VERSION 5.8 ;
BUSBITCHARS "[]" ;
DIVIDERCHAR "/" ;
UNITS
    DATABASE MICRONS 1000 ;
END UNITS

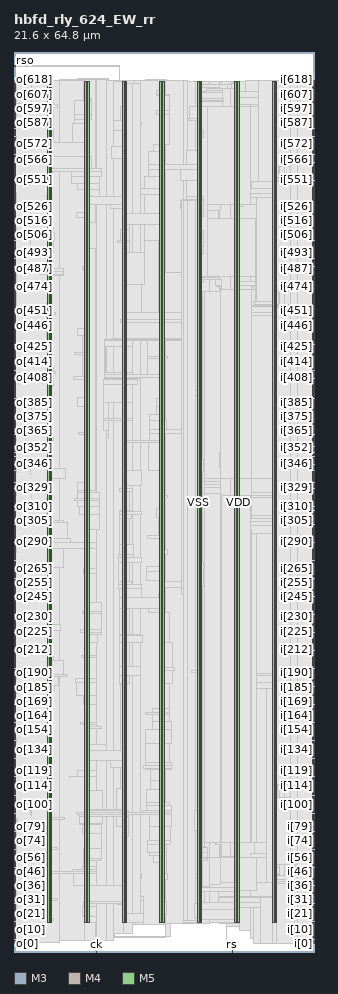
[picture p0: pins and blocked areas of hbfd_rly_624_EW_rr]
MACRO hbfd_rly_624_EW_rr
  FOREIGN hbfd_rly_624_EW_rr 0 0 ;
  CLASS BLOCK ;
  SIZE 21.6 BY 64.8 ;
  PIN ck
    DIRECTION INPUT ;
    USE SIGNAL ;
    PORT
      LAYER M3 ;
        RECT  5.904 0 5.922 0.038 ;
    END
  END ck
  PIN i[0]
    DIRECTION INPUT ;
    USE SIGNAL ;
    PORT
      LAYER M4 ;
        RECT  21.516 0.624 21.6 0.648 ;
    END
  END i[0]
  PIN i[100]
    DIRECTION INPUT ;
    USE SIGNAL ;
    PORT
      LAYER M4 ;
        RECT  21.516 10.608 21.6 10.632 ;
    END
  END i[100]
  PIN i[101]
    DIRECTION INPUT ;
    USE SIGNAL ;
    PORT
      LAYER M4 ;
        RECT  21.516 10.704 21.6 10.728 ;
    END
  END i[101]
  PIN i[102]
    DIRECTION INPUT ;
    USE SIGNAL ;
    PORT
      LAYER M4 ;
        RECT  21.516 10.8 21.6 10.824 ;
    END
  END i[102]
  PIN i[103]
    DIRECTION INPUT ;
    USE SIGNAL ;
    PORT
      LAYER M4 ;
        RECT  21.516 10.896 21.6 10.92 ;
    END
  END i[103]
  PIN i[104]
    DIRECTION INPUT ;
    USE SIGNAL ;
    PORT
      LAYER M4 ;
        RECT  21.516 10.992 21.6 11.016 ;
    END
  END i[104]
  PIN i[105]
    DIRECTION INPUT ;
    USE SIGNAL ;
    PORT
      LAYER M4 ;
        RECT  21.516 11.088 21.6 11.112 ;
    END
  END i[105]
  PIN i[106]
    DIRECTION INPUT ;
    USE SIGNAL ;
    PORT
      LAYER M4 ;
        RECT  21.516 11.184 21.6 11.208 ;
    END
  END i[106]
  PIN i[107]
    DIRECTION INPUT ;
    USE SIGNAL ;
    PORT
      LAYER M4 ;
        RECT  21.516 11.328 21.6 11.352 ;
    END
  END i[107]
  PIN i[108]
    DIRECTION INPUT ;
    USE SIGNAL ;
    PORT
      LAYER M4 ;
        RECT  21.516 11.424 21.6 11.448 ;
    END
  END i[108]
  PIN i[109]
    DIRECTION INPUT ;
    USE SIGNAL ;
    PORT
      LAYER M4 ;
        RECT  21.516 11.52 21.6 11.544 ;
    END
  END i[109]
  PIN i[10]
    DIRECTION INPUT ;
    USE SIGNAL ;
    PORT
      LAYER M4 ;
        RECT  21.516 1.632 21.6 1.656 ;
    END
  END i[10]
  PIN i[110]
    DIRECTION INPUT ;
    USE SIGNAL ;
    PORT
      LAYER M4 ;
        RECT  21.516 11.616 21.6 11.64 ;
    END
  END i[110]
  PIN i[111]
    DIRECTION INPUT ;
    USE SIGNAL ;
    PORT
      LAYER M4 ;
        RECT  21.516 11.712 21.6 11.736 ;
    END
  END i[111]
  PIN i[112]
    DIRECTION INPUT ;
    USE SIGNAL ;
    PORT
      LAYER M4 ;
        RECT  21.516 11.808 21.6 11.832 ;
    END
  END i[112]
  PIN i[113]
    DIRECTION INPUT ;
    USE SIGNAL ;
    PORT
      LAYER M4 ;
        RECT  21.516 11.904 21.6 11.928 ;
    END
  END i[113]
  PIN i[114]
    DIRECTION INPUT ;
    USE SIGNAL ;
    PORT
      LAYER M4 ;
        RECT  21.516 12 21.6 12.024 ;
    END
  END i[114]
  PIN i[115]
    DIRECTION INPUT ;
    USE SIGNAL ;
    PORT
      LAYER M4 ;
        RECT  21.516 12.096 21.6 12.12 ;
    END
  END i[115]
  PIN i[116]
    DIRECTION INPUT ;
    USE SIGNAL ;
    PORT
      LAYER M4 ;
        RECT  21.516 12.192 21.6 12.216 ;
    END
  END i[116]
  PIN i[117]
    DIRECTION INPUT ;
    USE SIGNAL ;
    PORT
      LAYER M4 ;
        RECT  21.516 12.288 21.6 12.312 ;
    END
  END i[117]
  PIN i[118]
    DIRECTION INPUT ;
    USE SIGNAL ;
    PORT
      LAYER M4 ;
        RECT  21.516 12.384 21.6 12.408 ;
    END
  END i[118]
  PIN i[119]
    DIRECTION INPUT ;
    USE SIGNAL ;
    PORT
      LAYER M4 ;
        RECT  21.516 12.48 21.6 12.504 ;
    END
  END i[119]
  PIN i[11]
    DIRECTION INPUT ;
    USE SIGNAL ;
    PORT
      LAYER M4 ;
        RECT  21.516 1.728 21.6 1.752 ;
    END
  END i[11]
  PIN i[120]
    DIRECTION INPUT ;
    USE SIGNAL ;
    PORT
      LAYER M4 ;
        RECT  21.516 12.576 21.6 12.6 ;
    END
  END i[120]
  PIN i[121]
    DIRECTION INPUT ;
    USE SIGNAL ;
    PORT
      LAYER M4 ;
        RECT  21.516 12.72 21.6 12.744 ;
    END
  END i[121]
  PIN i[122]
    DIRECTION INPUT ;
    USE SIGNAL ;
    PORT
      LAYER M4 ;
        RECT  21.516 12.816 21.6 12.84 ;
    END
  END i[122]
  PIN i[123]
    DIRECTION INPUT ;
    USE SIGNAL ;
    PORT
      LAYER M4 ;
        RECT  21.516 12.912 21.6 12.936 ;
    END
  END i[123]
  PIN i[124]
    DIRECTION INPUT ;
    USE SIGNAL ;
    PORT
      LAYER M4 ;
        RECT  21.516 13.008 21.6 13.032 ;
    END
  END i[124]
  PIN i[125]
    DIRECTION INPUT ;
    USE SIGNAL ;
    PORT
      LAYER M4 ;
        RECT  21.516 13.104 21.6 13.128 ;
    END
  END i[125]
  PIN i[126]
    DIRECTION INPUT ;
    USE SIGNAL ;
    PORT
      LAYER M4 ;
        RECT  21.516 13.2 21.6 13.224 ;
    END
  END i[126]
  PIN i[127]
    DIRECTION INPUT ;
    USE SIGNAL ;
    PORT
      LAYER M4 ;
        RECT  21.516 13.296 21.6 13.32 ;
    END
  END i[127]
  PIN i[128]
    DIRECTION INPUT ;
    USE SIGNAL ;
    PORT
      LAYER M4 ;
        RECT  21.516 13.392 21.6 13.416 ;
    END
  END i[128]
  PIN i[129]
    DIRECTION INPUT ;
    USE SIGNAL ;
    PORT
      LAYER M4 ;
        RECT  21.516 13.488 21.6 13.512 ;
    END
  END i[129]
  PIN i[12]
    DIRECTION INPUT ;
    USE SIGNAL ;
    PORT
      LAYER M4 ;
        RECT  21.516 1.824 21.6 1.848 ;
    END
  END i[12]
  PIN i[130]
    DIRECTION INPUT ;
    USE SIGNAL ;
    PORT
      LAYER M4 ;
        RECT  21.516 13.584 21.6 13.608 ;
    END
  END i[130]
  PIN i[131]
    DIRECTION INPUT ;
    USE SIGNAL ;
    PORT
      LAYER M4 ;
        RECT  21.516 13.68 21.6 13.704 ;
    END
  END i[131]
  PIN i[132]
    DIRECTION INPUT ;
    USE SIGNAL ;
    PORT
      LAYER M4 ;
        RECT  21.516 13.776 21.6 13.8 ;
    END
  END i[132]
  PIN i[133]
    DIRECTION INPUT ;
    USE SIGNAL ;
    PORT
      LAYER M4 ;
        RECT  21.516 13.872 21.6 13.896 ;
    END
  END i[133]
  PIN i[134]
    DIRECTION INPUT ;
    USE SIGNAL ;
    PORT
      LAYER M4 ;
        RECT  21.516 14.016 21.6 14.04 ;
    END
  END i[134]
  PIN i[135]
    DIRECTION INPUT ;
    USE SIGNAL ;
    PORT
      LAYER M4 ;
        RECT  21.516 14.112 21.6 14.136 ;
    END
  END i[135]
  PIN i[136]
    DIRECTION INPUT ;
    USE SIGNAL ;
    PORT
      LAYER M4 ;
        RECT  21.516 14.208 21.6 14.232 ;
    END
  END i[136]
  PIN i[137]
    DIRECTION INPUT ;
    USE SIGNAL ;
    PORT
      LAYER M4 ;
        RECT  21.516 14.304 21.6 14.328 ;
    END
  END i[137]
  PIN i[138]
    DIRECTION INPUT ;
    USE SIGNAL ;
    PORT
      LAYER M4 ;
        RECT  21.516 14.4 21.6 14.424 ;
    END
  END i[138]
  PIN i[139]
    DIRECTION INPUT ;
    USE SIGNAL ;
    PORT
      LAYER M4 ;
        RECT  21.516 14.496 21.6 14.52 ;
    END
  END i[139]
  PIN i[13]
    DIRECTION INPUT ;
    USE SIGNAL ;
    PORT
      LAYER M4 ;
        RECT  21.516 1.92 21.6 1.944 ;
    END
  END i[13]
  PIN i[140]
    DIRECTION INPUT ;
    USE SIGNAL ;
    PORT
      LAYER M4 ;
        RECT  21.516 14.592 21.6 14.616 ;
    END
  END i[140]
  PIN i[141]
    DIRECTION INPUT ;
    USE SIGNAL ;
    PORT
      LAYER M4 ;
        RECT  21.516 14.688 21.6 14.712 ;
    END
  END i[141]
  PIN i[142]
    DIRECTION INPUT ;
    USE SIGNAL ;
    PORT
      LAYER M4 ;
        RECT  21.516 14.784 21.6 14.808 ;
    END
  END i[142]
  PIN i[143]
    DIRECTION INPUT ;
    USE SIGNAL ;
    PORT
      LAYER M4 ;
        RECT  21.516 14.88 21.6 14.904 ;
    END
  END i[143]
  PIN i[144]
    DIRECTION INPUT ;
    USE SIGNAL ;
    PORT
      LAYER M4 ;
        RECT  21.516 14.976 21.6 15 ;
    END
  END i[144]
  PIN i[145]
    DIRECTION INPUT ;
    USE SIGNAL ;
    PORT
      LAYER M4 ;
        RECT  21.516 15.072 21.6 15.096 ;
    END
  END i[145]
  PIN i[146]
    DIRECTION INPUT ;
    USE SIGNAL ;
    PORT
      LAYER M4 ;
        RECT  21.516 15.168 21.6 15.192 ;
    END
  END i[146]
  PIN i[147]
    DIRECTION INPUT ;
    USE SIGNAL ;
    PORT
      LAYER M4 ;
        RECT  21.516 15.312 21.6 15.336 ;
    END
  END i[147]
  PIN i[148]
    DIRECTION INPUT ;
    USE SIGNAL ;
    PORT
      LAYER M4 ;
        RECT  21.516 15.408 21.6 15.432 ;
    END
  END i[148]
  PIN i[149]
    DIRECTION INPUT ;
    USE SIGNAL ;
    PORT
      LAYER M4 ;
        RECT  21.516 15.504 21.6 15.528 ;
    END
  END i[149]
  PIN i[14]
    DIRECTION INPUT ;
    USE SIGNAL ;
    PORT
      LAYER M4 ;
        RECT  21.516 2.016 21.6 2.04 ;
    END
  END i[14]
  PIN i[150]
    DIRECTION INPUT ;
    USE SIGNAL ;
    PORT
      LAYER M4 ;
        RECT  21.516 15.6 21.6 15.624 ;
    END
  END i[150]
  PIN i[151]
    DIRECTION INPUT ;
    USE SIGNAL ;
    PORT
      LAYER M4 ;
        RECT  21.516 15.696 21.6 15.72 ;
    END
  END i[151]
  PIN i[152]
    DIRECTION INPUT ;
    USE SIGNAL ;
    PORT
      LAYER M4 ;
        RECT  21.516 15.792 21.6 15.816 ;
    END
  END i[152]
  PIN i[153]
    DIRECTION INPUT ;
    USE SIGNAL ;
    PORT
      LAYER M4 ;
        RECT  21.516 15.888 21.6 15.912 ;
    END
  END i[153]
  PIN i[154]
    DIRECTION INPUT ;
    USE SIGNAL ;
    PORT
      LAYER M4 ;
        RECT  21.516 15.984 21.6 16.008 ;
    END
  END i[154]
  PIN i[155]
    DIRECTION INPUT ;
    USE SIGNAL ;
    PORT
      LAYER M4 ;
        RECT  21.516 16.08 21.6 16.104 ;
    END
  END i[155]
  PIN i[156]
    DIRECTION INPUT ;
    USE SIGNAL ;
    PORT
      LAYER M4 ;
        RECT  21.516 16.176 21.6 16.2 ;
    END
  END i[156]
  PIN i[157]
    DIRECTION INPUT ;
    USE SIGNAL ;
    PORT
      LAYER M4 ;
        RECT  21.516 16.272 21.6 16.296 ;
    END
  END i[157]
  PIN i[158]
    DIRECTION INPUT ;
    USE SIGNAL ;
    PORT
      LAYER M4 ;
        RECT  21.516 16.368 21.6 16.392 ;
    END
  END i[158]
  PIN i[159]
    DIRECTION INPUT ;
    USE SIGNAL ;
    PORT
      LAYER M4 ;
        RECT  21.516 16.464 21.6 16.488 ;
    END
  END i[159]
  PIN i[15]
    DIRECTION INPUT ;
    USE SIGNAL ;
    PORT
      LAYER M4 ;
        RECT  21.516 2.112 21.6 2.136 ;
    END
  END i[15]
  PIN i[160]
    DIRECTION INPUT ;
    USE SIGNAL ;
    PORT
      LAYER M4 ;
        RECT  21.516 16.608 21.6 16.632 ;
    END
  END i[160]
  PIN i[161]
    DIRECTION INPUT ;
    USE SIGNAL ;
    PORT
      LAYER M4 ;
        RECT  21.516 16.704 21.6 16.728 ;
    END
  END i[161]
  PIN i[162]
    DIRECTION INPUT ;
    USE SIGNAL ;
    PORT
      LAYER M4 ;
        RECT  21.516 16.8 21.6 16.824 ;
    END
  END i[162]
  PIN i[163]
    DIRECTION INPUT ;
    USE SIGNAL ;
    PORT
      LAYER M4 ;
        RECT  21.516 16.896 21.6 16.92 ;
    END
  END i[163]
  PIN i[164]
    DIRECTION INPUT ;
    USE SIGNAL ;
    PORT
      LAYER M4 ;
        RECT  21.516 16.992 21.6 17.016 ;
    END
  END i[164]
  PIN i[165]
    DIRECTION INPUT ;
    USE SIGNAL ;
    PORT
      LAYER M4 ;
        RECT  21.516 17.088 21.6 17.112 ;
    END
  END i[165]
  PIN i[166]
    DIRECTION INPUT ;
    USE SIGNAL ;
    PORT
      LAYER M4 ;
        RECT  21.516 17.184 21.6 17.208 ;
    END
  END i[166]
  PIN i[167]
    DIRECTION INPUT ;
    USE SIGNAL ;
    PORT
      LAYER M4 ;
        RECT  21.516 17.28 21.6 17.304 ;
    END
  END i[167]
  PIN i[168]
    DIRECTION INPUT ;
    USE SIGNAL ;
    PORT
      LAYER M4 ;
        RECT  21.516 17.376 21.6 17.4 ;
    END
  END i[168]
  PIN i[169]
    DIRECTION INPUT ;
    USE SIGNAL ;
    PORT
      LAYER M4 ;
        RECT  21.516 17.472 21.6 17.496 ;
    END
  END i[169]
  PIN i[16]
    DIRECTION INPUT ;
    USE SIGNAL ;
    PORT
      LAYER M4 ;
        RECT  21.516 2.256 21.6 2.28 ;
    END
  END i[16]
  PIN i[170]
    DIRECTION INPUT ;
    USE SIGNAL ;
    PORT
      LAYER M4 ;
        RECT  21.516 17.568 21.6 17.592 ;
    END
  END i[170]
  PIN i[171]
    DIRECTION INPUT ;
    USE SIGNAL ;
    PORT
      LAYER M4 ;
        RECT  21.516 17.664 21.6 17.688 ;
    END
  END i[171]
  PIN i[172]
    DIRECTION INPUT ;
    USE SIGNAL ;
    PORT
      LAYER M4 ;
        RECT  21.516 17.76 21.6 17.784 ;
    END
  END i[172]
  PIN i[173]
    DIRECTION INPUT ;
    USE SIGNAL ;
    PORT
      LAYER M4 ;
        RECT  21.516 17.904 21.6 17.928 ;
    END
  END i[173]
  PIN i[174]
    DIRECTION INPUT ;
    USE SIGNAL ;
    PORT
      LAYER M4 ;
        RECT  21.516 18 21.6 18.024 ;
    END
  END i[174]
  PIN i[175]
    DIRECTION INPUT ;
    USE SIGNAL ;
    PORT
      LAYER M4 ;
        RECT  21.516 18.096 21.6 18.12 ;
    END
  END i[175]
  PIN i[176]
    DIRECTION INPUT ;
    USE SIGNAL ;
    PORT
      LAYER M4 ;
        RECT  21.516 18.192 21.6 18.216 ;
    END
  END i[176]
  PIN i[177]
    DIRECTION INPUT ;
    USE SIGNAL ;
    PORT
      LAYER M4 ;
        RECT  21.516 18.288 21.6 18.312 ;
    END
  END i[177]
  PIN i[178]
    DIRECTION INPUT ;
    USE SIGNAL ;
    PORT
      LAYER M4 ;
        RECT  21.516 18.384 21.6 18.408 ;
    END
  END i[178]
  PIN i[179]
    DIRECTION INPUT ;
    USE SIGNAL ;
    PORT
      LAYER M4 ;
        RECT  21.516 18.48 21.6 18.504 ;
    END
  END i[179]
  PIN i[17]
    DIRECTION INPUT ;
    USE SIGNAL ;
    PORT
      LAYER M4 ;
        RECT  21.516 2.352 21.6 2.376 ;
    END
  END i[17]
  PIN i[180]
    DIRECTION INPUT ;
    USE SIGNAL ;
    PORT
      LAYER M4 ;
        RECT  21.516 18.576 21.6 18.6 ;
    END
  END i[180]
  PIN i[181]
    DIRECTION INPUT ;
    USE SIGNAL ;
    PORT
      LAYER M4 ;
        RECT  21.516 18.672 21.6 18.696 ;
    END
  END i[181]
  PIN i[182]
    DIRECTION INPUT ;
    USE SIGNAL ;
    PORT
      LAYER M4 ;
        RECT  21.516 18.768 21.6 18.792 ;
    END
  END i[182]
  PIN i[183]
    DIRECTION INPUT ;
    USE SIGNAL ;
    PORT
      LAYER M4 ;
        RECT  21.516 18.864 21.6 18.888 ;
    END
  END i[183]
  PIN i[184]
    DIRECTION INPUT ;
    USE SIGNAL ;
    PORT
      LAYER M4 ;
        RECT  21.516 18.96 21.6 18.984 ;
    END
  END i[184]
  PIN i[185]
    DIRECTION INPUT ;
    USE SIGNAL ;
    PORT
      LAYER M4 ;
        RECT  21.516 19.056 21.6 19.08 ;
    END
  END i[185]
  PIN i[186]
    DIRECTION INPUT ;
    USE SIGNAL ;
    PORT
      LAYER M4 ;
        RECT  21.516 19.2 21.6 19.224 ;
    END
  END i[186]
  PIN i[187]
    DIRECTION INPUT ;
    USE SIGNAL ;
    PORT
      LAYER M4 ;
        RECT  21.516 19.296 21.6 19.32 ;
    END
  END i[187]
  PIN i[188]
    DIRECTION INPUT ;
    USE SIGNAL ;
    PORT
      LAYER M4 ;
        RECT  21.516 19.392 21.6 19.416 ;
    END
  END i[188]
  PIN i[189]
    DIRECTION INPUT ;
    USE SIGNAL ;
    PORT
      LAYER M4 ;
        RECT  21.516 19.488 21.6 19.512 ;
    END
  END i[189]
  PIN i[18]
    DIRECTION INPUT ;
    USE SIGNAL ;
    PORT
      LAYER M4 ;
        RECT  21.516 2.448 21.6 2.472 ;
    END
  END i[18]
  PIN i[190]
    DIRECTION INPUT ;
    USE SIGNAL ;
    PORT
      LAYER M4 ;
        RECT  21.516 19.584 21.6 19.608 ;
    END
  END i[190]
  PIN i[191]
    DIRECTION INPUT ;
    USE SIGNAL ;
    PORT
      LAYER M4 ;
        RECT  21.516 19.68 21.6 19.704 ;
    END
  END i[191]
  PIN i[192]
    DIRECTION INPUT ;
    USE SIGNAL ;
    PORT
      LAYER M4 ;
        RECT  21.516 19.776 21.6 19.8 ;
    END
  END i[192]
  PIN i[193]
    DIRECTION INPUT ;
    USE SIGNAL ;
    PORT
      LAYER M4 ;
        RECT  21.516 19.872 21.6 19.896 ;
    END
  END i[193]
  PIN i[194]
    DIRECTION INPUT ;
    USE SIGNAL ;
    PORT
      LAYER M4 ;
        RECT  21.516 19.968 21.6 19.992 ;
    END
  END i[194]
  PIN i[195]
    DIRECTION INPUT ;
    USE SIGNAL ;
    PORT
      LAYER M4 ;
        RECT  21.516 20.064 21.6 20.088 ;
    END
  END i[195]
  PIN i[196]
    DIRECTION INPUT ;
    USE SIGNAL ;
    PORT
      LAYER M4 ;
        RECT  21.516 20.16 21.6 20.184 ;
    END
  END i[196]
  PIN i[197]
    DIRECTION INPUT ;
    USE SIGNAL ;
    PORT
      LAYER M4 ;
        RECT  21.516 20.256 21.6 20.28 ;
    END
  END i[197]
  PIN i[198]
    DIRECTION INPUT ;
    USE SIGNAL ;
    PORT
      LAYER M4 ;
        RECT  21.516 20.352 21.6 20.376 ;
    END
  END i[198]
  PIN i[199]
    DIRECTION INPUT ;
    USE SIGNAL ;
    PORT
      LAYER M4 ;
        RECT  21.516 20.496 21.6 20.52 ;
    END
  END i[199]
  PIN i[19]
    DIRECTION INPUT ;
    USE SIGNAL ;
    PORT
      LAYER M4 ;
        RECT  21.516 2.544 21.6 2.568 ;
    END
  END i[19]
  PIN i[1]
    DIRECTION INPUT ;
    USE SIGNAL ;
    PORT
      LAYER M4 ;
        RECT  21.516 0.72 21.6 0.744 ;
    END
  END i[1]
  PIN i[200]
    DIRECTION INPUT ;
    USE SIGNAL ;
    PORT
      LAYER M4 ;
        RECT  21.516 20.592 21.6 20.616 ;
    END
  END i[200]
  PIN i[201]
    DIRECTION INPUT ;
    USE SIGNAL ;
    PORT
      LAYER M4 ;
        RECT  21.516 20.688 21.6 20.712 ;
    END
  END i[201]
  PIN i[202]
    DIRECTION INPUT ;
    USE SIGNAL ;
    PORT
      LAYER M4 ;
        RECT  21.516 20.784 21.6 20.808 ;
    END
  END i[202]
  PIN i[203]
    DIRECTION INPUT ;
    USE SIGNAL ;
    PORT
      LAYER M4 ;
        RECT  21.516 20.88 21.6 20.904 ;
    END
  END i[203]
  PIN i[204]
    DIRECTION INPUT ;
    USE SIGNAL ;
    PORT
      LAYER M4 ;
        RECT  21.516 20.976 21.6 21 ;
    END
  END i[204]
  PIN i[205]
    DIRECTION INPUT ;
    USE SIGNAL ;
    PORT
      LAYER M4 ;
        RECT  21.516 21.072 21.6 21.096 ;
    END
  END i[205]
  PIN i[206]
    DIRECTION INPUT ;
    USE SIGNAL ;
    PORT
      LAYER M4 ;
        RECT  21.516 21.168 21.6 21.192 ;
    END
  END i[206]
  PIN i[207]
    DIRECTION INPUT ;
    USE SIGNAL ;
    PORT
      LAYER M4 ;
        RECT  21.516 21.264 21.6 21.288 ;
    END
  END i[207]
  PIN i[208]
    DIRECTION INPUT ;
    USE SIGNAL ;
    PORT
      LAYER M4 ;
        RECT  21.516 21.36 21.6 21.384 ;
    END
  END i[208]
  PIN i[209]
    DIRECTION INPUT ;
    USE SIGNAL ;
    PORT
      LAYER M4 ;
        RECT  21.516 21.456 21.6 21.48 ;
    END
  END i[209]
  PIN i[20]
    DIRECTION INPUT ;
    USE SIGNAL ;
    PORT
      LAYER M4 ;
        RECT  21.516 2.64 21.6 2.664 ;
    END
  END i[20]
  PIN i[210]
    DIRECTION INPUT ;
    USE SIGNAL ;
    PORT
      LAYER M4 ;
        RECT  21.516 21.552 21.6 21.576 ;
    END
  END i[210]
  PIN i[211]
    DIRECTION INPUT ;
    USE SIGNAL ;
    PORT
      LAYER M4 ;
        RECT  21.516 21.648 21.6 21.672 ;
    END
  END i[211]
  PIN i[212]
    DIRECTION INPUT ;
    USE SIGNAL ;
    PORT
      LAYER M4 ;
        RECT  21.516 21.792 21.6 21.816 ;
    END
  END i[212]
  PIN i[213]
    DIRECTION INPUT ;
    USE SIGNAL ;
    PORT
      LAYER M4 ;
        RECT  21.516 21.888 21.6 21.912 ;
    END
  END i[213]
  PIN i[214]
    DIRECTION INPUT ;
    USE SIGNAL ;
    PORT
      LAYER M4 ;
        RECT  21.516 21.984 21.6 22.008 ;
    END
  END i[214]
  PIN i[215]
    DIRECTION INPUT ;
    USE SIGNAL ;
    PORT
      LAYER M4 ;
        RECT  21.516 22.08 21.6 22.104 ;
    END
  END i[215]
  PIN i[216]
    DIRECTION INPUT ;
    USE SIGNAL ;
    PORT
      LAYER M4 ;
        RECT  21.516 22.176 21.6 22.2 ;
    END
  END i[216]
  PIN i[217]
    DIRECTION INPUT ;
    USE SIGNAL ;
    PORT
      LAYER M4 ;
        RECT  21.516 22.272 21.6 22.296 ;
    END
  END i[217]
  PIN i[218]
    DIRECTION INPUT ;
    USE SIGNAL ;
    PORT
      LAYER M4 ;
        RECT  21.516 22.368 21.6 22.392 ;
    END
  END i[218]
  PIN i[219]
    DIRECTION INPUT ;
    USE SIGNAL ;
    PORT
      LAYER M4 ;
        RECT  21.516 22.464 21.6 22.488 ;
    END
  END i[219]
  PIN i[21]
    DIRECTION INPUT ;
    USE SIGNAL ;
    PORT
      LAYER M4 ;
        RECT  21.516 2.736 21.6 2.76 ;
    END
  END i[21]
  PIN i[220]
    DIRECTION INPUT ;
    USE SIGNAL ;
    PORT
      LAYER M4 ;
        RECT  21.516 22.56 21.6 22.584 ;
    END
  END i[220]
  PIN i[221]
    DIRECTION INPUT ;
    USE SIGNAL ;
    PORT
      LAYER M4 ;
        RECT  21.516 22.656 21.6 22.68 ;
    END
  END i[221]
  PIN i[222]
    DIRECTION INPUT ;
    USE SIGNAL ;
    PORT
      LAYER M4 ;
        RECT  21.516 22.752 21.6 22.776 ;
    END
  END i[222]
  PIN i[223]
    DIRECTION INPUT ;
    USE SIGNAL ;
    PORT
      LAYER M4 ;
        RECT  21.516 22.848 21.6 22.872 ;
    END
  END i[223]
  PIN i[224]
    DIRECTION INPUT ;
    USE SIGNAL ;
    PORT
      LAYER M4 ;
        RECT  21.516 22.944 21.6 22.968 ;
    END
  END i[224]
  PIN i[225]
    DIRECTION INPUT ;
    USE SIGNAL ;
    PORT
      LAYER M4 ;
        RECT  21.516 23.088 21.6 23.112 ;
    END
  END i[225]
  PIN i[226]
    DIRECTION INPUT ;
    USE SIGNAL ;
    PORT
      LAYER M4 ;
        RECT  21.516 23.184 21.6 23.208 ;
    END
  END i[226]
  PIN i[227]
    DIRECTION INPUT ;
    USE SIGNAL ;
    PORT
      LAYER M4 ;
        RECT  21.516 23.28 21.6 23.304 ;
    END
  END i[227]
  PIN i[228]
    DIRECTION INPUT ;
    USE SIGNAL ;
    PORT
      LAYER M4 ;
        RECT  21.516 23.376 21.6 23.4 ;
    END
  END i[228]
  PIN i[229]
    DIRECTION INPUT ;
    USE SIGNAL ;
    PORT
      LAYER M4 ;
        RECT  21.516 23.472 21.6 23.496 ;
    END
  END i[229]
  PIN i[22]
    DIRECTION INPUT ;
    USE SIGNAL ;
    PORT
      LAYER M4 ;
        RECT  21.516 2.832 21.6 2.856 ;
    END
  END i[22]
  PIN i[230]
    DIRECTION INPUT ;
    USE SIGNAL ;
    PORT
      LAYER M4 ;
        RECT  21.516 23.568 21.6 23.592 ;
    END
  END i[230]
  PIN i[231]
    DIRECTION INPUT ;
    USE SIGNAL ;
    PORT
      LAYER M4 ;
        RECT  21.516 23.664 21.6 23.688 ;
    END
  END i[231]
  PIN i[232]
    DIRECTION INPUT ;
    USE SIGNAL ;
    PORT
      LAYER M4 ;
        RECT  21.516 23.76 21.6 23.784 ;
    END
  END i[232]
  PIN i[233]
    DIRECTION INPUT ;
    USE SIGNAL ;
    PORT
      LAYER M4 ;
        RECT  21.516 23.856 21.6 23.88 ;
    END
  END i[233]
  PIN i[234]
    DIRECTION INPUT ;
    USE SIGNAL ;
    PORT
      LAYER M4 ;
        RECT  21.516 23.952 21.6 23.976 ;
    END
  END i[234]
  PIN i[235]
    DIRECTION INPUT ;
    USE SIGNAL ;
    PORT
      LAYER M4 ;
        RECT  21.516 24.048 21.6 24.072 ;
    END
  END i[235]
  PIN i[236]
    DIRECTION INPUT ;
    USE SIGNAL ;
    PORT
      LAYER M4 ;
        RECT  21.516 24.144 21.6 24.168 ;
    END
  END i[236]
  PIN i[237]
    DIRECTION INPUT ;
    USE SIGNAL ;
    PORT
      LAYER M4 ;
        RECT  21.516 24.24 21.6 24.264 ;
    END
  END i[237]
  PIN i[238]
    DIRECTION INPUT ;
    USE SIGNAL ;
    PORT
      LAYER M4 ;
        RECT  21.516 24.384 21.6 24.408 ;
    END
  END i[238]
  PIN i[239]
    DIRECTION INPUT ;
    USE SIGNAL ;
    PORT
      LAYER M4 ;
        RECT  21.516 24.48 21.6 24.504 ;
    END
  END i[239]
  PIN i[23]
    DIRECTION INPUT ;
    USE SIGNAL ;
    PORT
      LAYER M4 ;
        RECT  21.516 2.928 21.6 2.952 ;
    END
  END i[23]
  PIN i[240]
    DIRECTION INPUT ;
    USE SIGNAL ;
    PORT
      LAYER M4 ;
        RECT  21.516 24.576 21.6 24.6 ;
    END
  END i[240]
  PIN i[241]
    DIRECTION INPUT ;
    USE SIGNAL ;
    PORT
      LAYER M4 ;
        RECT  21.516 24.672 21.6 24.696 ;
    END
  END i[241]
  PIN i[242]
    DIRECTION INPUT ;
    USE SIGNAL ;
    PORT
      LAYER M4 ;
        RECT  21.516 24.768 21.6 24.792 ;
    END
  END i[242]
  PIN i[243]
    DIRECTION INPUT ;
    USE SIGNAL ;
    PORT
      LAYER M4 ;
        RECT  21.516 24.864 21.6 24.888 ;
    END
  END i[243]
  PIN i[244]
    DIRECTION INPUT ;
    USE SIGNAL ;
    PORT
      LAYER M4 ;
        RECT  21.516 24.96 21.6 24.984 ;
    END
  END i[244]
  PIN i[245]
    DIRECTION INPUT ;
    USE SIGNAL ;
    PORT
      LAYER M4 ;
        RECT  21.516 25.056 21.6 25.08 ;
    END
  END i[245]
  PIN i[246]
    DIRECTION INPUT ;
    USE SIGNAL ;
    PORT
      LAYER M4 ;
        RECT  21.516 25.152 21.6 25.176 ;
    END
  END i[246]
  PIN i[247]
    DIRECTION INPUT ;
    USE SIGNAL ;
    PORT
      LAYER M4 ;
        RECT  21.516 25.248 21.6 25.272 ;
    END
  END i[247]
  PIN i[248]
    DIRECTION INPUT ;
    USE SIGNAL ;
    PORT
      LAYER M4 ;
        RECT  21.516 25.344 21.6 25.368 ;
    END
  END i[248]
  PIN i[249]
    DIRECTION INPUT ;
    USE SIGNAL ;
    PORT
      LAYER M4 ;
        RECT  21.516 25.44 21.6 25.464 ;
    END
  END i[249]
  PIN i[24]
    DIRECTION INPUT ;
    USE SIGNAL ;
    PORT
      LAYER M4 ;
        RECT  21.516 3.024 21.6 3.048 ;
    END
  END i[24]
  PIN i[250]
    DIRECTION INPUT ;
    USE SIGNAL ;
    PORT
      LAYER M4 ;
        RECT  21.516 25.536 21.6 25.56 ;
    END
  END i[250]
  PIN i[251]
    DIRECTION INPUT ;
    USE SIGNAL ;
    PORT
      LAYER M4 ;
        RECT  21.516 25.68 21.6 25.704 ;
    END
  END i[251]
  PIN i[252]
    DIRECTION INPUT ;
    USE SIGNAL ;
    PORT
      LAYER M4 ;
        RECT  21.516 25.776 21.6 25.8 ;
    END
  END i[252]
  PIN i[253]
    DIRECTION INPUT ;
    USE SIGNAL ;
    PORT
      LAYER M4 ;
        RECT  21.516 25.872 21.6 25.896 ;
    END
  END i[253]
  PIN i[254]
    DIRECTION INPUT ;
    USE SIGNAL ;
    PORT
      LAYER M4 ;
        RECT  21.516 25.968 21.6 25.992 ;
    END
  END i[254]
  PIN i[255]
    DIRECTION INPUT ;
    USE SIGNAL ;
    PORT
      LAYER M4 ;
        RECT  21.516 26.064 21.6 26.088 ;
    END
  END i[255]
  PIN i[256]
    DIRECTION INPUT ;
    USE SIGNAL ;
    PORT
      LAYER M4 ;
        RECT  21.516 26.16 21.6 26.184 ;
    END
  END i[256]
  PIN i[257]
    DIRECTION INPUT ;
    USE SIGNAL ;
    PORT
      LAYER M4 ;
        RECT  21.516 26.256 21.6 26.28 ;
    END
  END i[257]
  PIN i[258]
    DIRECTION INPUT ;
    USE SIGNAL ;
    PORT
      LAYER M4 ;
        RECT  21.516 26.352 21.6 26.376 ;
    END
  END i[258]
  PIN i[259]
    DIRECTION INPUT ;
    USE SIGNAL ;
    PORT
      LAYER M4 ;
        RECT  21.516 26.448 21.6 26.472 ;
    END
  END i[259]
  PIN i[25]
    DIRECTION INPUT ;
    USE SIGNAL ;
    PORT
      LAYER M4 ;
        RECT  21.516 3.12 21.6 3.144 ;
    END
  END i[25]
  PIN i[260]
    DIRECTION INPUT ;
    USE SIGNAL ;
    PORT
      LAYER M4 ;
        RECT  21.516 26.544 21.6 26.568 ;
    END
  END i[260]
  PIN i[261]
    DIRECTION INPUT ;
    USE SIGNAL ;
    PORT
      LAYER M4 ;
        RECT  21.516 26.64 21.6 26.664 ;
    END
  END i[261]
  PIN i[262]
    DIRECTION INPUT ;
    USE SIGNAL ;
    PORT
      LAYER M4 ;
        RECT  21.516 26.736 21.6 26.76 ;
    END
  END i[262]
  PIN i[263]
    DIRECTION INPUT ;
    USE SIGNAL ;
    PORT
      LAYER M4 ;
        RECT  21.516 26.832 21.6 26.856 ;
    END
  END i[263]
  PIN i[264]
    DIRECTION INPUT ;
    USE SIGNAL ;
    PORT
      LAYER M4 ;
        RECT  21.516 26.976 21.6 27 ;
    END
  END i[264]
  PIN i[265]
    DIRECTION INPUT ;
    USE SIGNAL ;
    PORT
      LAYER M4 ;
        RECT  21.516 27.072 21.6 27.096 ;
    END
  END i[265]
  PIN i[266]
    DIRECTION INPUT ;
    USE SIGNAL ;
    PORT
      LAYER M4 ;
        RECT  21.516 27.168 21.6 27.192 ;
    END
  END i[266]
  PIN i[267]
    DIRECTION INPUT ;
    USE SIGNAL ;
    PORT
      LAYER M4 ;
        RECT  21.516 27.264 21.6 27.288 ;
    END
  END i[267]
  PIN i[268]
    DIRECTION INPUT ;
    USE SIGNAL ;
    PORT
      LAYER M4 ;
        RECT  21.516 27.36 21.6 27.384 ;
    END
  END i[268]
  PIN i[269]
    DIRECTION INPUT ;
    USE SIGNAL ;
    PORT
      LAYER M4 ;
        RECT  21.516 27.456 21.6 27.48 ;
    END
  END i[269]
  PIN i[26]
    DIRECTION INPUT ;
    USE SIGNAL ;
    PORT
      LAYER M4 ;
        RECT  21.516 3.216 21.6 3.24 ;
    END
  END i[26]
  PIN i[270]
    DIRECTION INPUT ;
    USE SIGNAL ;
    PORT
      LAYER M4 ;
        RECT  21.516 27.552 21.6 27.576 ;
    END
  END i[270]
  PIN i[271]
    DIRECTION INPUT ;
    USE SIGNAL ;
    PORT
      LAYER M4 ;
        RECT  21.516 27.648 21.6 27.672 ;
    END
  END i[271]
  PIN i[272]
    DIRECTION INPUT ;
    USE SIGNAL ;
    PORT
      LAYER M4 ;
        RECT  21.516 27.744 21.6 27.768 ;
    END
  END i[272]
  PIN i[273]
    DIRECTION INPUT ;
    USE SIGNAL ;
    PORT
      LAYER M4 ;
        RECT  21.516 27.84 21.6 27.864 ;
    END
  END i[273]
  PIN i[274]
    DIRECTION INPUT ;
    USE SIGNAL ;
    PORT
      LAYER M4 ;
        RECT  21.516 27.936 21.6 27.96 ;
    END
  END i[274]
  PIN i[275]
    DIRECTION INPUT ;
    USE SIGNAL ;
    PORT
      LAYER M4 ;
        RECT  21.516 28.032 21.6 28.056 ;
    END
  END i[275]
  PIN i[276]
    DIRECTION INPUT ;
    USE SIGNAL ;
    PORT
      LAYER M4 ;
        RECT  21.516 28.128 21.6 28.152 ;
    END
  END i[276]
  PIN i[277]
    DIRECTION INPUT ;
    USE SIGNAL ;
    PORT
      LAYER M4 ;
        RECT  21.516 28.272 21.6 28.296 ;
    END
  END i[277]
  PIN i[278]
    DIRECTION INPUT ;
    USE SIGNAL ;
    PORT
      LAYER M4 ;
        RECT  21.516 28.368 21.6 28.392 ;
    END
  END i[278]
  PIN i[279]
    DIRECTION INPUT ;
    USE SIGNAL ;
    PORT
      LAYER M4 ;
        RECT  21.516 28.464 21.6 28.488 ;
    END
  END i[279]
  PIN i[27]
    DIRECTION INPUT ;
    USE SIGNAL ;
    PORT
      LAYER M4 ;
        RECT  21.516 3.312 21.6 3.336 ;
    END
  END i[27]
  PIN i[280]
    DIRECTION INPUT ;
    USE SIGNAL ;
    PORT
      LAYER M4 ;
        RECT  21.516 28.56 21.6 28.584 ;
    END
  END i[280]
  PIN i[281]
    DIRECTION INPUT ;
    USE SIGNAL ;
    PORT
      LAYER M4 ;
        RECT  21.516 28.656 21.6 28.68 ;
    END
  END i[281]
  PIN i[282]
    DIRECTION INPUT ;
    USE SIGNAL ;
    PORT
      LAYER M4 ;
        RECT  21.516 28.752 21.6 28.776 ;
    END
  END i[282]
  PIN i[283]
    DIRECTION INPUT ;
    USE SIGNAL ;
    PORT
      LAYER M4 ;
        RECT  21.516 28.848 21.6 28.872 ;
    END
  END i[283]
  PIN i[284]
    DIRECTION INPUT ;
    USE SIGNAL ;
    PORT
      LAYER M4 ;
        RECT  21.516 28.944 21.6 28.968 ;
    END
  END i[284]
  PIN i[285]
    DIRECTION INPUT ;
    USE SIGNAL ;
    PORT
      LAYER M4 ;
        RECT  21.516 29.04 21.6 29.064 ;
    END
  END i[285]
  PIN i[286]
    DIRECTION INPUT ;
    USE SIGNAL ;
    PORT
      LAYER M4 ;
        RECT  21.516 29.136 21.6 29.16 ;
    END
  END i[286]
  PIN i[287]
    DIRECTION INPUT ;
    USE SIGNAL ;
    PORT
      LAYER M4 ;
        RECT  21.516 29.232 21.6 29.256 ;
    END
  END i[287]
  PIN i[288]
    DIRECTION INPUT ;
    USE SIGNAL ;
    PORT
      LAYER M4 ;
        RECT  21.516 29.328 21.6 29.352 ;
    END
  END i[288]
  PIN i[289]
    DIRECTION INPUT ;
    USE SIGNAL ;
    PORT
      LAYER M4 ;
        RECT  21.516 29.424 21.6 29.448 ;
    END
  END i[289]
  PIN i[28]
    DIRECTION INPUT ;
    USE SIGNAL ;
    PORT
      LAYER M4 ;
        RECT  21.516 3.408 21.6 3.432 ;
    END
  END i[28]
  PIN i[290]
    DIRECTION INPUT ;
    USE SIGNAL ;
    PORT
      LAYER M4 ;
        RECT  21.516 29.568 21.6 29.592 ;
    END
  END i[290]
  PIN i[291]
    DIRECTION INPUT ;
    USE SIGNAL ;
    PORT
      LAYER M4 ;
        RECT  21.516 29.664 21.6 29.688 ;
    END
  END i[291]
  PIN i[292]
    DIRECTION INPUT ;
    USE SIGNAL ;
    PORT
      LAYER M4 ;
        RECT  21.516 29.76 21.6 29.784 ;
    END
  END i[292]
  PIN i[293]
    DIRECTION INPUT ;
    USE SIGNAL ;
    PORT
      LAYER M4 ;
        RECT  21.516 29.856 21.6 29.88 ;
    END
  END i[293]
  PIN i[294]
    DIRECTION INPUT ;
    USE SIGNAL ;
    PORT
      LAYER M4 ;
        RECT  21.516 29.952 21.6 29.976 ;
    END
  END i[294]
  PIN i[295]
    DIRECTION INPUT ;
    USE SIGNAL ;
    PORT
      LAYER M4 ;
        RECT  21.516 30.048 21.6 30.072 ;
    END
  END i[295]
  PIN i[296]
    DIRECTION INPUT ;
    USE SIGNAL ;
    PORT
      LAYER M4 ;
        RECT  21.516 30.144 21.6 30.168 ;
    END
  END i[296]
  PIN i[297]
    DIRECTION INPUT ;
    USE SIGNAL ;
    PORT
      LAYER M4 ;
        RECT  21.516 30.24 21.6 30.264 ;
    END
  END i[297]
  PIN i[298]
    DIRECTION INPUT ;
    USE SIGNAL ;
    PORT
      LAYER M4 ;
        RECT  21.516 30.336 21.6 30.36 ;
    END
  END i[298]
  PIN i[299]
    DIRECTION INPUT ;
    USE SIGNAL ;
    PORT
      LAYER M4 ;
        RECT  21.516 30.432 21.6 30.456 ;
    END
  END i[299]
  PIN i[29]
    DIRECTION INPUT ;
    USE SIGNAL ;
    PORT
      LAYER M4 ;
        RECT  21.516 3.552 21.6 3.576 ;
    END
  END i[29]
  PIN i[2]
    DIRECTION INPUT ;
    USE SIGNAL ;
    PORT
      LAYER M4 ;
        RECT  21.516 0.816 21.6 0.84 ;
    END
  END i[2]
  PIN i[300]
    DIRECTION INPUT ;
    USE SIGNAL ;
    PORT
      LAYER M4 ;
        RECT  21.516 30.528 21.6 30.552 ;
    END
  END i[300]
  PIN i[301]
    DIRECTION INPUT ;
    USE SIGNAL ;
    PORT
      LAYER M4 ;
        RECT  21.516 30.624 21.6 30.648 ;
    END
  END i[301]
  PIN i[302]
    DIRECTION INPUT ;
    USE SIGNAL ;
    PORT
      LAYER M4 ;
        RECT  21.516 30.72 21.6 30.744 ;
    END
  END i[302]
  PIN i[303]
    DIRECTION INPUT ;
    USE SIGNAL ;
    PORT
      LAYER M4 ;
        RECT  21.516 30.864 21.6 30.888 ;
    END
  END i[303]
  PIN i[304]
    DIRECTION INPUT ;
    USE SIGNAL ;
    PORT
      LAYER M4 ;
        RECT  21.516 30.96 21.6 30.984 ;
    END
  END i[304]
  PIN i[305]
    DIRECTION INPUT ;
    USE SIGNAL ;
    PORT
      LAYER M4 ;
        RECT  21.516 31.056 21.6 31.08 ;
    END
  END i[305]
  PIN i[306]
    DIRECTION INPUT ;
    USE SIGNAL ;
    PORT
      LAYER M4 ;
        RECT  21.516 31.152 21.6 31.176 ;
    END
  END i[306]
  PIN i[307]
    DIRECTION INPUT ;
    USE SIGNAL ;
    PORT
      LAYER M4 ;
        RECT  21.516 31.248 21.6 31.272 ;
    END
  END i[307]
  PIN i[308]
    DIRECTION INPUT ;
    USE SIGNAL ;
    PORT
      LAYER M4 ;
        RECT  21.516 31.344 21.6 31.368 ;
    END
  END i[308]
  PIN i[309]
    DIRECTION INPUT ;
    USE SIGNAL ;
    PORT
      LAYER M4 ;
        RECT  21.516 31.44 21.6 31.464 ;
    END
  END i[309]
  PIN i[30]
    DIRECTION INPUT ;
    USE SIGNAL ;
    PORT
      LAYER M4 ;
        RECT  21.516 3.648 21.6 3.672 ;
    END
  END i[30]
  PIN i[310]
    DIRECTION INPUT ;
    USE SIGNAL ;
    PORT
      LAYER M4 ;
        RECT  21.516 31.536 21.6 31.56 ;
    END
  END i[310]
  PIN i[311]
    DIRECTION INPUT ;
    USE SIGNAL ;
    PORT
      LAYER M4 ;
        RECT  21.516 31.632 21.6 31.656 ;
    END
  END i[311]
  PIN i[312]
    DIRECTION INPUT ;
    USE SIGNAL ;
    PORT
      LAYER M4 ;
        RECT  21.516 31.728 21.6 31.752 ;
    END
  END i[312]
  PIN i[313]
    DIRECTION INPUT ;
    USE SIGNAL ;
    PORT
      LAYER M4 ;
        RECT  21.516 31.824 21.6 31.848 ;
    END
  END i[313]
  PIN i[314]
    DIRECTION INPUT ;
    USE SIGNAL ;
    PORT
      LAYER M4 ;
        RECT  21.516 31.92 21.6 31.944 ;
    END
  END i[314]
  PIN i[315]
    DIRECTION INPUT ;
    USE SIGNAL ;
    PORT
      LAYER M4 ;
        RECT  21.516 32.016 21.6 32.04 ;
    END
  END i[315]
  PIN i[316]
    DIRECTION INPUT ;
    USE SIGNAL ;
    PORT
      LAYER M4 ;
        RECT  21.516 32.16 21.6 32.184 ;
    END
  END i[316]
  PIN i[317]
    DIRECTION INPUT ;
    USE SIGNAL ;
    PORT
      LAYER M4 ;
        RECT  21.516 32.256 21.6 32.28 ;
    END
  END i[317]
  PIN i[318]
    DIRECTION INPUT ;
    USE SIGNAL ;
    PORT
      LAYER M4 ;
        RECT  21.516 32.352 21.6 32.376 ;
    END
  END i[318]
  PIN i[319]
    DIRECTION INPUT ;
    USE SIGNAL ;
    PORT
      LAYER M4 ;
        RECT  21.516 32.448 21.6 32.472 ;
    END
  END i[319]
  PIN i[31]
    DIRECTION INPUT ;
    USE SIGNAL ;
    PORT
      LAYER M4 ;
        RECT  21.516 3.744 21.6 3.768 ;
    END
  END i[31]
  PIN i[320]
    DIRECTION INPUT ;
    USE SIGNAL ;
    PORT
      LAYER M4 ;
        RECT  21.516 32.544 21.6 32.568 ;
    END
  END i[320]
  PIN i[321]
    DIRECTION INPUT ;
    USE SIGNAL ;
    PORT
      LAYER M4 ;
        RECT  21.516 32.64 21.6 32.664 ;
    END
  END i[321]
  PIN i[322]
    DIRECTION INPUT ;
    USE SIGNAL ;
    PORT
      LAYER M4 ;
        RECT  21.516 32.736 21.6 32.76 ;
    END
  END i[322]
  PIN i[323]
    DIRECTION INPUT ;
    USE SIGNAL ;
    PORT
      LAYER M4 ;
        RECT  21.516 32.832 21.6 32.856 ;
    END
  END i[323]
  PIN i[324]
    DIRECTION INPUT ;
    USE SIGNAL ;
    PORT
      LAYER M4 ;
        RECT  21.516 32.928 21.6 32.952 ;
    END
  END i[324]
  PIN i[325]
    DIRECTION INPUT ;
    USE SIGNAL ;
    PORT
      LAYER M4 ;
        RECT  21.516 33.024 21.6 33.048 ;
    END
  END i[325]
  PIN i[326]
    DIRECTION INPUT ;
    USE SIGNAL ;
    PORT
      LAYER M4 ;
        RECT  21.516 33.12 21.6 33.144 ;
    END
  END i[326]
  PIN i[327]
    DIRECTION INPUT ;
    USE SIGNAL ;
    PORT
      LAYER M4 ;
        RECT  21.516 33.216 21.6 33.24 ;
    END
  END i[327]
  PIN i[328]
    DIRECTION INPUT ;
    USE SIGNAL ;
    PORT
      LAYER M4 ;
        RECT  21.516 33.312 21.6 33.336 ;
    END
  END i[328]
  PIN i[329]
    DIRECTION INPUT ;
    USE SIGNAL ;
    PORT
      LAYER M4 ;
        RECT  21.516 33.456 21.6 33.48 ;
    END
  END i[329]
  PIN i[32]
    DIRECTION INPUT ;
    USE SIGNAL ;
    PORT
      LAYER M4 ;
        RECT  21.516 3.84 21.6 3.864 ;
    END
  END i[32]
  PIN i[330]
    DIRECTION INPUT ;
    USE SIGNAL ;
    PORT
      LAYER M4 ;
        RECT  21.516 33.552 21.6 33.576 ;
    END
  END i[330]
  PIN i[331]
    DIRECTION INPUT ;
    USE SIGNAL ;
    PORT
      LAYER M4 ;
        RECT  21.516 33.648 21.6 33.672 ;
    END
  END i[331]
  PIN i[332]
    DIRECTION INPUT ;
    USE SIGNAL ;
    PORT
      LAYER M4 ;
        RECT  21.516 33.744 21.6 33.768 ;
    END
  END i[332]
  PIN i[333]
    DIRECTION INPUT ;
    USE SIGNAL ;
    PORT
      LAYER M4 ;
        RECT  21.516 33.84 21.6 33.864 ;
    END
  END i[333]
  PIN i[334]
    DIRECTION INPUT ;
    USE SIGNAL ;
    PORT
      LAYER M4 ;
        RECT  21.516 33.936 21.6 33.96 ;
    END
  END i[334]
  PIN i[335]
    DIRECTION INPUT ;
    USE SIGNAL ;
    PORT
      LAYER M4 ;
        RECT  21.516 34.032 21.6 34.056 ;
    END
  END i[335]
  PIN i[336]
    DIRECTION INPUT ;
    USE SIGNAL ;
    PORT
      LAYER M4 ;
        RECT  21.516 34.128 21.6 34.152 ;
    END
  END i[336]
  PIN i[337]
    DIRECTION INPUT ;
    USE SIGNAL ;
    PORT
      LAYER M4 ;
        RECT  21.516 34.224 21.6 34.248 ;
    END
  END i[337]
  PIN i[338]
    DIRECTION INPUT ;
    USE SIGNAL ;
    PORT
      LAYER M4 ;
        RECT  21.516 34.32 21.6 34.344 ;
    END
  END i[338]
  PIN i[339]
    DIRECTION INPUT ;
    USE SIGNAL ;
    PORT
      LAYER M4 ;
        RECT  21.516 34.416 21.6 34.44 ;
    END
  END i[339]
  PIN i[33]
    DIRECTION INPUT ;
    USE SIGNAL ;
    PORT
      LAYER M4 ;
        RECT  21.516 3.936 21.6 3.96 ;
    END
  END i[33]
  PIN i[340]
    DIRECTION INPUT ;
    USE SIGNAL ;
    PORT
      LAYER M4 ;
        RECT  21.516 34.512 21.6 34.536 ;
    END
  END i[340]
  PIN i[341]
    DIRECTION INPUT ;
    USE SIGNAL ;
    PORT
      LAYER M4 ;
        RECT  21.516 34.608 21.6 34.632 ;
    END
  END i[341]
  PIN i[342]
    DIRECTION INPUT ;
    USE SIGNAL ;
    PORT
      LAYER M4 ;
        RECT  21.516 34.752 21.6 34.776 ;
    END
  END i[342]
  PIN i[343]
    DIRECTION INPUT ;
    USE SIGNAL ;
    PORT
      LAYER M4 ;
        RECT  21.516 34.848 21.6 34.872 ;
    END
  END i[343]
  PIN i[344]
    DIRECTION INPUT ;
    USE SIGNAL ;
    PORT
      LAYER M4 ;
        RECT  21.516 34.944 21.6 34.968 ;
    END
  END i[344]
  PIN i[345]
    DIRECTION INPUT ;
    USE SIGNAL ;
    PORT
      LAYER M4 ;
        RECT  21.516 35.04 21.6 35.064 ;
    END
  END i[345]
  PIN i[346]
    DIRECTION INPUT ;
    USE SIGNAL ;
    PORT
      LAYER M4 ;
        RECT  21.516 35.136 21.6 35.16 ;
    END
  END i[346]
  PIN i[347]
    DIRECTION INPUT ;
    USE SIGNAL ;
    PORT
      LAYER M4 ;
        RECT  21.516 35.232 21.6 35.256 ;
    END
  END i[347]
  PIN i[348]
    DIRECTION INPUT ;
    USE SIGNAL ;
    PORT
      LAYER M4 ;
        RECT  21.516 35.328 21.6 35.352 ;
    END
  END i[348]
  PIN i[349]
    DIRECTION INPUT ;
    USE SIGNAL ;
    PORT
      LAYER M4 ;
        RECT  21.516 35.424 21.6 35.448 ;
    END
  END i[349]
  PIN i[34]
    DIRECTION INPUT ;
    USE SIGNAL ;
    PORT
      LAYER M4 ;
        RECT  21.516 4.032 21.6 4.056 ;
    END
  END i[34]
  PIN i[350]
    DIRECTION INPUT ;
    USE SIGNAL ;
    PORT
      LAYER M4 ;
        RECT  21.516 35.52 21.6 35.544 ;
    END
  END i[350]
  PIN i[351]
    DIRECTION INPUT ;
    USE SIGNAL ;
    PORT
      LAYER M4 ;
        RECT  21.516 35.616 21.6 35.64 ;
    END
  END i[351]
  PIN i[352]
    DIRECTION INPUT ;
    USE SIGNAL ;
    PORT
      LAYER M4 ;
        RECT  21.516 35.712 21.6 35.736 ;
    END
  END i[352]
  PIN i[353]
    DIRECTION INPUT ;
    USE SIGNAL ;
    PORT
      LAYER M4 ;
        RECT  21.516 35.808 21.6 35.832 ;
    END
  END i[353]
  PIN i[354]
    DIRECTION INPUT ;
    USE SIGNAL ;
    PORT
      LAYER M4 ;
        RECT  21.516 35.904 21.6 35.928 ;
    END
  END i[354]
  PIN i[355]
    DIRECTION INPUT ;
    USE SIGNAL ;
    PORT
      LAYER M4 ;
        RECT  21.516 36.048 21.6 36.072 ;
    END
  END i[355]
  PIN i[356]
    DIRECTION INPUT ;
    USE SIGNAL ;
    PORT
      LAYER M4 ;
        RECT  21.516 36.144 21.6 36.168 ;
    END
  END i[356]
  PIN i[357]
    DIRECTION INPUT ;
    USE SIGNAL ;
    PORT
      LAYER M4 ;
        RECT  21.516 36.24 21.6 36.264 ;
    END
  END i[357]
  PIN i[358]
    DIRECTION INPUT ;
    USE SIGNAL ;
    PORT
      LAYER M4 ;
        RECT  21.516 36.336 21.6 36.36 ;
    END
  END i[358]
  PIN i[359]
    DIRECTION INPUT ;
    USE SIGNAL ;
    PORT
      LAYER M4 ;
        RECT  21.516 36.432 21.6 36.456 ;
    END
  END i[359]
  PIN i[35]
    DIRECTION INPUT ;
    USE SIGNAL ;
    PORT
      LAYER M4 ;
        RECT  21.516 4.128 21.6 4.152 ;
    END
  END i[35]
  PIN i[360]
    DIRECTION INPUT ;
    USE SIGNAL ;
    PORT
      LAYER M4 ;
        RECT  21.516 36.528 21.6 36.552 ;
    END
  END i[360]
  PIN i[361]
    DIRECTION INPUT ;
    USE SIGNAL ;
    PORT
      LAYER M4 ;
        RECT  21.516 36.624 21.6 36.648 ;
    END
  END i[361]
  PIN i[362]
    DIRECTION INPUT ;
    USE SIGNAL ;
    PORT
      LAYER M4 ;
        RECT  21.516 36.72 21.6 36.744 ;
    END
  END i[362]
  PIN i[363]
    DIRECTION INPUT ;
    USE SIGNAL ;
    PORT
      LAYER M4 ;
        RECT  21.516 36.816 21.6 36.84 ;
    END
  END i[363]
  PIN i[364]
    DIRECTION INPUT ;
    USE SIGNAL ;
    PORT
      LAYER M4 ;
        RECT  21.516 36.912 21.6 36.936 ;
    END
  END i[364]
  PIN i[365]
    DIRECTION INPUT ;
    USE SIGNAL ;
    PORT
      LAYER M4 ;
        RECT  21.516 37.008 21.6 37.032 ;
    END
  END i[365]
  PIN i[366]
    DIRECTION INPUT ;
    USE SIGNAL ;
    PORT
      LAYER M4 ;
        RECT  21.516 37.104 21.6 37.128 ;
    END
  END i[366]
  PIN i[367]
    DIRECTION INPUT ;
    USE SIGNAL ;
    PORT
      LAYER M4 ;
        RECT  21.516 37.2 21.6 37.224 ;
    END
  END i[367]
  PIN i[368]
    DIRECTION INPUT ;
    USE SIGNAL ;
    PORT
      LAYER M4 ;
        RECT  21.516 37.344 21.6 37.368 ;
    END
  END i[368]
  PIN i[369]
    DIRECTION INPUT ;
    USE SIGNAL ;
    PORT
      LAYER M4 ;
        RECT  21.516 37.44 21.6 37.464 ;
    END
  END i[369]
  PIN i[36]
    DIRECTION INPUT ;
    USE SIGNAL ;
    PORT
      LAYER M4 ;
        RECT  21.516 4.224 21.6 4.248 ;
    END
  END i[36]
  PIN i[370]
    DIRECTION INPUT ;
    USE SIGNAL ;
    PORT
      LAYER M4 ;
        RECT  21.516 37.536 21.6 37.56 ;
    END
  END i[370]
  PIN i[371]
    DIRECTION INPUT ;
    USE SIGNAL ;
    PORT
      LAYER M4 ;
        RECT  21.516 37.632 21.6 37.656 ;
    END
  END i[371]
  PIN i[372]
    DIRECTION INPUT ;
    USE SIGNAL ;
    PORT
      LAYER M4 ;
        RECT  21.516 37.728 21.6 37.752 ;
    END
  END i[372]
  PIN i[373]
    DIRECTION INPUT ;
    USE SIGNAL ;
    PORT
      LAYER M4 ;
        RECT  21.516 37.824 21.6 37.848 ;
    END
  END i[373]
  PIN i[374]
    DIRECTION INPUT ;
    USE SIGNAL ;
    PORT
      LAYER M4 ;
        RECT  21.516 37.92 21.6 37.944 ;
    END
  END i[374]
  PIN i[375]
    DIRECTION INPUT ;
    USE SIGNAL ;
    PORT
      LAYER M4 ;
        RECT  21.516 38.016 21.6 38.04 ;
    END
  END i[375]
  PIN i[376]
    DIRECTION INPUT ;
    USE SIGNAL ;
    PORT
      LAYER M4 ;
        RECT  21.516 38.112 21.6 38.136 ;
    END
  END i[376]
  PIN i[377]
    DIRECTION INPUT ;
    USE SIGNAL ;
    PORT
      LAYER M4 ;
        RECT  21.516 38.208 21.6 38.232 ;
    END
  END i[377]
  PIN i[378]
    DIRECTION INPUT ;
    USE SIGNAL ;
    PORT
      LAYER M4 ;
        RECT  21.516 38.304 21.6 38.328 ;
    END
  END i[378]
  PIN i[379]
    DIRECTION INPUT ;
    USE SIGNAL ;
    PORT
      LAYER M4 ;
        RECT  21.516 38.4 21.6 38.424 ;
    END
  END i[379]
  PIN i[37]
    DIRECTION INPUT ;
    USE SIGNAL ;
    PORT
      LAYER M4 ;
        RECT  21.516 4.32 21.6 4.344 ;
    END
  END i[37]
  PIN i[380]
    DIRECTION INPUT ;
    USE SIGNAL ;
    PORT
      LAYER M4 ;
        RECT  21.516 38.496 21.6 38.52 ;
    END
  END i[380]
  PIN i[381]
    DIRECTION INPUT ;
    USE SIGNAL ;
    PORT
      LAYER M4 ;
        RECT  21.516 38.64 21.6 38.664 ;
    END
  END i[381]
  PIN i[382]
    DIRECTION INPUT ;
    USE SIGNAL ;
    PORT
      LAYER M4 ;
        RECT  21.516 38.736 21.6 38.76 ;
    END
  END i[382]
  PIN i[383]
    DIRECTION INPUT ;
    USE SIGNAL ;
    PORT
      LAYER M4 ;
        RECT  21.516 38.832 21.6 38.856 ;
    END
  END i[383]
  PIN i[384]
    DIRECTION INPUT ;
    USE SIGNAL ;
    PORT
      LAYER M4 ;
        RECT  21.516 38.928 21.6 38.952 ;
    END
  END i[384]
  PIN i[385]
    DIRECTION INPUT ;
    USE SIGNAL ;
    PORT
      LAYER M4 ;
        RECT  21.516 39.024 21.6 39.048 ;
    END
  END i[385]
  PIN i[386]
    DIRECTION INPUT ;
    USE SIGNAL ;
    PORT
      LAYER M4 ;
        RECT  21.516 39.12 21.6 39.144 ;
    END
  END i[386]
  PIN i[387]
    DIRECTION INPUT ;
    USE SIGNAL ;
    PORT
      LAYER M4 ;
        RECT  21.516 39.216 21.6 39.24 ;
    END
  END i[387]
  PIN i[388]
    DIRECTION INPUT ;
    USE SIGNAL ;
    PORT
      LAYER M4 ;
        RECT  21.516 39.312 21.6 39.336 ;
    END
  END i[388]
  PIN i[389]
    DIRECTION INPUT ;
    USE SIGNAL ;
    PORT
      LAYER M4 ;
        RECT  21.516 39.408 21.6 39.432 ;
    END
  END i[389]
  PIN i[38]
    DIRECTION INPUT ;
    USE SIGNAL ;
    PORT
      LAYER M4 ;
        RECT  21.516 4.416 21.6 4.44 ;
    END
  END i[38]
  PIN i[390]
    DIRECTION INPUT ;
    USE SIGNAL ;
    PORT
      LAYER M4 ;
        RECT  21.516 39.504 21.6 39.528 ;
    END
  END i[390]
  PIN i[391]
    DIRECTION INPUT ;
    USE SIGNAL ;
    PORT
      LAYER M4 ;
        RECT  21.516 39.6 21.6 39.624 ;
    END
  END i[391]
  PIN i[392]
    DIRECTION INPUT ;
    USE SIGNAL ;
    PORT
      LAYER M4 ;
        RECT  21.516 39.696 21.6 39.72 ;
    END
  END i[392]
  PIN i[393]
    DIRECTION INPUT ;
    USE SIGNAL ;
    PORT
      LAYER M4 ;
        RECT  21.516 39.792 21.6 39.816 ;
    END
  END i[393]
  PIN i[394]
    DIRECTION INPUT ;
    USE SIGNAL ;
    PORT
      LAYER M4 ;
        RECT  21.516 39.936 21.6 39.96 ;
    END
  END i[394]
  PIN i[395]
    DIRECTION INPUT ;
    USE SIGNAL ;
    PORT
      LAYER M4 ;
        RECT  21.516 40.032 21.6 40.056 ;
    END
  END i[395]
  PIN i[396]
    DIRECTION INPUT ;
    USE SIGNAL ;
    PORT
      LAYER M4 ;
        RECT  21.516 40.128 21.6 40.152 ;
    END
  END i[396]
  PIN i[397]
    DIRECTION INPUT ;
    USE SIGNAL ;
    PORT
      LAYER M4 ;
        RECT  21.516 40.224 21.6 40.248 ;
    END
  END i[397]
  PIN i[398]
    DIRECTION INPUT ;
    USE SIGNAL ;
    PORT
      LAYER M4 ;
        RECT  21.516 40.32 21.6 40.344 ;
    END
  END i[398]
  PIN i[399]
    DIRECTION INPUT ;
    USE SIGNAL ;
    PORT
      LAYER M4 ;
        RECT  21.516 40.416 21.6 40.44 ;
    END
  END i[399]
  PIN i[39]
    DIRECTION INPUT ;
    USE SIGNAL ;
    PORT
      LAYER M4 ;
        RECT  21.516 4.512 21.6 4.536 ;
    END
  END i[39]
  PIN i[3]
    DIRECTION INPUT ;
    USE SIGNAL ;
    PORT
      LAYER M4 ;
        RECT  21.516 0.96 21.6 0.984 ;
    END
  END i[3]
  PIN i[400]
    DIRECTION INPUT ;
    USE SIGNAL ;
    PORT
      LAYER M4 ;
        RECT  21.516 40.512 21.6 40.536 ;
    END
  END i[400]
  PIN i[401]
    DIRECTION INPUT ;
    USE SIGNAL ;
    PORT
      LAYER M4 ;
        RECT  21.516 40.608 21.6 40.632 ;
    END
  END i[401]
  PIN i[402]
    DIRECTION INPUT ;
    USE SIGNAL ;
    PORT
      LAYER M4 ;
        RECT  21.516 40.704 21.6 40.728 ;
    END
  END i[402]
  PIN i[403]
    DIRECTION INPUT ;
    USE SIGNAL ;
    PORT
      LAYER M4 ;
        RECT  21.516 40.8 21.6 40.824 ;
    END
  END i[403]
  PIN i[404]
    DIRECTION INPUT ;
    USE SIGNAL ;
    PORT
      LAYER M4 ;
        RECT  21.516 40.896 21.6 40.92 ;
    END
  END i[404]
  PIN i[405]
    DIRECTION INPUT ;
    USE SIGNAL ;
    PORT
      LAYER M4 ;
        RECT  21.516 40.992 21.6 41.016 ;
    END
  END i[405]
  PIN i[406]
    DIRECTION INPUT ;
    USE SIGNAL ;
    PORT
      LAYER M4 ;
        RECT  21.516 41.088 21.6 41.112 ;
    END
  END i[406]
  PIN i[407]
    DIRECTION INPUT ;
    USE SIGNAL ;
    PORT
      LAYER M4 ;
        RECT  21.516 41.184 21.6 41.208 ;
    END
  END i[407]
  PIN i[408]
    DIRECTION INPUT ;
    USE SIGNAL ;
    PORT
      LAYER M4 ;
        RECT  21.516 41.328 21.6 41.352 ;
    END
  END i[408]
  PIN i[409]
    DIRECTION INPUT ;
    USE SIGNAL ;
    PORT
      LAYER M4 ;
        RECT  21.516 41.424 21.6 41.448 ;
    END
  END i[409]
  PIN i[40]
    DIRECTION INPUT ;
    USE SIGNAL ;
    PORT
      LAYER M4 ;
        RECT  21.516 4.608 21.6 4.632 ;
    END
  END i[40]
  PIN i[410]
    DIRECTION INPUT ;
    USE SIGNAL ;
    PORT
      LAYER M4 ;
        RECT  21.516 41.52 21.6 41.544 ;
    END
  END i[410]
  PIN i[411]
    DIRECTION INPUT ;
    USE SIGNAL ;
    PORT
      LAYER M4 ;
        RECT  21.516 41.616 21.6 41.64 ;
    END
  END i[411]
  PIN i[412]
    DIRECTION INPUT ;
    USE SIGNAL ;
    PORT
      LAYER M4 ;
        RECT  21.516 41.712 21.6 41.736 ;
    END
  END i[412]
  PIN i[413]
    DIRECTION INPUT ;
    USE SIGNAL ;
    PORT
      LAYER M4 ;
        RECT  21.516 41.808 21.6 41.832 ;
    END
  END i[413]
  PIN i[414]
    DIRECTION INPUT ;
    USE SIGNAL ;
    PORT
      LAYER M4 ;
        RECT  21.516 41.904 21.6 41.928 ;
    END
  END i[414]
  PIN i[415]
    DIRECTION INPUT ;
    USE SIGNAL ;
    PORT
      LAYER M4 ;
        RECT  21.516 42 21.6 42.024 ;
    END
  END i[415]
  PIN i[416]
    DIRECTION INPUT ;
    USE SIGNAL ;
    PORT
      LAYER M4 ;
        RECT  21.516 42.096 21.6 42.12 ;
    END
  END i[416]
  PIN i[417]
    DIRECTION INPUT ;
    USE SIGNAL ;
    PORT
      LAYER M4 ;
        RECT  21.516 42.192 21.6 42.216 ;
    END
  END i[417]
  PIN i[418]
    DIRECTION INPUT ;
    USE SIGNAL ;
    PORT
      LAYER M4 ;
        RECT  21.516 42.288 21.6 42.312 ;
    END
  END i[418]
  PIN i[419]
    DIRECTION INPUT ;
    USE SIGNAL ;
    PORT
      LAYER M4 ;
        RECT  21.516 42.384 21.6 42.408 ;
    END
  END i[419]
  PIN i[41]
    DIRECTION INPUT ;
    USE SIGNAL ;
    PORT
      LAYER M4 ;
        RECT  21.516 4.704 21.6 4.728 ;
    END
  END i[41]
  PIN i[420]
    DIRECTION INPUT ;
    USE SIGNAL ;
    PORT
      LAYER M4 ;
        RECT  21.516 42.48 21.6 42.504 ;
    END
  END i[420]
  PIN i[421]
    DIRECTION INPUT ;
    USE SIGNAL ;
    PORT
      LAYER M4 ;
        RECT  21.516 42.624 21.6 42.648 ;
    END
  END i[421]
  PIN i[422]
    DIRECTION INPUT ;
    USE SIGNAL ;
    PORT
      LAYER M4 ;
        RECT  21.516 42.72 21.6 42.744 ;
    END
  END i[422]
  PIN i[423]
    DIRECTION INPUT ;
    USE SIGNAL ;
    PORT
      LAYER M4 ;
        RECT  21.516 42.816 21.6 42.84 ;
    END
  END i[423]
  PIN i[424]
    DIRECTION INPUT ;
    USE SIGNAL ;
    PORT
      LAYER M4 ;
        RECT  21.516 42.912 21.6 42.936 ;
    END
  END i[424]
  PIN i[425]
    DIRECTION INPUT ;
    USE SIGNAL ;
    PORT
      LAYER M4 ;
        RECT  21.516 43.008 21.6 43.032 ;
    END
  END i[425]
  PIN i[426]
    DIRECTION INPUT ;
    USE SIGNAL ;
    PORT
      LAYER M4 ;
        RECT  21.516 43.104 21.6 43.128 ;
    END
  END i[426]
  PIN i[427]
    DIRECTION INPUT ;
    USE SIGNAL ;
    PORT
      LAYER M4 ;
        RECT  21.516 43.2 21.6 43.224 ;
    END
  END i[427]
  PIN i[428]
    DIRECTION INPUT ;
    USE SIGNAL ;
    PORT
      LAYER M4 ;
        RECT  21.516 43.296 21.6 43.32 ;
    END
  END i[428]
  PIN i[429]
    DIRECTION INPUT ;
    USE SIGNAL ;
    PORT
      LAYER M4 ;
        RECT  21.516 43.392 21.6 43.416 ;
    END
  END i[429]
  PIN i[42]
    DIRECTION INPUT ;
    USE SIGNAL ;
    PORT
      LAYER M4 ;
        RECT  21.516 4.848 21.6 4.872 ;
    END
  END i[42]
  PIN i[430]
    DIRECTION INPUT ;
    USE SIGNAL ;
    PORT
      LAYER M4 ;
        RECT  21.516 43.488 21.6 43.512 ;
    END
  END i[430]
  PIN i[431]
    DIRECTION INPUT ;
    USE SIGNAL ;
    PORT
      LAYER M4 ;
        RECT  21.516 43.584 21.6 43.608 ;
    END
  END i[431]
  PIN i[432]
    DIRECTION INPUT ;
    USE SIGNAL ;
    PORT
      LAYER M4 ;
        RECT  21.516 43.68 21.6 43.704 ;
    END
  END i[432]
  PIN i[433]
    DIRECTION INPUT ;
    USE SIGNAL ;
    PORT
      LAYER M4 ;
        RECT  21.516 43.776 21.6 43.8 ;
    END
  END i[433]
  PIN i[434]
    DIRECTION INPUT ;
    USE SIGNAL ;
    PORT
      LAYER M4 ;
        RECT  21.516 43.92 21.6 43.944 ;
    END
  END i[434]
  PIN i[435]
    DIRECTION INPUT ;
    USE SIGNAL ;
    PORT
      LAYER M4 ;
        RECT  21.516 44.016 21.6 44.04 ;
    END
  END i[435]
  PIN i[436]
    DIRECTION INPUT ;
    USE SIGNAL ;
    PORT
      LAYER M4 ;
        RECT  21.516 44.112 21.6 44.136 ;
    END
  END i[436]
  PIN i[437]
    DIRECTION INPUT ;
    USE SIGNAL ;
    PORT
      LAYER M4 ;
        RECT  21.516 44.208 21.6 44.232 ;
    END
  END i[437]
  PIN i[438]
    DIRECTION INPUT ;
    USE SIGNAL ;
    PORT
      LAYER M4 ;
        RECT  21.516 44.304 21.6 44.328 ;
    END
  END i[438]
  PIN i[439]
    DIRECTION INPUT ;
    USE SIGNAL ;
    PORT
      LAYER M4 ;
        RECT  21.516 44.4 21.6 44.424 ;
    END
  END i[439]
  PIN i[43]
    DIRECTION INPUT ;
    USE SIGNAL ;
    PORT
      LAYER M4 ;
        RECT  21.516 4.944 21.6 4.968 ;
    END
  END i[43]
  PIN i[440]
    DIRECTION INPUT ;
    USE SIGNAL ;
    PORT
      LAYER M4 ;
        RECT  21.516 44.496 21.6 44.52 ;
    END
  END i[440]
  PIN i[441]
    DIRECTION INPUT ;
    USE SIGNAL ;
    PORT
      LAYER M4 ;
        RECT  21.516 44.592 21.6 44.616 ;
    END
  END i[441]
  PIN i[442]
    DIRECTION INPUT ;
    USE SIGNAL ;
    PORT
      LAYER M4 ;
        RECT  21.516 44.688 21.6 44.712 ;
    END
  END i[442]
  PIN i[443]
    DIRECTION INPUT ;
    USE SIGNAL ;
    PORT
      LAYER M4 ;
        RECT  21.516 44.784 21.6 44.808 ;
    END
  END i[443]
  PIN i[444]
    DIRECTION INPUT ;
    USE SIGNAL ;
    PORT
      LAYER M4 ;
        RECT  21.516 44.88 21.6 44.904 ;
    END
  END i[444]
  PIN i[445]
    DIRECTION INPUT ;
    USE SIGNAL ;
    PORT
      LAYER M4 ;
        RECT  21.516 44.976 21.6 45 ;
    END
  END i[445]
  PIN i[446]
    DIRECTION INPUT ;
    USE SIGNAL ;
    PORT
      LAYER M4 ;
        RECT  21.516 45.072 21.6 45.096 ;
    END
  END i[446]
  PIN i[447]
    DIRECTION INPUT ;
    USE SIGNAL ;
    PORT
      LAYER M4 ;
        RECT  21.516 45.216 21.6 45.24 ;
    END
  END i[447]
  PIN i[448]
    DIRECTION INPUT ;
    USE SIGNAL ;
    PORT
      LAYER M4 ;
        RECT  21.516 45.312 21.6 45.336 ;
    END
  END i[448]
  PIN i[449]
    DIRECTION INPUT ;
    USE SIGNAL ;
    PORT
      LAYER M4 ;
        RECT  21.516 45.408 21.6 45.432 ;
    END
  END i[449]
  PIN i[44]
    DIRECTION INPUT ;
    USE SIGNAL ;
    PORT
      LAYER M4 ;
        RECT  21.516 5.04 21.6 5.064 ;
    END
  END i[44]
  PIN i[450]
    DIRECTION INPUT ;
    USE SIGNAL ;
    PORT
      LAYER M4 ;
        RECT  21.516 45.504 21.6 45.528 ;
    END
  END i[450]
  PIN i[451]
    DIRECTION INPUT ;
    USE SIGNAL ;
    PORT
      LAYER M4 ;
        RECT  21.516 45.6 21.6 45.624 ;
    END
  END i[451]
  PIN i[452]
    DIRECTION INPUT ;
    USE SIGNAL ;
    PORT
      LAYER M4 ;
        RECT  21.516 45.696 21.6 45.72 ;
    END
  END i[452]
  PIN i[453]
    DIRECTION INPUT ;
    USE SIGNAL ;
    PORT
      LAYER M4 ;
        RECT  21.516 45.792 21.6 45.816 ;
    END
  END i[453]
  PIN i[454]
    DIRECTION INPUT ;
    USE SIGNAL ;
    PORT
      LAYER M4 ;
        RECT  21.516 45.888 21.6 45.912 ;
    END
  END i[454]
  PIN i[455]
    DIRECTION INPUT ;
    USE SIGNAL ;
    PORT
      LAYER M4 ;
        RECT  21.516 45.984 21.6 46.008 ;
    END
  END i[455]
  PIN i[456]
    DIRECTION INPUT ;
    USE SIGNAL ;
    PORT
      LAYER M4 ;
        RECT  21.516 46.08 21.6 46.104 ;
    END
  END i[456]
  PIN i[457]
    DIRECTION INPUT ;
    USE SIGNAL ;
    PORT
      LAYER M4 ;
        RECT  21.516 46.176 21.6 46.2 ;
    END
  END i[457]
  PIN i[458]
    DIRECTION INPUT ;
    USE SIGNAL ;
    PORT
      LAYER M4 ;
        RECT  21.516 46.272 21.6 46.296 ;
    END
  END i[458]
  PIN i[459]
    DIRECTION INPUT ;
    USE SIGNAL ;
    PORT
      LAYER M4 ;
        RECT  21.516 46.368 21.6 46.392 ;
    END
  END i[459]
  PIN i[45]
    DIRECTION INPUT ;
    USE SIGNAL ;
    PORT
      LAYER M4 ;
        RECT  21.516 5.136 21.6 5.16 ;
    END
  END i[45]
  PIN i[460]
    DIRECTION INPUT ;
    USE SIGNAL ;
    PORT
      LAYER M4 ;
        RECT  21.516 46.512 21.6 46.536 ;
    END
  END i[460]
  PIN i[461]
    DIRECTION INPUT ;
    USE SIGNAL ;
    PORT
      LAYER M4 ;
        RECT  21.516 46.608 21.6 46.632 ;
    END
  END i[461]
  PIN i[462]
    DIRECTION INPUT ;
    USE SIGNAL ;
    PORT
      LAYER M4 ;
        RECT  21.516 46.704 21.6 46.728 ;
    END
  END i[462]
  PIN i[463]
    DIRECTION INPUT ;
    USE SIGNAL ;
    PORT
      LAYER M4 ;
        RECT  21.516 46.8 21.6 46.824 ;
    END
  END i[463]
  PIN i[464]
    DIRECTION INPUT ;
    USE SIGNAL ;
    PORT
      LAYER M4 ;
        RECT  21.516 46.896 21.6 46.92 ;
    END
  END i[464]
  PIN i[465]
    DIRECTION INPUT ;
    USE SIGNAL ;
    PORT
      LAYER M4 ;
        RECT  21.516 46.992 21.6 47.016 ;
    END
  END i[465]
  PIN i[466]
    DIRECTION INPUT ;
    USE SIGNAL ;
    PORT
      LAYER M4 ;
        RECT  21.516 47.088 21.6 47.112 ;
    END
  END i[466]
  PIN i[467]
    DIRECTION INPUT ;
    USE SIGNAL ;
    PORT
      LAYER M4 ;
        RECT  21.516 47.184 21.6 47.208 ;
    END
  END i[467]
  PIN i[468]
    DIRECTION INPUT ;
    USE SIGNAL ;
    PORT
      LAYER M4 ;
        RECT  21.516 47.28 21.6 47.304 ;
    END
  END i[468]
  PIN i[469]
    DIRECTION INPUT ;
    USE SIGNAL ;
    PORT
      LAYER M4 ;
        RECT  21.516 47.376 21.6 47.4 ;
    END
  END i[469]
  PIN i[46]
    DIRECTION INPUT ;
    USE SIGNAL ;
    PORT
      LAYER M4 ;
        RECT  21.516 5.232 21.6 5.256 ;
    END
  END i[46]
  PIN i[470]
    DIRECTION INPUT ;
    USE SIGNAL ;
    PORT
      LAYER M4 ;
        RECT  21.516 47.472 21.6 47.496 ;
    END
  END i[470]
  PIN i[471]
    DIRECTION INPUT ;
    USE SIGNAL ;
    PORT
      LAYER M4 ;
        RECT  21.516 47.568 21.6 47.592 ;
    END
  END i[471]
  PIN i[472]
    DIRECTION INPUT ;
    USE SIGNAL ;
    PORT
      LAYER M4 ;
        RECT  21.516 47.664 21.6 47.688 ;
    END
  END i[472]
  PIN i[473]
    DIRECTION INPUT ;
    USE SIGNAL ;
    PORT
      LAYER M4 ;
        RECT  21.516 47.808 21.6 47.832 ;
    END
  END i[473]
  PIN i[474]
    DIRECTION INPUT ;
    USE SIGNAL ;
    PORT
      LAYER M4 ;
        RECT  21.516 47.904 21.6 47.928 ;
    END
  END i[474]
  PIN i[475]
    DIRECTION INPUT ;
    USE SIGNAL ;
    PORT
      LAYER M4 ;
        RECT  21.516 48 21.6 48.024 ;
    END
  END i[475]
  PIN i[476]
    DIRECTION INPUT ;
    USE SIGNAL ;
    PORT
      LAYER M4 ;
        RECT  21.516 48.096 21.6 48.12 ;
    END
  END i[476]
  PIN i[477]
    DIRECTION INPUT ;
    USE SIGNAL ;
    PORT
      LAYER M4 ;
        RECT  21.516 48.192 21.6 48.216 ;
    END
  END i[477]
  PIN i[478]
    DIRECTION INPUT ;
    USE SIGNAL ;
    PORT
      LAYER M4 ;
        RECT  21.516 48.288 21.6 48.312 ;
    END
  END i[478]
  PIN i[479]
    DIRECTION INPUT ;
    USE SIGNAL ;
    PORT
      LAYER M4 ;
        RECT  21.516 48.384 21.6 48.408 ;
    END
  END i[479]
  PIN i[47]
    DIRECTION INPUT ;
    USE SIGNAL ;
    PORT
      LAYER M4 ;
        RECT  21.516 5.328 21.6 5.352 ;
    END
  END i[47]
  PIN i[480]
    DIRECTION INPUT ;
    USE SIGNAL ;
    PORT
      LAYER M4 ;
        RECT  21.516 48.48 21.6 48.504 ;
    END
  END i[480]
  PIN i[481]
    DIRECTION INPUT ;
    USE SIGNAL ;
    PORT
      LAYER M4 ;
        RECT  21.516 48.576 21.6 48.6 ;
    END
  END i[481]
  PIN i[482]
    DIRECTION INPUT ;
    USE SIGNAL ;
    PORT
      LAYER M4 ;
        RECT  21.516 48.672 21.6 48.696 ;
    END
  END i[482]
  PIN i[483]
    DIRECTION INPUT ;
    USE SIGNAL ;
    PORT
      LAYER M4 ;
        RECT  21.516 48.768 21.6 48.792 ;
    END
  END i[483]
  PIN i[484]
    DIRECTION INPUT ;
    USE SIGNAL ;
    PORT
      LAYER M4 ;
        RECT  21.516 48.864 21.6 48.888 ;
    END
  END i[484]
  PIN i[485]
    DIRECTION INPUT ;
    USE SIGNAL ;
    PORT
      LAYER M4 ;
        RECT  21.516 48.96 21.6 48.984 ;
    END
  END i[485]
  PIN i[486]
    DIRECTION INPUT ;
    USE SIGNAL ;
    PORT
      LAYER M4 ;
        RECT  21.516 49.104 21.6 49.128 ;
    END
  END i[486]
  PIN i[487]
    DIRECTION INPUT ;
    USE SIGNAL ;
    PORT
      LAYER M4 ;
        RECT  21.516 49.2 21.6 49.224 ;
    END
  END i[487]
  PIN i[488]
    DIRECTION INPUT ;
    USE SIGNAL ;
    PORT
      LAYER M4 ;
        RECT  21.516 49.296 21.6 49.32 ;
    END
  END i[488]
  PIN i[489]
    DIRECTION INPUT ;
    USE SIGNAL ;
    PORT
      LAYER M4 ;
        RECT  21.516 49.392 21.6 49.416 ;
    END
  END i[489]
  PIN i[48]
    DIRECTION INPUT ;
    USE SIGNAL ;
    PORT
      LAYER M4 ;
        RECT  21.516 5.424 21.6 5.448 ;
    END
  END i[48]
  PIN i[490]
    DIRECTION INPUT ;
    USE SIGNAL ;
    PORT
      LAYER M4 ;
        RECT  21.516 49.488 21.6 49.512 ;
    END
  END i[490]
  PIN i[491]
    DIRECTION INPUT ;
    USE SIGNAL ;
    PORT
      LAYER M4 ;
        RECT  21.516 49.584 21.6 49.608 ;
    END
  END i[491]
  PIN i[492]
    DIRECTION INPUT ;
    USE SIGNAL ;
    PORT
      LAYER M4 ;
        RECT  21.516 49.68 21.6 49.704 ;
    END
  END i[492]
  PIN i[493]
    DIRECTION INPUT ;
    USE SIGNAL ;
    PORT
      LAYER M4 ;
        RECT  21.516 49.776 21.6 49.8 ;
    END
  END i[493]
  PIN i[494]
    DIRECTION INPUT ;
    USE SIGNAL ;
    PORT
      LAYER M4 ;
        RECT  21.516 49.872 21.6 49.896 ;
    END
  END i[494]
  PIN i[495]
    DIRECTION INPUT ;
    USE SIGNAL ;
    PORT
      LAYER M4 ;
        RECT  21.516 49.968 21.6 49.992 ;
    END
  END i[495]
  PIN i[496]
    DIRECTION INPUT ;
    USE SIGNAL ;
    PORT
      LAYER M4 ;
        RECT  21.516 50.064 21.6 50.088 ;
    END
  END i[496]
  PIN i[497]
    DIRECTION INPUT ;
    USE SIGNAL ;
    PORT
      LAYER M4 ;
        RECT  21.516 50.16 21.6 50.184 ;
    END
  END i[497]
  PIN i[498]
    DIRECTION INPUT ;
    USE SIGNAL ;
    PORT
      LAYER M4 ;
        RECT  21.516 50.256 21.6 50.28 ;
    END
  END i[498]
  PIN i[499]
    DIRECTION INPUT ;
    USE SIGNAL ;
    PORT
      LAYER M4 ;
        RECT  21.516 50.4 21.6 50.424 ;
    END
  END i[499]
  PIN i[49]
    DIRECTION INPUT ;
    USE SIGNAL ;
    PORT
      LAYER M4 ;
        RECT  21.516 5.52 21.6 5.544 ;
    END
  END i[49]
  PIN i[4]
    DIRECTION INPUT ;
    USE SIGNAL ;
    PORT
      LAYER M4 ;
        RECT  21.516 1.056 21.6 1.08 ;
    END
  END i[4]
  PIN i[500]
    DIRECTION INPUT ;
    USE SIGNAL ;
    PORT
      LAYER M4 ;
        RECT  21.516 50.496 21.6 50.52 ;
    END
  END i[500]
  PIN i[501]
    DIRECTION INPUT ;
    USE SIGNAL ;
    PORT
      LAYER M4 ;
        RECT  21.516 50.592 21.6 50.616 ;
    END
  END i[501]
  PIN i[502]
    DIRECTION INPUT ;
    USE SIGNAL ;
    PORT
      LAYER M4 ;
        RECT  21.516 50.688 21.6 50.712 ;
    END
  END i[502]
  PIN i[503]
    DIRECTION INPUT ;
    USE SIGNAL ;
    PORT
      LAYER M4 ;
        RECT  21.516 50.784 21.6 50.808 ;
    END
  END i[503]
  PIN i[504]
    DIRECTION INPUT ;
    USE SIGNAL ;
    PORT
      LAYER M4 ;
        RECT  21.516 50.88 21.6 50.904 ;
    END
  END i[504]
  PIN i[505]
    DIRECTION INPUT ;
    USE SIGNAL ;
    PORT
      LAYER M4 ;
        RECT  21.516 50.976 21.6 51 ;
    END
  END i[505]
  PIN i[506]
    DIRECTION INPUT ;
    USE SIGNAL ;
    PORT
      LAYER M4 ;
        RECT  21.516 51.072 21.6 51.096 ;
    END
  END i[506]
  PIN i[507]
    DIRECTION INPUT ;
    USE SIGNAL ;
    PORT
      LAYER M4 ;
        RECT  21.516 51.168 21.6 51.192 ;
    END
  END i[507]
  PIN i[508]
    DIRECTION INPUT ;
    USE SIGNAL ;
    PORT
      LAYER M4 ;
        RECT  21.516 51.264 21.6 51.288 ;
    END
  END i[508]
  PIN i[509]
    DIRECTION INPUT ;
    USE SIGNAL ;
    PORT
      LAYER M4 ;
        RECT  21.516 51.36 21.6 51.384 ;
    END
  END i[509]
  PIN i[50]
    DIRECTION INPUT ;
    USE SIGNAL ;
    PORT
      LAYER M4 ;
        RECT  21.516 5.616 21.6 5.64 ;
    END
  END i[50]
  PIN i[510]
    DIRECTION INPUT ;
    USE SIGNAL ;
    PORT
      LAYER M4 ;
        RECT  21.516 51.456 21.6 51.48 ;
    END
  END i[510]
  PIN i[511]
    DIRECTION INPUT ;
    USE SIGNAL ;
    PORT
      LAYER M4 ;
        RECT  21.516 51.552 21.6 51.576 ;
    END
  END i[511]
  PIN i[512]
    DIRECTION INPUT ;
    USE SIGNAL ;
    PORT
      LAYER M4 ;
        RECT  21.516 51.696 21.6 51.72 ;
    END
  END i[512]
  PIN i[513]
    DIRECTION INPUT ;
    USE SIGNAL ;
    PORT
      LAYER M4 ;
        RECT  21.516 51.792 21.6 51.816 ;
    END
  END i[513]
  PIN i[514]
    DIRECTION INPUT ;
    USE SIGNAL ;
    PORT
      LAYER M4 ;
        RECT  21.516 51.888 21.6 51.912 ;
    END
  END i[514]
  PIN i[515]
    DIRECTION INPUT ;
    USE SIGNAL ;
    PORT
      LAYER M4 ;
        RECT  21.516 51.984 21.6 52.008 ;
    END
  END i[515]
  PIN i[516]
    DIRECTION INPUT ;
    USE SIGNAL ;
    PORT
      LAYER M4 ;
        RECT  21.516 52.08 21.6 52.104 ;
    END
  END i[516]
  PIN i[517]
    DIRECTION INPUT ;
    USE SIGNAL ;
    PORT
      LAYER M4 ;
        RECT  21.516 52.176 21.6 52.2 ;
    END
  END i[517]
  PIN i[518]
    DIRECTION INPUT ;
    USE SIGNAL ;
    PORT
      LAYER M4 ;
        RECT  21.516 52.272 21.6 52.296 ;
    END
  END i[518]
  PIN i[519]
    DIRECTION INPUT ;
    USE SIGNAL ;
    PORT
      LAYER M4 ;
        RECT  21.516 52.368 21.6 52.392 ;
    END
  END i[519]
  PIN i[51]
    DIRECTION INPUT ;
    USE SIGNAL ;
    PORT
      LAYER M4 ;
        RECT  21.516 5.712 21.6 5.736 ;
    END
  END i[51]
  PIN i[520]
    DIRECTION INPUT ;
    USE SIGNAL ;
    PORT
      LAYER M4 ;
        RECT  21.516 52.464 21.6 52.488 ;
    END
  END i[520]
  PIN i[521]
    DIRECTION INPUT ;
    USE SIGNAL ;
    PORT
      LAYER M4 ;
        RECT  21.516 52.56 21.6 52.584 ;
    END
  END i[521]
  PIN i[522]
    DIRECTION INPUT ;
    USE SIGNAL ;
    PORT
      LAYER M4 ;
        RECT  21.516 52.656 21.6 52.68 ;
    END
  END i[522]
  PIN i[523]
    DIRECTION INPUT ;
    USE SIGNAL ;
    PORT
      LAYER M4 ;
        RECT  21.516 52.752 21.6 52.776 ;
    END
  END i[523]
  PIN i[524]
    DIRECTION INPUT ;
    USE SIGNAL ;
    PORT
      LAYER M4 ;
        RECT  21.516 52.848 21.6 52.872 ;
    END
  END i[524]
  PIN i[525]
    DIRECTION INPUT ;
    USE SIGNAL ;
    PORT
      LAYER M4 ;
        RECT  21.516 52.992 21.6 53.016 ;
    END
  END i[525]
  PIN i[526]
    DIRECTION INPUT ;
    USE SIGNAL ;
    PORT
      LAYER M4 ;
        RECT  21.516 53.088 21.6 53.112 ;
    END
  END i[526]
  PIN i[527]
    DIRECTION INPUT ;
    USE SIGNAL ;
    PORT
      LAYER M4 ;
        RECT  21.516 53.184 21.6 53.208 ;
    END
  END i[527]
  PIN i[528]
    DIRECTION INPUT ;
    USE SIGNAL ;
    PORT
      LAYER M4 ;
        RECT  21.516 53.28 21.6 53.304 ;
    END
  END i[528]
  PIN i[529]
    DIRECTION INPUT ;
    USE SIGNAL ;
    PORT
      LAYER M4 ;
        RECT  21.516 53.376 21.6 53.4 ;
    END
  END i[529]
  PIN i[52]
    DIRECTION INPUT ;
    USE SIGNAL ;
    PORT
      LAYER M4 ;
        RECT  21.516 5.808 21.6 5.832 ;
    END
  END i[52]
  PIN i[530]
    DIRECTION INPUT ;
    USE SIGNAL ;
    PORT
      LAYER M4 ;
        RECT  21.516 53.472 21.6 53.496 ;
    END
  END i[530]
  PIN i[531]
    DIRECTION INPUT ;
    USE SIGNAL ;
    PORT
      LAYER M4 ;
        RECT  21.516 53.568 21.6 53.592 ;
    END
  END i[531]
  PIN i[532]
    DIRECTION INPUT ;
    USE SIGNAL ;
    PORT
      LAYER M4 ;
        RECT  21.516 53.664 21.6 53.688 ;
    END
  END i[532]
  PIN i[533]
    DIRECTION INPUT ;
    USE SIGNAL ;
    PORT
      LAYER M4 ;
        RECT  21.516 53.76 21.6 53.784 ;
    END
  END i[533]
  PIN i[534]
    DIRECTION INPUT ;
    USE SIGNAL ;
    PORT
      LAYER M4 ;
        RECT  21.516 53.856 21.6 53.88 ;
    END
  END i[534]
  PIN i[535]
    DIRECTION INPUT ;
    USE SIGNAL ;
    PORT
      LAYER M4 ;
        RECT  21.516 53.952 21.6 53.976 ;
    END
  END i[535]
  PIN i[536]
    DIRECTION INPUT ;
    USE SIGNAL ;
    PORT
      LAYER M4 ;
        RECT  21.516 54.048 21.6 54.072 ;
    END
  END i[536]
  PIN i[537]
    DIRECTION INPUT ;
    USE SIGNAL ;
    PORT
      LAYER M4 ;
        RECT  21.516 54.144 21.6 54.168 ;
    END
  END i[537]
  PIN i[538]
    DIRECTION INPUT ;
    USE SIGNAL ;
    PORT
      LAYER M4 ;
        RECT  21.516 54.288 21.6 54.312 ;
    END
  END i[538]
  PIN i[539]
    DIRECTION INPUT ;
    USE SIGNAL ;
    PORT
      LAYER M4 ;
        RECT  21.516 54.384 21.6 54.408 ;
    END
  END i[539]
  PIN i[53]
    DIRECTION INPUT ;
    USE SIGNAL ;
    PORT
      LAYER M4 ;
        RECT  21.516 5.904 21.6 5.928 ;
    END
  END i[53]
  PIN i[540]
    DIRECTION INPUT ;
    USE SIGNAL ;
    PORT
      LAYER M4 ;
        RECT  21.516 54.48 21.6 54.504 ;
    END
  END i[540]
  PIN i[541]
    DIRECTION INPUT ;
    USE SIGNAL ;
    PORT
      LAYER M4 ;
        RECT  21.516 54.576 21.6 54.6 ;
    END
  END i[541]
  PIN i[542]
    DIRECTION INPUT ;
    USE SIGNAL ;
    PORT
      LAYER M4 ;
        RECT  21.516 54.672 21.6 54.696 ;
    END
  END i[542]
  PIN i[543]
    DIRECTION INPUT ;
    USE SIGNAL ;
    PORT
      LAYER M4 ;
        RECT  21.516 54.768 21.6 54.792 ;
    END
  END i[543]
  PIN i[544]
    DIRECTION INPUT ;
    USE SIGNAL ;
    PORT
      LAYER M4 ;
        RECT  21.516 54.864 21.6 54.888 ;
    END
  END i[544]
  PIN i[545]
    DIRECTION INPUT ;
    USE SIGNAL ;
    PORT
      LAYER M4 ;
        RECT  21.516 54.96 21.6 54.984 ;
    END
  END i[545]
  PIN i[546]
    DIRECTION INPUT ;
    USE SIGNAL ;
    PORT
      LAYER M4 ;
        RECT  21.516 55.056 21.6 55.08 ;
    END
  END i[546]
  PIN i[547]
    DIRECTION INPUT ;
    USE SIGNAL ;
    PORT
      LAYER M4 ;
        RECT  21.516 55.152 21.6 55.176 ;
    END
  END i[547]
  PIN i[548]
    DIRECTION INPUT ;
    USE SIGNAL ;
    PORT
      LAYER M4 ;
        RECT  21.516 55.248 21.6 55.272 ;
    END
  END i[548]
  PIN i[549]
    DIRECTION INPUT ;
    USE SIGNAL ;
    PORT
      LAYER M4 ;
        RECT  21.516 55.344 21.6 55.368 ;
    END
  END i[549]
  PIN i[54]
    DIRECTION INPUT ;
    USE SIGNAL ;
    PORT
      LAYER M4 ;
        RECT  21.516 6 21.6 6.024 ;
    END
  END i[54]
  PIN i[550]
    DIRECTION INPUT ;
    USE SIGNAL ;
    PORT
      LAYER M4 ;
        RECT  21.516 55.44 21.6 55.464 ;
    END
  END i[550]
  PIN i[551]
    DIRECTION INPUT ;
    USE SIGNAL ;
    PORT
      LAYER M4 ;
        RECT  21.516 55.584 21.6 55.608 ;
    END
  END i[551]
  PIN i[552]
    DIRECTION INPUT ;
    USE SIGNAL ;
    PORT
      LAYER M4 ;
        RECT  21.516 55.68 21.6 55.704 ;
    END
  END i[552]
  PIN i[553]
    DIRECTION INPUT ;
    USE SIGNAL ;
    PORT
      LAYER M4 ;
        RECT  21.516 55.776 21.6 55.8 ;
    END
  END i[553]
  PIN i[554]
    DIRECTION INPUT ;
    USE SIGNAL ;
    PORT
      LAYER M4 ;
        RECT  21.516 55.872 21.6 55.896 ;
    END
  END i[554]
  PIN i[555]
    DIRECTION INPUT ;
    USE SIGNAL ;
    PORT
      LAYER M4 ;
        RECT  21.516 55.968 21.6 55.992 ;
    END
  END i[555]
  PIN i[556]
    DIRECTION INPUT ;
    USE SIGNAL ;
    PORT
      LAYER M4 ;
        RECT  21.516 56.064 21.6 56.088 ;
    END
  END i[556]
  PIN i[557]
    DIRECTION INPUT ;
    USE SIGNAL ;
    PORT
      LAYER M4 ;
        RECT  21.516 56.16 21.6 56.184 ;
    END
  END i[557]
  PIN i[558]
    DIRECTION INPUT ;
    USE SIGNAL ;
    PORT
      LAYER M4 ;
        RECT  21.516 56.256 21.6 56.28 ;
    END
  END i[558]
  PIN i[559]
    DIRECTION INPUT ;
    USE SIGNAL ;
    PORT
      LAYER M4 ;
        RECT  21.516 56.352 21.6 56.376 ;
    END
  END i[559]
  PIN i[55]
    DIRECTION INPUT ;
    USE SIGNAL ;
    PORT
      LAYER M4 ;
        RECT  21.516 6.144 21.6 6.168 ;
    END
  END i[55]
  PIN i[560]
    DIRECTION INPUT ;
    USE SIGNAL ;
    PORT
      LAYER M4 ;
        RECT  21.516 56.448 21.6 56.472 ;
    END
  END i[560]
  PIN i[561]
    DIRECTION INPUT ;
    USE SIGNAL ;
    PORT
      LAYER M4 ;
        RECT  21.516 56.544 21.6 56.568 ;
    END
  END i[561]
  PIN i[562]
    DIRECTION INPUT ;
    USE SIGNAL ;
    PORT
      LAYER M4 ;
        RECT  21.516 56.64 21.6 56.664 ;
    END
  END i[562]
  PIN i[563]
    DIRECTION INPUT ;
    USE SIGNAL ;
    PORT
      LAYER M4 ;
        RECT  21.516 56.736 21.6 56.76 ;
    END
  END i[563]
  PIN i[564]
    DIRECTION INPUT ;
    USE SIGNAL ;
    PORT
      LAYER M4 ;
        RECT  21.516 56.88 21.6 56.904 ;
    END
  END i[564]
  PIN i[565]
    DIRECTION INPUT ;
    USE SIGNAL ;
    PORT
      LAYER M4 ;
        RECT  21.516 56.976 21.6 57 ;
    END
  END i[565]
  PIN i[566]
    DIRECTION INPUT ;
    USE SIGNAL ;
    PORT
      LAYER M4 ;
        RECT  21.516 57.072 21.6 57.096 ;
    END
  END i[566]
  PIN i[567]
    DIRECTION INPUT ;
    USE SIGNAL ;
    PORT
      LAYER M4 ;
        RECT  21.516 57.168 21.6 57.192 ;
    END
  END i[567]
  PIN i[568]
    DIRECTION INPUT ;
    USE SIGNAL ;
    PORT
      LAYER M4 ;
        RECT  21.516 57.264 21.6 57.288 ;
    END
  END i[568]
  PIN i[569]
    DIRECTION INPUT ;
    USE SIGNAL ;
    PORT
      LAYER M4 ;
        RECT  21.516 57.36 21.6 57.384 ;
    END
  END i[569]
  PIN i[56]
    DIRECTION INPUT ;
    USE SIGNAL ;
    PORT
      LAYER M4 ;
        RECT  21.516 6.24 21.6 6.264 ;
    END
  END i[56]
  PIN i[570]
    DIRECTION INPUT ;
    USE SIGNAL ;
    PORT
      LAYER M4 ;
        RECT  21.516 57.456 21.6 57.48 ;
    END
  END i[570]
  PIN i[571]
    DIRECTION INPUT ;
    USE SIGNAL ;
    PORT
      LAYER M4 ;
        RECT  21.516 57.552 21.6 57.576 ;
    END
  END i[571]
  PIN i[572]
    DIRECTION INPUT ;
    USE SIGNAL ;
    PORT
      LAYER M4 ;
        RECT  21.516 57.648 21.6 57.672 ;
    END
  END i[572]
  PIN i[573]
    DIRECTION INPUT ;
    USE SIGNAL ;
    PORT
      LAYER M4 ;
        RECT  21.516 57.744 21.6 57.768 ;
    END
  END i[573]
  PIN i[574]
    DIRECTION INPUT ;
    USE SIGNAL ;
    PORT
      LAYER M4 ;
        RECT  21.516 57.84 21.6 57.864 ;
    END
  END i[574]
  PIN i[575]
    DIRECTION INPUT ;
    USE SIGNAL ;
    PORT
      LAYER M4 ;
        RECT  21.516 57.936 21.6 57.96 ;
    END
  END i[575]
  PIN i[576]
    DIRECTION INPUT ;
    USE SIGNAL ;
    PORT
      LAYER M4 ;
        RECT  21.516 58.032 21.6 58.056 ;
    END
  END i[576]
  PIN i[577]
    DIRECTION INPUT ;
    USE SIGNAL ;
    PORT
      LAYER M4 ;
        RECT  21.516 58.176 21.6 58.2 ;
    END
  END i[577]
  PIN i[578]
    DIRECTION INPUT ;
    USE SIGNAL ;
    PORT
      LAYER M4 ;
        RECT  21.516 58.272 21.6 58.296 ;
    END
  END i[578]
  PIN i[579]
    DIRECTION INPUT ;
    USE SIGNAL ;
    PORT
      LAYER M4 ;
        RECT  21.516 58.368 21.6 58.392 ;
    END
  END i[579]
  PIN i[57]
    DIRECTION INPUT ;
    USE SIGNAL ;
    PORT
      LAYER M4 ;
        RECT  21.516 6.336 21.6 6.36 ;
    END
  END i[57]
  PIN i[580]
    DIRECTION INPUT ;
    USE SIGNAL ;
    PORT
      LAYER M4 ;
        RECT  21.516 58.464 21.6 58.488 ;
    END
  END i[580]
  PIN i[581]
    DIRECTION INPUT ;
    USE SIGNAL ;
    PORT
      LAYER M4 ;
        RECT  21.516 58.56 21.6 58.584 ;
    END
  END i[581]
  PIN i[582]
    DIRECTION INPUT ;
    USE SIGNAL ;
    PORT
      LAYER M4 ;
        RECT  21.516 58.656 21.6 58.68 ;
    END
  END i[582]
  PIN i[583]
    DIRECTION INPUT ;
    USE SIGNAL ;
    PORT
      LAYER M4 ;
        RECT  21.516 58.752 21.6 58.776 ;
    END
  END i[583]
  PIN i[584]
    DIRECTION INPUT ;
    USE SIGNAL ;
    PORT
      LAYER M4 ;
        RECT  21.516 58.848 21.6 58.872 ;
    END
  END i[584]
  PIN i[585]
    DIRECTION INPUT ;
    USE SIGNAL ;
    PORT
      LAYER M4 ;
        RECT  21.516 58.944 21.6 58.968 ;
    END
  END i[585]
  PIN i[586]
    DIRECTION INPUT ;
    USE SIGNAL ;
    PORT
      LAYER M4 ;
        RECT  21.516 59.04 21.6 59.064 ;
    END
  END i[586]
  PIN i[587]
    DIRECTION INPUT ;
    USE SIGNAL ;
    PORT
      LAYER M4 ;
        RECT  21.516 59.136 21.6 59.16 ;
    END
  END i[587]
  PIN i[588]
    DIRECTION INPUT ;
    USE SIGNAL ;
    PORT
      LAYER M4 ;
        RECT  21.516 59.232 21.6 59.256 ;
    END
  END i[588]
  PIN i[589]
    DIRECTION INPUT ;
    USE SIGNAL ;
    PORT
      LAYER M4 ;
        RECT  21.516 59.328 21.6 59.352 ;
    END
  END i[589]
  PIN i[58]
    DIRECTION INPUT ;
    USE SIGNAL ;
    PORT
      LAYER M4 ;
        RECT  21.516 6.432 21.6 6.456 ;
    END
  END i[58]
  PIN i[590]
    DIRECTION INPUT ;
    USE SIGNAL ;
    PORT
      LAYER M4 ;
        RECT  21.516 59.472 21.6 59.496 ;
    END
  END i[590]
  PIN i[591]
    DIRECTION INPUT ;
    USE SIGNAL ;
    PORT
      LAYER M4 ;
        RECT  21.516 59.568 21.6 59.592 ;
    END
  END i[591]
  PIN i[592]
    DIRECTION INPUT ;
    USE SIGNAL ;
    PORT
      LAYER M4 ;
        RECT  21.516 59.664 21.6 59.688 ;
    END
  END i[592]
  PIN i[593]
    DIRECTION INPUT ;
    USE SIGNAL ;
    PORT
      LAYER M4 ;
        RECT  21.516 59.76 21.6 59.784 ;
    END
  END i[593]
  PIN i[594]
    DIRECTION INPUT ;
    USE SIGNAL ;
    PORT
      LAYER M4 ;
        RECT  21.516 59.856 21.6 59.88 ;
    END
  END i[594]
  PIN i[595]
    DIRECTION INPUT ;
    USE SIGNAL ;
    PORT
      LAYER M4 ;
        RECT  21.516 59.952 21.6 59.976 ;
    END
  END i[595]
  PIN i[596]
    DIRECTION INPUT ;
    USE SIGNAL ;
    PORT
      LAYER M4 ;
        RECT  21.516 60.048 21.6 60.072 ;
    END
  END i[596]
  PIN i[597]
    DIRECTION INPUT ;
    USE SIGNAL ;
    PORT
      LAYER M4 ;
        RECT  21.516 60.144 21.6 60.168 ;
    END
  END i[597]
  PIN i[598]
    DIRECTION INPUT ;
    USE SIGNAL ;
    PORT
      LAYER M4 ;
        RECT  21.516 60.24 21.6 60.264 ;
    END
  END i[598]
  PIN i[599]
    DIRECTION INPUT ;
    USE SIGNAL ;
    PORT
      LAYER M4 ;
        RECT  21.516 60.336 21.6 60.36 ;
    END
  END i[599]
  PIN i[59]
    DIRECTION INPUT ;
    USE SIGNAL ;
    PORT
      LAYER M4 ;
        RECT  21.516 6.528 21.6 6.552 ;
    END
  END i[59]
  PIN i[5]
    DIRECTION INPUT ;
    USE SIGNAL ;
    PORT
      LAYER M4 ;
        RECT  21.516 1.152 21.6 1.176 ;
    END
  END i[5]
  PIN i[600]
    DIRECTION INPUT ;
    USE SIGNAL ;
    PORT
      LAYER M4 ;
        RECT  21.516 60.432 21.6 60.456 ;
    END
  END i[600]
  PIN i[601]
    DIRECTION INPUT ;
    USE SIGNAL ;
    PORT
      LAYER M4 ;
        RECT  21.516 60.528 21.6 60.552 ;
    END
  END i[601]
  PIN i[602]
    DIRECTION INPUT ;
    USE SIGNAL ;
    PORT
      LAYER M4 ;
        RECT  21.516 60.624 21.6 60.648 ;
    END
  END i[602]
  PIN i[603]
    DIRECTION INPUT ;
    USE SIGNAL ;
    PORT
      LAYER M4 ;
        RECT  21.516 60.768 21.6 60.792 ;
    END
  END i[603]
  PIN i[604]
    DIRECTION INPUT ;
    USE SIGNAL ;
    PORT
      LAYER M4 ;
        RECT  21.516 60.864 21.6 60.888 ;
    END
  END i[604]
  PIN i[605]
    DIRECTION INPUT ;
    USE SIGNAL ;
    PORT
      LAYER M4 ;
        RECT  21.516 60.96 21.6 60.984 ;
    END
  END i[605]
  PIN i[606]
    DIRECTION INPUT ;
    USE SIGNAL ;
    PORT
      LAYER M4 ;
        RECT  21.516 61.056 21.6 61.08 ;
    END
  END i[606]
  PIN i[607]
    DIRECTION INPUT ;
    USE SIGNAL ;
    PORT
      LAYER M4 ;
        RECT  21.516 61.152 21.6 61.176 ;
    END
  END i[607]
  PIN i[608]
    DIRECTION INPUT ;
    USE SIGNAL ;
    PORT
      LAYER M4 ;
        RECT  21.516 61.248 21.6 61.272 ;
    END
  END i[608]
  PIN i[609]
    DIRECTION INPUT ;
    USE SIGNAL ;
    PORT
      LAYER M4 ;
        RECT  21.516 61.344 21.6 61.368 ;
    END
  END i[609]
  PIN i[60]
    DIRECTION INPUT ;
    USE SIGNAL ;
    PORT
      LAYER M4 ;
        RECT  21.516 6.624 21.6 6.648 ;
    END
  END i[60]
  PIN i[610]
    DIRECTION INPUT ;
    USE SIGNAL ;
    PORT
      LAYER M4 ;
        RECT  21.516 61.44 21.6 61.464 ;
    END
  END i[610]
  PIN i[611]
    DIRECTION INPUT ;
    USE SIGNAL ;
    PORT
      LAYER M4 ;
        RECT  21.516 61.536 21.6 61.56 ;
    END
  END i[611]
  PIN i[612]
    DIRECTION INPUT ;
    USE SIGNAL ;
    PORT
      LAYER M4 ;
        RECT  21.516 61.632 21.6 61.656 ;
    END
  END i[612]
  PIN i[613]
    DIRECTION INPUT ;
    USE SIGNAL ;
    PORT
      LAYER M4 ;
        RECT  21.516 61.728 21.6 61.752 ;
    END
  END i[613]
  PIN i[614]
    DIRECTION INPUT ;
    USE SIGNAL ;
    PORT
      LAYER M4 ;
        RECT  21.516 61.824 21.6 61.848 ;
    END
  END i[614]
  PIN i[615]
    DIRECTION INPUT ;
    USE SIGNAL ;
    PORT
      LAYER M4 ;
        RECT  21.516 61.92 21.6 61.944 ;
    END
  END i[615]
  PIN i[616]
    DIRECTION INPUT ;
    USE SIGNAL ;
    PORT
      LAYER M4 ;
        RECT  21.516 62.064 21.6 62.088 ;
    END
  END i[616]
  PIN i[617]
    DIRECTION INPUT ;
    USE SIGNAL ;
    PORT
      LAYER M4 ;
        RECT  21.516 62.16 21.6 62.184 ;
    END
  END i[617]
  PIN i[618]
    DIRECTION INPUT ;
    USE SIGNAL ;
    PORT
      LAYER M4 ;
        RECT  21.516 62.256 21.6 62.28 ;
    END
  END i[618]
  PIN i[619]
    DIRECTION INPUT ;
    USE SIGNAL ;
    PORT
      LAYER M4 ;
        RECT  21.516 62.352 21.6 62.376 ;
    END
  END i[619]
  PIN i[61]
    DIRECTION INPUT ;
    USE SIGNAL ;
    PORT
      LAYER M4 ;
        RECT  21.516 6.72 21.6 6.744 ;
    END
  END i[61]
  PIN i[620]
    DIRECTION INPUT ;
    USE SIGNAL ;
    PORT
      LAYER M4 ;
        RECT  21.516 62.448 21.6 62.472 ;
    END
  END i[620]
  PIN i[621]
    DIRECTION INPUT ;
    USE SIGNAL ;
    PORT
      LAYER M4 ;
        RECT  21.516 62.544 21.6 62.568 ;
    END
  END i[621]
  PIN i[622]
    DIRECTION INPUT ;
    USE SIGNAL ;
    PORT
      LAYER M4 ;
        RECT  21.516 62.64 21.6 62.664 ;
    END
  END i[622]
  PIN i[623]
    DIRECTION INPUT ;
    USE SIGNAL ;
    PORT
      LAYER M4 ;
        RECT  21.516 62.736 21.6 62.76 ;
    END
  END i[623]
  PIN i[62]
    DIRECTION INPUT ;
    USE SIGNAL ;
    PORT
      LAYER M4 ;
        RECT  21.516 6.816 21.6 6.84 ;
    END
  END i[62]
  PIN i[63]
    DIRECTION INPUT ;
    USE SIGNAL ;
    PORT
      LAYER M4 ;
        RECT  21.516 6.912 21.6 6.936 ;
    END
  END i[63]
  PIN i[64]
    DIRECTION INPUT ;
    USE SIGNAL ;
    PORT
      LAYER M4 ;
        RECT  21.516 7.008 21.6 7.032 ;
    END
  END i[64]
  PIN i[65]
    DIRECTION INPUT ;
    USE SIGNAL ;
    PORT
      LAYER M4 ;
        RECT  21.516 7.104 21.6 7.128 ;
    END
  END i[65]
  PIN i[66]
    DIRECTION INPUT ;
    USE SIGNAL ;
    PORT
      LAYER M4 ;
        RECT  21.516 7.2 21.6 7.224 ;
    END
  END i[66]
  PIN i[67]
    DIRECTION INPUT ;
    USE SIGNAL ;
    PORT
      LAYER M4 ;
        RECT  21.516 7.296 21.6 7.32 ;
    END
  END i[67]
  PIN i[68]
    DIRECTION INPUT ;
    USE SIGNAL ;
    PORT
      LAYER M4 ;
        RECT  21.516 7.44 21.6 7.464 ;
    END
  END i[68]
  PIN i[69]
    DIRECTION INPUT ;
    USE SIGNAL ;
    PORT
      LAYER M4 ;
        RECT  21.516 7.536 21.6 7.56 ;
    END
  END i[69]
  PIN i[6]
    DIRECTION INPUT ;
    USE SIGNAL ;
    PORT
      LAYER M4 ;
        RECT  21.516 1.248 21.6 1.272 ;
    END
  END i[6]
  PIN i[70]
    DIRECTION INPUT ;
    USE SIGNAL ;
    PORT
      LAYER M4 ;
        RECT  21.516 7.632 21.6 7.656 ;
    END
  END i[70]
  PIN i[71]
    DIRECTION INPUT ;
    USE SIGNAL ;
    PORT
      LAYER M4 ;
        RECT  21.516 7.728 21.6 7.752 ;
    END
  END i[71]
  PIN i[72]
    DIRECTION INPUT ;
    USE SIGNAL ;
    PORT
      LAYER M4 ;
        RECT  21.516 7.824 21.6 7.848 ;
    END
  END i[72]
  PIN i[73]
    DIRECTION INPUT ;
    USE SIGNAL ;
    PORT
      LAYER M4 ;
        RECT  21.516 7.92 21.6 7.944 ;
    END
  END i[73]
  PIN i[74]
    DIRECTION INPUT ;
    USE SIGNAL ;
    PORT
      LAYER M4 ;
        RECT  21.516 8.016 21.6 8.04 ;
    END
  END i[74]
  PIN i[75]
    DIRECTION INPUT ;
    USE SIGNAL ;
    PORT
      LAYER M4 ;
        RECT  21.516 8.112 21.6 8.136 ;
    END
  END i[75]
  PIN i[76]
    DIRECTION INPUT ;
    USE SIGNAL ;
    PORT
      LAYER M4 ;
        RECT  21.516 8.208 21.6 8.232 ;
    END
  END i[76]
  PIN i[77]
    DIRECTION INPUT ;
    USE SIGNAL ;
    PORT
      LAYER M4 ;
        RECT  21.516 8.304 21.6 8.328 ;
    END
  END i[77]
  PIN i[78]
    DIRECTION INPUT ;
    USE SIGNAL ;
    PORT
      LAYER M4 ;
        RECT  21.516 8.4 21.6 8.424 ;
    END
  END i[78]
  PIN i[79]
    DIRECTION INPUT ;
    USE SIGNAL ;
    PORT
      LAYER M4 ;
        RECT  21.516 8.496 21.6 8.52 ;
    END
  END i[79]
  PIN i[7]
    DIRECTION INPUT ;
    USE SIGNAL ;
    PORT
      LAYER M4 ;
        RECT  21.516 1.344 21.6 1.368 ;
    END
  END i[7]
  PIN i[80]
    DIRECTION INPUT ;
    USE SIGNAL ;
    PORT
      LAYER M4 ;
        RECT  21.516 8.592 21.6 8.616 ;
    END
  END i[80]
  PIN i[81]
    DIRECTION INPUT ;
    USE SIGNAL ;
    PORT
      LAYER M4 ;
        RECT  21.516 8.736 21.6 8.76 ;
    END
  END i[81]
  PIN i[82]
    DIRECTION INPUT ;
    USE SIGNAL ;
    PORT
      LAYER M4 ;
        RECT  21.516 8.832 21.6 8.856 ;
    END
  END i[82]
  PIN i[83]
    DIRECTION INPUT ;
    USE SIGNAL ;
    PORT
      LAYER M4 ;
        RECT  21.516 8.928 21.6 8.952 ;
    END
  END i[83]
  PIN i[84]
    DIRECTION INPUT ;
    USE SIGNAL ;
    PORT
      LAYER M4 ;
        RECT  21.516 9.024 21.6 9.048 ;
    END
  END i[84]
  PIN i[85]
    DIRECTION INPUT ;
    USE SIGNAL ;
    PORT
      LAYER M4 ;
        RECT  21.516 9.12 21.6 9.144 ;
    END
  END i[85]
  PIN i[86]
    DIRECTION INPUT ;
    USE SIGNAL ;
    PORT
      LAYER M4 ;
        RECT  21.516 9.216 21.6 9.24 ;
    END
  END i[86]
  PIN i[87]
    DIRECTION INPUT ;
    USE SIGNAL ;
    PORT
      LAYER M4 ;
        RECT  21.516 9.312 21.6 9.336 ;
    END
  END i[87]
  PIN i[88]
    DIRECTION INPUT ;
    USE SIGNAL ;
    PORT
      LAYER M4 ;
        RECT  21.516 9.408 21.6 9.432 ;
    END
  END i[88]
  PIN i[89]
    DIRECTION INPUT ;
    USE SIGNAL ;
    PORT
      LAYER M4 ;
        RECT  21.516 9.504 21.6 9.528 ;
    END
  END i[89]
  PIN i[8]
    DIRECTION INPUT ;
    USE SIGNAL ;
    PORT
      LAYER M4 ;
        RECT  21.516 1.44 21.6 1.464 ;
    END
  END i[8]
  PIN i[90]
    DIRECTION INPUT ;
    USE SIGNAL ;
    PORT
      LAYER M4 ;
        RECT  21.516 9.6 21.6 9.624 ;
    END
  END i[90]
  PIN i[91]
    DIRECTION INPUT ;
    USE SIGNAL ;
    PORT
      LAYER M4 ;
        RECT  21.516 9.696 21.6 9.72 ;
    END
  END i[91]
  PIN i[92]
    DIRECTION INPUT ;
    USE SIGNAL ;
    PORT
      LAYER M4 ;
        RECT  21.516 9.792 21.6 9.816 ;
    END
  END i[92]
  PIN i[93]
    DIRECTION INPUT ;
    USE SIGNAL ;
    PORT
      LAYER M4 ;
        RECT  21.516 9.888 21.6 9.912 ;
    END
  END i[93]
  PIN i[94]
    DIRECTION INPUT ;
    USE SIGNAL ;
    PORT
      LAYER M4 ;
        RECT  21.516 10.032 21.6 10.056 ;
    END
  END i[94]
  PIN i[95]
    DIRECTION INPUT ;
    USE SIGNAL ;
    PORT
      LAYER M4 ;
        RECT  21.516 10.128 21.6 10.152 ;
    END
  END i[95]
  PIN i[96]
    DIRECTION INPUT ;
    USE SIGNAL ;
    PORT
      LAYER M4 ;
        RECT  21.516 10.224 21.6 10.248 ;
    END
  END i[96]
  PIN i[97]
    DIRECTION INPUT ;
    USE SIGNAL ;
    PORT
      LAYER M4 ;
        RECT  21.516 10.32 21.6 10.344 ;
    END
  END i[97]
  PIN i[98]
    DIRECTION INPUT ;
    USE SIGNAL ;
    PORT
      LAYER M4 ;
        RECT  21.516 10.416 21.6 10.44 ;
    END
  END i[98]
  PIN i[99]
    DIRECTION INPUT ;
    USE SIGNAL ;
    PORT
      LAYER M4 ;
        RECT  21.516 10.512 21.6 10.536 ;
    END
  END i[99]
  PIN i[9]
    DIRECTION INPUT ;
    USE SIGNAL ;
    PORT
      LAYER M4 ;
        RECT  21.516 1.536 21.6 1.56 ;
    END
  END i[9]
  PIN o[0]
    DIRECTION OUTPUT ;
    USE SIGNAL ;
    PORT
      LAYER M4 ;
        RECT  0 0.624 0.084 0.648 ;
    END
  END o[0]
  PIN o[100]
    DIRECTION OUTPUT ;
    USE SIGNAL ;
    PORT
      LAYER M4 ;
        RECT  0 10.608 0.084 10.632 ;
    END
  END o[100]
  PIN o[101]
    DIRECTION OUTPUT ;
    USE SIGNAL ;
    PORT
      LAYER M4 ;
        RECT  0 10.704 0.084 10.728 ;
    END
  END o[101]
  PIN o[102]
    DIRECTION OUTPUT ;
    USE SIGNAL ;
    PORT
      LAYER M4 ;
        RECT  0 10.8 0.084 10.824 ;
    END
  END o[102]
  PIN o[103]
    DIRECTION OUTPUT ;
    USE SIGNAL ;
    PORT
      LAYER M4 ;
        RECT  0 10.896 0.084 10.92 ;
    END
  END o[103]
  PIN o[104]
    DIRECTION OUTPUT ;
    USE SIGNAL ;
    PORT
      LAYER M4 ;
        RECT  0 10.992 0.084 11.016 ;
    END
  END o[104]
  PIN o[105]
    DIRECTION OUTPUT ;
    USE SIGNAL ;
    PORT
      LAYER M4 ;
        RECT  0 11.088 0.084 11.112 ;
    END
  END o[105]
  PIN o[106]
    DIRECTION OUTPUT ;
    USE SIGNAL ;
    PORT
      LAYER M4 ;
        RECT  0 11.184 0.084 11.208 ;
    END
  END o[106]
  PIN o[107]
    DIRECTION OUTPUT ;
    USE SIGNAL ;
    PORT
      LAYER M4 ;
        RECT  0 11.328 0.084 11.352 ;
    END
  END o[107]
  PIN o[108]
    DIRECTION OUTPUT ;
    USE SIGNAL ;
    PORT
      LAYER M4 ;
        RECT  0 11.424 0.084 11.448 ;
    END
  END o[108]
  PIN o[109]
    DIRECTION OUTPUT ;
    USE SIGNAL ;
    PORT
      LAYER M4 ;
        RECT  0 11.52 0.084 11.544 ;
    END
  END o[109]
  PIN o[10]
    DIRECTION OUTPUT ;
    USE SIGNAL ;
    PORT
      LAYER M4 ;
        RECT  0 1.632 0.084 1.656 ;
    END
  END o[10]
  PIN o[110]
    DIRECTION OUTPUT ;
    USE SIGNAL ;
    PORT
      LAYER M4 ;
        RECT  0 11.616 0.084 11.64 ;
    END
  END o[110]
  PIN o[111]
    DIRECTION OUTPUT ;
    USE SIGNAL ;
    PORT
      LAYER M4 ;
        RECT  0 11.712 0.084 11.736 ;
    END
  END o[111]
  PIN o[112]
    DIRECTION OUTPUT ;
    USE SIGNAL ;
    PORT
      LAYER M4 ;
        RECT  0 11.808 0.084 11.832 ;
    END
  END o[112]
  PIN o[113]
    DIRECTION OUTPUT ;
    USE SIGNAL ;
    PORT
      LAYER M4 ;
        RECT  0 11.904 0.084 11.928 ;
    END
  END o[113]
  PIN o[114]
    DIRECTION OUTPUT ;
    USE SIGNAL ;
    PORT
      LAYER M4 ;
        RECT  0 12 0.084 12.024 ;
    END
  END o[114]
  PIN o[115]
    DIRECTION OUTPUT ;
    USE SIGNAL ;
    PORT
      LAYER M4 ;
        RECT  0 12.096 0.084 12.12 ;
    END
  END o[115]
  PIN o[116]
    DIRECTION OUTPUT ;
    USE SIGNAL ;
    PORT
      LAYER M4 ;
        RECT  0 12.192 0.084 12.216 ;
    END
  END o[116]
  PIN o[117]
    DIRECTION OUTPUT ;
    USE SIGNAL ;
    PORT
      LAYER M4 ;
        RECT  0 12.288 0.084 12.312 ;
    END
  END o[117]
  PIN o[118]
    DIRECTION OUTPUT ;
    USE SIGNAL ;
    PORT
      LAYER M4 ;
        RECT  0 12.384 0.084 12.408 ;
    END
  END o[118]
  PIN o[119]
    DIRECTION OUTPUT ;
    USE SIGNAL ;
    PORT
      LAYER M4 ;
        RECT  0 12.48 0.084 12.504 ;
    END
  END o[119]
  PIN o[11]
    DIRECTION OUTPUT ;
    USE SIGNAL ;
    PORT
      LAYER M4 ;
        RECT  0 1.728 0.084 1.752 ;
    END
  END o[11]
  PIN o[120]
    DIRECTION OUTPUT ;
    USE SIGNAL ;
    PORT
      LAYER M4 ;
        RECT  0 12.576 0.084 12.6 ;
    END
  END o[120]
  PIN o[121]
    DIRECTION OUTPUT ;
    USE SIGNAL ;
    PORT
      LAYER M4 ;
        RECT  0 12.72 0.084 12.744 ;
    END
  END o[121]
  PIN o[122]
    DIRECTION OUTPUT ;
    USE SIGNAL ;
    PORT
      LAYER M4 ;
        RECT  0 12.816 0.084 12.84 ;
    END
  END o[122]
  PIN o[123]
    DIRECTION OUTPUT ;
    USE SIGNAL ;
    PORT
      LAYER M4 ;
        RECT  0 12.912 0.084 12.936 ;
    END
  END o[123]
  PIN o[124]
    DIRECTION OUTPUT ;
    USE SIGNAL ;
    PORT
      LAYER M4 ;
        RECT  0 13.008 0.084 13.032 ;
    END
  END o[124]
  PIN o[125]
    DIRECTION OUTPUT ;
    USE SIGNAL ;
    PORT
      LAYER M4 ;
        RECT  0 13.104 0.084 13.128 ;
    END
  END o[125]
  PIN o[126]
    DIRECTION OUTPUT ;
    USE SIGNAL ;
    PORT
      LAYER M4 ;
        RECT  0 13.2 0.084 13.224 ;
    END
  END o[126]
  PIN o[127]
    DIRECTION OUTPUT ;
    USE SIGNAL ;
    PORT
      LAYER M4 ;
        RECT  0 13.296 0.084 13.32 ;
    END
  END o[127]
  PIN o[128]
    DIRECTION OUTPUT ;
    USE SIGNAL ;
    PORT
      LAYER M4 ;
        RECT  0 13.392 0.084 13.416 ;
    END
  END o[128]
  PIN o[129]
    DIRECTION OUTPUT ;
    USE SIGNAL ;
    PORT
      LAYER M4 ;
        RECT  0 13.488 0.084 13.512 ;
    END
  END o[129]
  PIN o[12]
    DIRECTION OUTPUT ;
    USE SIGNAL ;
    PORT
      LAYER M4 ;
        RECT  0 1.824 0.084 1.848 ;
    END
  END o[12]
  PIN o[130]
    DIRECTION OUTPUT ;
    USE SIGNAL ;
    PORT
      LAYER M4 ;
        RECT  0 13.584 0.084 13.608 ;
    END
  END o[130]
  PIN o[131]
    DIRECTION OUTPUT ;
    USE SIGNAL ;
    PORT
      LAYER M4 ;
        RECT  0 13.68 0.084 13.704 ;
    END
  END o[131]
  PIN o[132]
    DIRECTION OUTPUT ;
    USE SIGNAL ;
    PORT
      LAYER M4 ;
        RECT  0 13.776 0.084 13.8 ;
    END
  END o[132]
  PIN o[133]
    DIRECTION OUTPUT ;
    USE SIGNAL ;
    PORT
      LAYER M4 ;
        RECT  0 13.872 0.084 13.896 ;
    END
  END o[133]
  PIN o[134]
    DIRECTION OUTPUT ;
    USE SIGNAL ;
    PORT
      LAYER M4 ;
        RECT  0 14.016 0.084 14.04 ;
    END
  END o[134]
  PIN o[135]
    DIRECTION OUTPUT ;
    USE SIGNAL ;
    PORT
      LAYER M4 ;
        RECT  0 14.112 0.084 14.136 ;
    END
  END o[135]
  PIN o[136]
    DIRECTION OUTPUT ;
    USE SIGNAL ;
    PORT
      LAYER M4 ;
        RECT  0 14.208 0.084 14.232 ;
    END
  END o[136]
  PIN o[137]
    DIRECTION OUTPUT ;
    USE SIGNAL ;
    PORT
      LAYER M4 ;
        RECT  0 14.304 0.084 14.328 ;
    END
  END o[137]
  PIN o[138]
    DIRECTION OUTPUT ;
    USE SIGNAL ;
    PORT
      LAYER M4 ;
        RECT  0 14.4 0.084 14.424 ;
    END
  END o[138]
  PIN o[139]
    DIRECTION OUTPUT ;
    USE SIGNAL ;
    PORT
      LAYER M4 ;
        RECT  0 14.496 0.084 14.52 ;
    END
  END o[139]
  PIN o[13]
    DIRECTION OUTPUT ;
    USE SIGNAL ;
    PORT
      LAYER M4 ;
        RECT  0 1.92 0.084 1.944 ;
    END
  END o[13]
  PIN o[140]
    DIRECTION OUTPUT ;
    USE SIGNAL ;
    PORT
      LAYER M4 ;
        RECT  0 14.592 0.084 14.616 ;
    END
  END o[140]
  PIN o[141]
    DIRECTION OUTPUT ;
    USE SIGNAL ;
    PORT
      LAYER M4 ;
        RECT  0 14.688 0.084 14.712 ;
    END
  END o[141]
  PIN o[142]
    DIRECTION OUTPUT ;
    USE SIGNAL ;
    PORT
      LAYER M4 ;
        RECT  0 14.784 0.084 14.808 ;
    END
  END o[142]
  PIN o[143]
    DIRECTION OUTPUT ;
    USE SIGNAL ;
    PORT
      LAYER M4 ;
        RECT  0 14.88 0.084 14.904 ;
    END
  END o[143]
  PIN o[144]
    DIRECTION OUTPUT ;
    USE SIGNAL ;
    PORT
      LAYER M4 ;
        RECT  0 14.976 0.084 15 ;
    END
  END o[144]
  PIN o[145]
    DIRECTION OUTPUT ;
    USE SIGNAL ;
    PORT
      LAYER M4 ;
        RECT  0 15.072 0.084 15.096 ;
    END
  END o[145]
  PIN o[146]
    DIRECTION OUTPUT ;
    USE SIGNAL ;
    PORT
      LAYER M4 ;
        RECT  0 15.168 0.084 15.192 ;
    END
  END o[146]
  PIN o[147]
    DIRECTION OUTPUT ;
    USE SIGNAL ;
    PORT
      LAYER M4 ;
        RECT  0 15.312 0.084 15.336 ;
    END
  END o[147]
  PIN o[148]
    DIRECTION OUTPUT ;
    USE SIGNAL ;
    PORT
      LAYER M4 ;
        RECT  0 15.408 0.084 15.432 ;
    END
  END o[148]
  PIN o[149]
    DIRECTION OUTPUT ;
    USE SIGNAL ;
    PORT
      LAYER M4 ;
        RECT  0 15.504 0.084 15.528 ;
    END
  END o[149]
  PIN o[14]
    DIRECTION OUTPUT ;
    USE SIGNAL ;
    PORT
      LAYER M4 ;
        RECT  0 2.016 0.084 2.04 ;
    END
  END o[14]
  PIN o[150]
    DIRECTION OUTPUT ;
    USE SIGNAL ;
    PORT
      LAYER M4 ;
        RECT  0 15.6 0.084 15.624 ;
    END
  END o[150]
  PIN o[151]
    DIRECTION OUTPUT ;
    USE SIGNAL ;
    PORT
      LAYER M4 ;
        RECT  0 15.696 0.084 15.72 ;
    END
  END o[151]
  PIN o[152]
    DIRECTION OUTPUT ;
    USE SIGNAL ;
    PORT
      LAYER M4 ;
        RECT  0 15.792 0.084 15.816 ;
    END
  END o[152]
  PIN o[153]
    DIRECTION OUTPUT ;
    USE SIGNAL ;
    PORT
      LAYER M4 ;
        RECT  0 15.888 0.084 15.912 ;
    END
  END o[153]
  PIN o[154]
    DIRECTION OUTPUT ;
    USE SIGNAL ;
    PORT
      LAYER M4 ;
        RECT  0 15.984 0.084 16.008 ;
    END
  END o[154]
  PIN o[155]
    DIRECTION OUTPUT ;
    USE SIGNAL ;
    PORT
      LAYER M4 ;
        RECT  0 16.08 0.084 16.104 ;
    END
  END o[155]
  PIN o[156]
    DIRECTION OUTPUT ;
    USE SIGNAL ;
    PORT
      LAYER M4 ;
        RECT  0 16.176 0.084 16.2 ;
    END
  END o[156]
  PIN o[157]
    DIRECTION OUTPUT ;
    USE SIGNAL ;
    PORT
      LAYER M4 ;
        RECT  0 16.272 0.084 16.296 ;
    END
  END o[157]
  PIN o[158]
    DIRECTION OUTPUT ;
    USE SIGNAL ;
    PORT
      LAYER M4 ;
        RECT  0 16.368 0.084 16.392 ;
    END
  END o[158]
  PIN o[159]
    DIRECTION OUTPUT ;
    USE SIGNAL ;
    PORT
      LAYER M4 ;
        RECT  0 16.464 0.084 16.488 ;
    END
  END o[159]
  PIN o[15]
    DIRECTION OUTPUT ;
    USE SIGNAL ;
    PORT
      LAYER M4 ;
        RECT  0 2.112 0.084 2.136 ;
    END
  END o[15]
  PIN o[160]
    DIRECTION OUTPUT ;
    USE SIGNAL ;
    PORT
      LAYER M4 ;
        RECT  0 16.608 0.084 16.632 ;
    END
  END o[160]
  PIN o[161]
    DIRECTION OUTPUT ;
    USE SIGNAL ;
    PORT
      LAYER M4 ;
        RECT  0 16.704 0.084 16.728 ;
    END
  END o[161]
  PIN o[162]
    DIRECTION OUTPUT ;
    USE SIGNAL ;
    PORT
      LAYER M4 ;
        RECT  0 16.8 0.084 16.824 ;
    END
  END o[162]
  PIN o[163]
    DIRECTION OUTPUT ;
    USE SIGNAL ;
    PORT
      LAYER M4 ;
        RECT  0 16.896 0.084 16.92 ;
    END
  END o[163]
  PIN o[164]
    DIRECTION OUTPUT ;
    USE SIGNAL ;
    PORT
      LAYER M4 ;
        RECT  0 16.992 0.084 17.016 ;
    END
  END o[164]
  PIN o[165]
    DIRECTION OUTPUT ;
    USE SIGNAL ;
    PORT
      LAYER M4 ;
        RECT  0 17.088 0.084 17.112 ;
    END
  END o[165]
  PIN o[166]
    DIRECTION OUTPUT ;
    USE SIGNAL ;
    PORT
      LAYER M4 ;
        RECT  0 17.184 0.084 17.208 ;
    END
  END o[166]
  PIN o[167]
    DIRECTION OUTPUT ;
    USE SIGNAL ;
    PORT
      LAYER M4 ;
        RECT  0 17.28 0.084 17.304 ;
    END
  END o[167]
  PIN o[168]
    DIRECTION OUTPUT ;
    USE SIGNAL ;
    PORT
      LAYER M4 ;
        RECT  0 17.376 0.084 17.4 ;
    END
  END o[168]
  PIN o[169]
    DIRECTION OUTPUT ;
    USE SIGNAL ;
    PORT
      LAYER M4 ;
        RECT  0 17.472 0.084 17.496 ;
    END
  END o[169]
  PIN o[16]
    DIRECTION OUTPUT ;
    USE SIGNAL ;
    PORT
      LAYER M4 ;
        RECT  0 2.256 0.084 2.28 ;
    END
  END o[16]
  PIN o[170]
    DIRECTION OUTPUT ;
    USE SIGNAL ;
    PORT
      LAYER M4 ;
        RECT  0 17.568 0.084 17.592 ;
    END
  END o[170]
  PIN o[171]
    DIRECTION OUTPUT ;
    USE SIGNAL ;
    PORT
      LAYER M4 ;
        RECT  0 17.664 0.084 17.688 ;
    END
  END o[171]
  PIN o[172]
    DIRECTION OUTPUT ;
    USE SIGNAL ;
    PORT
      LAYER M4 ;
        RECT  0 17.76 0.084 17.784 ;
    END
  END o[172]
  PIN o[173]
    DIRECTION OUTPUT ;
    USE SIGNAL ;
    PORT
      LAYER M4 ;
        RECT  0 17.904 0.084 17.928 ;
    END
  END o[173]
  PIN o[174]
    DIRECTION OUTPUT ;
    USE SIGNAL ;
    PORT
      LAYER M4 ;
        RECT  0 18 0.084 18.024 ;
    END
  END o[174]
  PIN o[175]
    DIRECTION OUTPUT ;
    USE SIGNAL ;
    PORT
      LAYER M4 ;
        RECT  0 18.096 0.084 18.12 ;
    END
  END o[175]
  PIN o[176]
    DIRECTION OUTPUT ;
    USE SIGNAL ;
    PORT
      LAYER M4 ;
        RECT  0 18.192 0.084 18.216 ;
    END
  END o[176]
  PIN o[177]
    DIRECTION OUTPUT ;
    USE SIGNAL ;
    PORT
      LAYER M4 ;
        RECT  0 18.288 0.084 18.312 ;
    END
  END o[177]
  PIN o[178]
    DIRECTION OUTPUT ;
    USE SIGNAL ;
    PORT
      LAYER M4 ;
        RECT  0 18.384 0.084 18.408 ;
    END
  END o[178]
  PIN o[179]
    DIRECTION OUTPUT ;
    USE SIGNAL ;
    PORT
      LAYER M4 ;
        RECT  0 18.48 0.084 18.504 ;
    END
  END o[179]
  PIN o[17]
    DIRECTION OUTPUT ;
    USE SIGNAL ;
    PORT
      LAYER M4 ;
        RECT  0 2.352 0.084 2.376 ;
    END
  END o[17]
  PIN o[180]
    DIRECTION OUTPUT ;
    USE SIGNAL ;
    PORT
      LAYER M4 ;
        RECT  0 18.576 0.084 18.6 ;
    END
  END o[180]
  PIN o[181]
    DIRECTION OUTPUT ;
    USE SIGNAL ;
    PORT
      LAYER M4 ;
        RECT  0 18.672 0.084 18.696 ;
    END
  END o[181]
  PIN o[182]
    DIRECTION OUTPUT ;
    USE SIGNAL ;
    PORT
      LAYER M4 ;
        RECT  0 18.768 0.084 18.792 ;
    END
  END o[182]
  PIN o[183]
    DIRECTION OUTPUT ;
    USE SIGNAL ;
    PORT
      LAYER M4 ;
        RECT  0 18.864 0.084 18.888 ;
    END
  END o[183]
  PIN o[184]
    DIRECTION OUTPUT ;
    USE SIGNAL ;
    PORT
      LAYER M4 ;
        RECT  0 18.96 0.084 18.984 ;
    END
  END o[184]
  PIN o[185]
    DIRECTION OUTPUT ;
    USE SIGNAL ;
    PORT
      LAYER M4 ;
        RECT  0 19.056 0.084 19.08 ;
    END
  END o[185]
  PIN o[186]
    DIRECTION OUTPUT ;
    USE SIGNAL ;
    PORT
      LAYER M4 ;
        RECT  0 19.2 0.084 19.224 ;
    END
  END o[186]
  PIN o[187]
    DIRECTION OUTPUT ;
    USE SIGNAL ;
    PORT
      LAYER M4 ;
        RECT  0 19.296 0.084 19.32 ;
    END
  END o[187]
  PIN o[188]
    DIRECTION OUTPUT ;
    USE SIGNAL ;
    PORT
      LAYER M4 ;
        RECT  0 19.392 0.084 19.416 ;
    END
  END o[188]
  PIN o[189]
    DIRECTION OUTPUT ;
    USE SIGNAL ;
    PORT
      LAYER M4 ;
        RECT  0 19.488 0.084 19.512 ;
    END
  END o[189]
  PIN o[18]
    DIRECTION OUTPUT ;
    USE SIGNAL ;
    PORT
      LAYER M4 ;
        RECT  0 2.448 0.084 2.472 ;
    END
  END o[18]
  PIN o[190]
    DIRECTION OUTPUT ;
    USE SIGNAL ;
    PORT
      LAYER M4 ;
        RECT  0 19.584 0.084 19.608 ;
    END
  END o[190]
  PIN o[191]
    DIRECTION OUTPUT ;
    USE SIGNAL ;
    PORT
      LAYER M4 ;
        RECT  0 19.68 0.084 19.704 ;
    END
  END o[191]
  PIN o[192]
    DIRECTION OUTPUT ;
    USE SIGNAL ;
    PORT
      LAYER M4 ;
        RECT  0 19.776 0.084 19.8 ;
    END
  END o[192]
  PIN o[193]
    DIRECTION OUTPUT ;
    USE SIGNAL ;
    PORT
      LAYER M4 ;
        RECT  0 19.872 0.084 19.896 ;
    END
  END o[193]
  PIN o[194]
    DIRECTION OUTPUT ;
    USE SIGNAL ;
    PORT
      LAYER M4 ;
        RECT  0 19.968 0.084 19.992 ;
    END
  END o[194]
  PIN o[195]
    DIRECTION OUTPUT ;
    USE SIGNAL ;
    PORT
      LAYER M4 ;
        RECT  0 20.064 0.084 20.088 ;
    END
  END o[195]
  PIN o[196]
    DIRECTION OUTPUT ;
    USE SIGNAL ;
    PORT
      LAYER M4 ;
        RECT  0 20.16 0.084 20.184 ;
    END
  END o[196]
  PIN o[197]
    DIRECTION OUTPUT ;
    USE SIGNAL ;
    PORT
      LAYER M4 ;
        RECT  0 20.256 0.084 20.28 ;
    END
  END o[197]
  PIN o[198]
    DIRECTION OUTPUT ;
    USE SIGNAL ;
    PORT
      LAYER M4 ;
        RECT  0 20.352 0.084 20.376 ;
    END
  END o[198]
  PIN o[199]
    DIRECTION OUTPUT ;
    USE SIGNAL ;
    PORT
      LAYER M4 ;
        RECT  0 20.496 0.084 20.52 ;
    END
  END o[199]
  PIN o[19]
    DIRECTION OUTPUT ;
    USE SIGNAL ;
    PORT
      LAYER M4 ;
        RECT  0 2.544 0.084 2.568 ;
    END
  END o[19]
  PIN o[1]
    DIRECTION OUTPUT ;
    USE SIGNAL ;
    PORT
      LAYER M4 ;
        RECT  0 0.72 0.084 0.744 ;
    END
  END o[1]
  PIN o[200]
    DIRECTION OUTPUT ;
    USE SIGNAL ;
    PORT
      LAYER M4 ;
        RECT  0 20.592 0.084 20.616 ;
    END
  END o[200]
  PIN o[201]
    DIRECTION OUTPUT ;
    USE SIGNAL ;
    PORT
      LAYER M4 ;
        RECT  0 20.688 0.084 20.712 ;
    END
  END o[201]
  PIN o[202]
    DIRECTION OUTPUT ;
    USE SIGNAL ;
    PORT
      LAYER M4 ;
        RECT  0 20.784 0.084 20.808 ;
    END
  END o[202]
  PIN o[203]
    DIRECTION OUTPUT ;
    USE SIGNAL ;
    PORT
      LAYER M4 ;
        RECT  0 20.88 0.084 20.904 ;
    END
  END o[203]
  PIN o[204]
    DIRECTION OUTPUT ;
    USE SIGNAL ;
    PORT
      LAYER M4 ;
        RECT  0 20.976 0.084 21 ;
    END
  END o[204]
  PIN o[205]
    DIRECTION OUTPUT ;
    USE SIGNAL ;
    PORT
      LAYER M4 ;
        RECT  0 21.072 0.084 21.096 ;
    END
  END o[205]
  PIN o[206]
    DIRECTION OUTPUT ;
    USE SIGNAL ;
    PORT
      LAYER M4 ;
        RECT  0 21.168 0.084 21.192 ;
    END
  END o[206]
  PIN o[207]
    DIRECTION OUTPUT ;
    USE SIGNAL ;
    PORT
      LAYER M4 ;
        RECT  0 21.264 0.084 21.288 ;
    END
  END o[207]
  PIN o[208]
    DIRECTION OUTPUT ;
    USE SIGNAL ;
    PORT
      LAYER M4 ;
        RECT  0 21.36 0.084 21.384 ;
    END
  END o[208]
  PIN o[209]
    DIRECTION OUTPUT ;
    USE SIGNAL ;
    PORT
      LAYER M4 ;
        RECT  0 21.456 0.084 21.48 ;
    END
  END o[209]
  PIN o[20]
    DIRECTION OUTPUT ;
    USE SIGNAL ;
    PORT
      LAYER M4 ;
        RECT  0 2.64 0.084 2.664 ;
    END
  END o[20]
  PIN o[210]
    DIRECTION OUTPUT ;
    USE SIGNAL ;
    PORT
      LAYER M4 ;
        RECT  0 21.552 0.084 21.576 ;
    END
  END o[210]
  PIN o[211]
    DIRECTION OUTPUT ;
    USE SIGNAL ;
    PORT
      LAYER M4 ;
        RECT  0 21.648 0.084 21.672 ;
    END
  END o[211]
  PIN o[212]
    DIRECTION OUTPUT ;
    USE SIGNAL ;
    PORT
      LAYER M4 ;
        RECT  0 21.792 0.084 21.816 ;
    END
  END o[212]
  PIN o[213]
    DIRECTION OUTPUT ;
    USE SIGNAL ;
    PORT
      LAYER M4 ;
        RECT  0 21.888 0.084 21.912 ;
    END
  END o[213]
  PIN o[214]
    DIRECTION OUTPUT ;
    USE SIGNAL ;
    PORT
      LAYER M4 ;
        RECT  0 21.984 0.084 22.008 ;
    END
  END o[214]
  PIN o[215]
    DIRECTION OUTPUT ;
    USE SIGNAL ;
    PORT
      LAYER M4 ;
        RECT  0 22.08 0.084 22.104 ;
    END
  END o[215]
  PIN o[216]
    DIRECTION OUTPUT ;
    USE SIGNAL ;
    PORT
      LAYER M4 ;
        RECT  0 22.176 0.084 22.2 ;
    END
  END o[216]
  PIN o[217]
    DIRECTION OUTPUT ;
    USE SIGNAL ;
    PORT
      LAYER M4 ;
        RECT  0 22.272 0.084 22.296 ;
    END
  END o[217]
  PIN o[218]
    DIRECTION OUTPUT ;
    USE SIGNAL ;
    PORT
      LAYER M4 ;
        RECT  0 22.368 0.084 22.392 ;
    END
  END o[218]
  PIN o[219]
    DIRECTION OUTPUT ;
    USE SIGNAL ;
    PORT
      LAYER M4 ;
        RECT  0 22.464 0.084 22.488 ;
    END
  END o[219]
  PIN o[21]
    DIRECTION OUTPUT ;
    USE SIGNAL ;
    PORT
      LAYER M4 ;
        RECT  0 2.736 0.084 2.76 ;
    END
  END o[21]
  PIN o[220]
    DIRECTION OUTPUT ;
    USE SIGNAL ;
    PORT
      LAYER M4 ;
        RECT  0 22.56 0.084 22.584 ;
    END
  END o[220]
  PIN o[221]
    DIRECTION OUTPUT ;
    USE SIGNAL ;
    PORT
      LAYER M4 ;
        RECT  0 22.656 0.084 22.68 ;
    END
  END o[221]
  PIN o[222]
    DIRECTION OUTPUT ;
    USE SIGNAL ;
    PORT
      LAYER M4 ;
        RECT  0 22.752 0.084 22.776 ;
    END
  END o[222]
  PIN o[223]
    DIRECTION OUTPUT ;
    USE SIGNAL ;
    PORT
      LAYER M4 ;
        RECT  0 22.848 0.084 22.872 ;
    END
  END o[223]
  PIN o[224]
    DIRECTION OUTPUT ;
    USE SIGNAL ;
    PORT
      LAYER M4 ;
        RECT  0 22.944 0.084 22.968 ;
    END
  END o[224]
  PIN o[225]
    DIRECTION OUTPUT ;
    USE SIGNAL ;
    PORT
      LAYER M4 ;
        RECT  0 23.088 0.084 23.112 ;
    END
  END o[225]
  PIN o[226]
    DIRECTION OUTPUT ;
    USE SIGNAL ;
    PORT
      LAYER M4 ;
        RECT  0 23.184 0.084 23.208 ;
    END
  END o[226]
  PIN o[227]
    DIRECTION OUTPUT ;
    USE SIGNAL ;
    PORT
      LAYER M4 ;
        RECT  0 23.28 0.084 23.304 ;
    END
  END o[227]
  PIN o[228]
    DIRECTION OUTPUT ;
    USE SIGNAL ;
    PORT
      LAYER M4 ;
        RECT  0 23.376 0.084 23.4 ;
    END
  END o[228]
  PIN o[229]
    DIRECTION OUTPUT ;
    USE SIGNAL ;
    PORT
      LAYER M4 ;
        RECT  0 23.472 0.084 23.496 ;
    END
  END o[229]
  PIN o[22]
    DIRECTION OUTPUT ;
    USE SIGNAL ;
    PORT
      LAYER M4 ;
        RECT  0 2.832 0.084 2.856 ;
    END
  END o[22]
  PIN o[230]
    DIRECTION OUTPUT ;
    USE SIGNAL ;
    PORT
      LAYER M4 ;
        RECT  0 23.568 0.084 23.592 ;
    END
  END o[230]
  PIN o[231]
    DIRECTION OUTPUT ;
    USE SIGNAL ;
    PORT
      LAYER M4 ;
        RECT  0 23.664 0.084 23.688 ;
    END
  END o[231]
  PIN o[232]
    DIRECTION OUTPUT ;
    USE SIGNAL ;
    PORT
      LAYER M4 ;
        RECT  0 23.76 0.084 23.784 ;
    END
  END o[232]
  PIN o[233]
    DIRECTION OUTPUT ;
    USE SIGNAL ;
    PORT
      LAYER M4 ;
        RECT  0 23.856 0.084 23.88 ;
    END
  END o[233]
  PIN o[234]
    DIRECTION OUTPUT ;
    USE SIGNAL ;
    PORT
      LAYER M4 ;
        RECT  0 23.952 0.084 23.976 ;
    END
  END o[234]
  PIN o[235]
    DIRECTION OUTPUT ;
    USE SIGNAL ;
    PORT
      LAYER M4 ;
        RECT  0 24.048 0.084 24.072 ;
    END
  END o[235]
  PIN o[236]
    DIRECTION OUTPUT ;
    USE SIGNAL ;
    PORT
      LAYER M4 ;
        RECT  0 24.144 0.084 24.168 ;
    END
  END o[236]
  PIN o[237]
    DIRECTION OUTPUT ;
    USE SIGNAL ;
    PORT
      LAYER M4 ;
        RECT  0 24.24 0.084 24.264 ;
    END
  END o[237]
  PIN o[238]
    DIRECTION OUTPUT ;
    USE SIGNAL ;
    PORT
      LAYER M4 ;
        RECT  0 24.384 0.084 24.408 ;
    END
  END o[238]
  PIN o[239]
    DIRECTION OUTPUT ;
    USE SIGNAL ;
    PORT
      LAYER M4 ;
        RECT  0 24.48 0.084 24.504 ;
    END
  END o[239]
  PIN o[23]
    DIRECTION OUTPUT ;
    USE SIGNAL ;
    PORT
      LAYER M4 ;
        RECT  0 2.928 0.084 2.952 ;
    END
  END o[23]
  PIN o[240]
    DIRECTION OUTPUT ;
    USE SIGNAL ;
    PORT
      LAYER M4 ;
        RECT  0 24.576 0.084 24.6 ;
    END
  END o[240]
  PIN o[241]
    DIRECTION OUTPUT ;
    USE SIGNAL ;
    PORT
      LAYER M4 ;
        RECT  0 24.672 0.084 24.696 ;
    END
  END o[241]
  PIN o[242]
    DIRECTION OUTPUT ;
    USE SIGNAL ;
    PORT
      LAYER M4 ;
        RECT  0 24.768 0.084 24.792 ;
    END
  END o[242]
  PIN o[243]
    DIRECTION OUTPUT ;
    USE SIGNAL ;
    PORT
      LAYER M4 ;
        RECT  0 24.864 0.084 24.888 ;
    END
  END o[243]
  PIN o[244]
    DIRECTION OUTPUT ;
    USE SIGNAL ;
    PORT
      LAYER M4 ;
        RECT  0 24.96 0.084 24.984 ;
    END
  END o[244]
  PIN o[245]
    DIRECTION OUTPUT ;
    USE SIGNAL ;
    PORT
      LAYER M4 ;
        RECT  0 25.056 0.084 25.08 ;
    END
  END o[245]
  PIN o[246]
    DIRECTION OUTPUT ;
    USE SIGNAL ;
    PORT
      LAYER M4 ;
        RECT  0 25.152 0.084 25.176 ;
    END
  END o[246]
  PIN o[247]
    DIRECTION OUTPUT ;
    USE SIGNAL ;
    PORT
      LAYER M4 ;
        RECT  0 25.248 0.084 25.272 ;
    END
  END o[247]
  PIN o[248]
    DIRECTION OUTPUT ;
    USE SIGNAL ;
    PORT
      LAYER M4 ;
        RECT  0 25.344 0.084 25.368 ;
    END
  END o[248]
  PIN o[249]
    DIRECTION OUTPUT ;
    USE SIGNAL ;
    PORT
      LAYER M4 ;
        RECT  0 25.44 0.084 25.464 ;
    END
  END o[249]
  PIN o[24]
    DIRECTION OUTPUT ;
    USE SIGNAL ;
    PORT
      LAYER M4 ;
        RECT  0 3.024 0.084 3.048 ;
    END
  END o[24]
  PIN o[250]
    DIRECTION OUTPUT ;
    USE SIGNAL ;
    PORT
      LAYER M4 ;
        RECT  0 25.536 0.084 25.56 ;
    END
  END o[250]
  PIN o[251]
    DIRECTION OUTPUT ;
    USE SIGNAL ;
    PORT
      LAYER M4 ;
        RECT  0 25.68 0.084 25.704 ;
    END
  END o[251]
  PIN o[252]
    DIRECTION OUTPUT ;
    USE SIGNAL ;
    PORT
      LAYER M4 ;
        RECT  0 25.776 0.084 25.8 ;
    END
  END o[252]
  PIN o[253]
    DIRECTION OUTPUT ;
    USE SIGNAL ;
    PORT
      LAYER M4 ;
        RECT  0 25.872 0.084 25.896 ;
    END
  END o[253]
  PIN o[254]
    DIRECTION OUTPUT ;
    USE SIGNAL ;
    PORT
      LAYER M4 ;
        RECT  0 25.968 0.084 25.992 ;
    END
  END o[254]
  PIN o[255]
    DIRECTION OUTPUT ;
    USE SIGNAL ;
    PORT
      LAYER M4 ;
        RECT  0 26.064 0.084 26.088 ;
    END
  END o[255]
  PIN o[256]
    DIRECTION OUTPUT ;
    USE SIGNAL ;
    PORT
      LAYER M4 ;
        RECT  0 26.16 0.084 26.184 ;
    END
  END o[256]
  PIN o[257]
    DIRECTION OUTPUT ;
    USE SIGNAL ;
    PORT
      LAYER M4 ;
        RECT  0 26.256 0.084 26.28 ;
    END
  END o[257]
  PIN o[258]
    DIRECTION OUTPUT ;
    USE SIGNAL ;
    PORT
      LAYER M4 ;
        RECT  0 26.352 0.084 26.376 ;
    END
  END o[258]
  PIN o[259]
    DIRECTION OUTPUT ;
    USE SIGNAL ;
    PORT
      LAYER M4 ;
        RECT  0 26.448 0.084 26.472 ;
    END
  END o[259]
  PIN o[25]
    DIRECTION OUTPUT ;
    USE SIGNAL ;
    PORT
      LAYER M4 ;
        RECT  0 3.12 0.084 3.144 ;
    END
  END o[25]
  PIN o[260]
    DIRECTION OUTPUT ;
    USE SIGNAL ;
    PORT
      LAYER M4 ;
        RECT  0 26.544 0.084 26.568 ;
    END
  END o[260]
  PIN o[261]
    DIRECTION OUTPUT ;
    USE SIGNAL ;
    PORT
      LAYER M4 ;
        RECT  0 26.64 0.084 26.664 ;
    END
  END o[261]
  PIN o[262]
    DIRECTION OUTPUT ;
    USE SIGNAL ;
    PORT
      LAYER M4 ;
        RECT  0 26.736 0.084 26.76 ;
    END
  END o[262]
  PIN o[263]
    DIRECTION OUTPUT ;
    USE SIGNAL ;
    PORT
      LAYER M4 ;
        RECT  0 26.832 0.084 26.856 ;
    END
  END o[263]
  PIN o[264]
    DIRECTION OUTPUT ;
    USE SIGNAL ;
    PORT
      LAYER M4 ;
        RECT  0 26.976 0.084 27 ;
    END
  END o[264]
  PIN o[265]
    DIRECTION OUTPUT ;
    USE SIGNAL ;
    PORT
      LAYER M4 ;
        RECT  0 27.072 0.084 27.096 ;
    END
  END o[265]
  PIN o[266]
    DIRECTION OUTPUT ;
    USE SIGNAL ;
    PORT
      LAYER M4 ;
        RECT  0 27.168 0.084 27.192 ;
    END
  END o[266]
  PIN o[267]
    DIRECTION OUTPUT ;
    USE SIGNAL ;
    PORT
      LAYER M4 ;
        RECT  0 27.264 0.084 27.288 ;
    END
  END o[267]
  PIN o[268]
    DIRECTION OUTPUT ;
    USE SIGNAL ;
    PORT
      LAYER M4 ;
        RECT  0 27.36 0.084 27.384 ;
    END
  END o[268]
  PIN o[269]
    DIRECTION OUTPUT ;
    USE SIGNAL ;
    PORT
      LAYER M4 ;
        RECT  0 27.456 0.084 27.48 ;
    END
  END o[269]
  PIN o[26]
    DIRECTION OUTPUT ;
    USE SIGNAL ;
    PORT
      LAYER M4 ;
        RECT  0 3.216 0.084 3.24 ;
    END
  END o[26]
  PIN o[270]
    DIRECTION OUTPUT ;
    USE SIGNAL ;
    PORT
      LAYER M4 ;
        RECT  0 27.552 0.084 27.576 ;
    END
  END o[270]
  PIN o[271]
    DIRECTION OUTPUT ;
    USE SIGNAL ;
    PORT
      LAYER M4 ;
        RECT  0 27.648 0.084 27.672 ;
    END
  END o[271]
  PIN o[272]
    DIRECTION OUTPUT ;
    USE SIGNAL ;
    PORT
      LAYER M4 ;
        RECT  0 27.744 0.084 27.768 ;
    END
  END o[272]
  PIN o[273]
    DIRECTION OUTPUT ;
    USE SIGNAL ;
    PORT
      LAYER M4 ;
        RECT  0 27.84 0.084 27.864 ;
    END
  END o[273]
  PIN o[274]
    DIRECTION OUTPUT ;
    USE SIGNAL ;
    PORT
      LAYER M4 ;
        RECT  0 27.936 0.084 27.96 ;
    END
  END o[274]
  PIN o[275]
    DIRECTION OUTPUT ;
    USE SIGNAL ;
    PORT
      LAYER M4 ;
        RECT  0 28.032 0.084 28.056 ;
    END
  END o[275]
  PIN o[276]
    DIRECTION OUTPUT ;
    USE SIGNAL ;
    PORT
      LAYER M4 ;
        RECT  0 28.128 0.084 28.152 ;
    END
  END o[276]
  PIN o[277]
    DIRECTION OUTPUT ;
    USE SIGNAL ;
    PORT
      LAYER M4 ;
        RECT  0 28.272 0.084 28.296 ;
    END
  END o[277]
  PIN o[278]
    DIRECTION OUTPUT ;
    USE SIGNAL ;
    PORT
      LAYER M4 ;
        RECT  0 28.368 0.084 28.392 ;
    END
  END o[278]
  PIN o[279]
    DIRECTION OUTPUT ;
    USE SIGNAL ;
    PORT
      LAYER M4 ;
        RECT  0 28.464 0.084 28.488 ;
    END
  END o[279]
  PIN o[27]
    DIRECTION OUTPUT ;
    USE SIGNAL ;
    PORT
      LAYER M4 ;
        RECT  0 3.312 0.084 3.336 ;
    END
  END o[27]
  PIN o[280]
    DIRECTION OUTPUT ;
    USE SIGNAL ;
    PORT
      LAYER M4 ;
        RECT  0 28.56 0.084 28.584 ;
    END
  END o[280]
  PIN o[281]
    DIRECTION OUTPUT ;
    USE SIGNAL ;
    PORT
      LAYER M4 ;
        RECT  0 28.656 0.084 28.68 ;
    END
  END o[281]
  PIN o[282]
    DIRECTION OUTPUT ;
    USE SIGNAL ;
    PORT
      LAYER M4 ;
        RECT  0 28.752 0.084 28.776 ;
    END
  END o[282]
  PIN o[283]
    DIRECTION OUTPUT ;
    USE SIGNAL ;
    PORT
      LAYER M4 ;
        RECT  0 28.848 0.084 28.872 ;
    END
  END o[283]
  PIN o[284]
    DIRECTION OUTPUT ;
    USE SIGNAL ;
    PORT
      LAYER M4 ;
        RECT  0 28.944 0.084 28.968 ;
    END
  END o[284]
  PIN o[285]
    DIRECTION OUTPUT ;
    USE SIGNAL ;
    PORT
      LAYER M4 ;
        RECT  0 29.04 0.084 29.064 ;
    END
  END o[285]
  PIN o[286]
    DIRECTION OUTPUT ;
    USE SIGNAL ;
    PORT
      LAYER M4 ;
        RECT  0 29.136 0.084 29.16 ;
    END
  END o[286]
  PIN o[287]
    DIRECTION OUTPUT ;
    USE SIGNAL ;
    PORT
      LAYER M4 ;
        RECT  0 29.232 0.084 29.256 ;
    END
  END o[287]
  PIN o[288]
    DIRECTION OUTPUT ;
    USE SIGNAL ;
    PORT
      LAYER M4 ;
        RECT  0 29.328 0.084 29.352 ;
    END
  END o[288]
  PIN o[289]
    DIRECTION OUTPUT ;
    USE SIGNAL ;
    PORT
      LAYER M4 ;
        RECT  0 29.424 0.084 29.448 ;
    END
  END o[289]
  PIN o[28]
    DIRECTION OUTPUT ;
    USE SIGNAL ;
    PORT
      LAYER M4 ;
        RECT  0 3.408 0.084 3.432 ;
    END
  END o[28]
  PIN o[290]
    DIRECTION OUTPUT ;
    USE SIGNAL ;
    PORT
      LAYER M4 ;
        RECT  0 29.568 0.084 29.592 ;
    END
  END o[290]
  PIN o[291]
    DIRECTION OUTPUT ;
    USE SIGNAL ;
    PORT
      LAYER M4 ;
        RECT  0 29.664 0.084 29.688 ;
    END
  END o[291]
  PIN o[292]
    DIRECTION OUTPUT ;
    USE SIGNAL ;
    PORT
      LAYER M4 ;
        RECT  0 29.76 0.084 29.784 ;
    END
  END o[292]
  PIN o[293]
    DIRECTION OUTPUT ;
    USE SIGNAL ;
    PORT
      LAYER M4 ;
        RECT  0 29.856 0.084 29.88 ;
    END
  END o[293]
  PIN o[294]
    DIRECTION OUTPUT ;
    USE SIGNAL ;
    PORT
      LAYER M4 ;
        RECT  0 29.952 0.084 29.976 ;
    END
  END o[294]
  PIN o[295]
    DIRECTION OUTPUT ;
    USE SIGNAL ;
    PORT
      LAYER M4 ;
        RECT  0 30.048 0.084 30.072 ;
    END
  END o[295]
  PIN o[296]
    DIRECTION OUTPUT ;
    USE SIGNAL ;
    PORT
      LAYER M4 ;
        RECT  0 30.144 0.084 30.168 ;
    END
  END o[296]
  PIN o[297]
    DIRECTION OUTPUT ;
    USE SIGNAL ;
    PORT
      LAYER M4 ;
        RECT  0 30.24 0.084 30.264 ;
    END
  END o[297]
  PIN o[298]
    DIRECTION OUTPUT ;
    USE SIGNAL ;
    PORT
      LAYER M4 ;
        RECT  0 30.336 0.084 30.36 ;
    END
  END o[298]
  PIN o[299]
    DIRECTION OUTPUT ;
    USE SIGNAL ;
    PORT
      LAYER M4 ;
        RECT  0 30.432 0.084 30.456 ;
    END
  END o[299]
  PIN o[29]
    DIRECTION OUTPUT ;
    USE SIGNAL ;
    PORT
      LAYER M4 ;
        RECT  0 3.552 0.084 3.576 ;
    END
  END o[29]
  PIN o[2]
    DIRECTION OUTPUT ;
    USE SIGNAL ;
    PORT
      LAYER M4 ;
        RECT  0 0.816 0.084 0.84 ;
    END
  END o[2]
  PIN o[300]
    DIRECTION OUTPUT ;
    USE SIGNAL ;
    PORT
      LAYER M4 ;
        RECT  0 30.528 0.084 30.552 ;
    END
  END o[300]
  PIN o[301]
    DIRECTION OUTPUT ;
    USE SIGNAL ;
    PORT
      LAYER M4 ;
        RECT  0 30.624 0.084 30.648 ;
    END
  END o[301]
  PIN o[302]
    DIRECTION OUTPUT ;
    USE SIGNAL ;
    PORT
      LAYER M4 ;
        RECT  0 30.72 0.084 30.744 ;
    END
  END o[302]
  PIN o[303]
    DIRECTION OUTPUT ;
    USE SIGNAL ;
    PORT
      LAYER M4 ;
        RECT  0 30.864 0.084 30.888 ;
    END
  END o[303]
  PIN o[304]
    DIRECTION OUTPUT ;
    USE SIGNAL ;
    PORT
      LAYER M4 ;
        RECT  0 30.96 0.084 30.984 ;
    END
  END o[304]
  PIN o[305]
    DIRECTION OUTPUT ;
    USE SIGNAL ;
    PORT
      LAYER M4 ;
        RECT  0 31.056 0.084 31.08 ;
    END
  END o[305]
  PIN o[306]
    DIRECTION OUTPUT ;
    USE SIGNAL ;
    PORT
      LAYER M4 ;
        RECT  0 31.152 0.084 31.176 ;
    END
  END o[306]
  PIN o[307]
    DIRECTION OUTPUT ;
    USE SIGNAL ;
    PORT
      LAYER M4 ;
        RECT  0 31.248 0.084 31.272 ;
    END
  END o[307]
  PIN o[308]
    DIRECTION OUTPUT ;
    USE SIGNAL ;
    PORT
      LAYER M4 ;
        RECT  0 31.344 0.084 31.368 ;
    END
  END o[308]
  PIN o[309]
    DIRECTION OUTPUT ;
    USE SIGNAL ;
    PORT
      LAYER M4 ;
        RECT  0 31.44 0.084 31.464 ;
    END
  END o[309]
  PIN o[30]
    DIRECTION OUTPUT ;
    USE SIGNAL ;
    PORT
      LAYER M4 ;
        RECT  0 3.648 0.084 3.672 ;
    END
  END o[30]
  PIN o[310]
    DIRECTION OUTPUT ;
    USE SIGNAL ;
    PORT
      LAYER M4 ;
        RECT  0 31.536 0.084 31.56 ;
    END
  END o[310]
  PIN o[311]
    DIRECTION OUTPUT ;
    USE SIGNAL ;
    PORT
      LAYER M4 ;
        RECT  0 31.632 0.084 31.656 ;
    END
  END o[311]
  PIN o[312]
    DIRECTION OUTPUT ;
    USE SIGNAL ;
    PORT
      LAYER M4 ;
        RECT  0 31.728 0.084 31.752 ;
    END
  END o[312]
  PIN o[313]
    DIRECTION OUTPUT ;
    USE SIGNAL ;
    PORT
      LAYER M4 ;
        RECT  0 31.824 0.084 31.848 ;
    END
  END o[313]
  PIN o[314]
    DIRECTION OUTPUT ;
    USE SIGNAL ;
    PORT
      LAYER M4 ;
        RECT  0 31.92 0.084 31.944 ;
    END
  END o[314]
  PIN o[315]
    DIRECTION OUTPUT ;
    USE SIGNAL ;
    PORT
      LAYER M4 ;
        RECT  0 32.016 0.084 32.04 ;
    END
  END o[315]
  PIN o[316]
    DIRECTION OUTPUT ;
    USE SIGNAL ;
    PORT
      LAYER M4 ;
        RECT  0 32.16 0.084 32.184 ;
    END
  END o[316]
  PIN o[317]
    DIRECTION OUTPUT ;
    USE SIGNAL ;
    PORT
      LAYER M4 ;
        RECT  0 32.256 0.084 32.28 ;
    END
  END o[317]
  PIN o[318]
    DIRECTION OUTPUT ;
    USE SIGNAL ;
    PORT
      LAYER M4 ;
        RECT  0 32.352 0.084 32.376 ;
    END
  END o[318]
  PIN o[319]
    DIRECTION OUTPUT ;
    USE SIGNAL ;
    PORT
      LAYER M4 ;
        RECT  0 32.448 0.084 32.472 ;
    END
  END o[319]
  PIN o[31]
    DIRECTION OUTPUT ;
    USE SIGNAL ;
    PORT
      LAYER M4 ;
        RECT  0 3.744 0.084 3.768 ;
    END
  END o[31]
  PIN o[320]
    DIRECTION OUTPUT ;
    USE SIGNAL ;
    PORT
      LAYER M4 ;
        RECT  0 32.544 0.084 32.568 ;
    END
  END o[320]
  PIN o[321]
    DIRECTION OUTPUT ;
    USE SIGNAL ;
    PORT
      LAYER M4 ;
        RECT  0 32.64 0.084 32.664 ;
    END
  END o[321]
  PIN o[322]
    DIRECTION OUTPUT ;
    USE SIGNAL ;
    PORT
      LAYER M4 ;
        RECT  0 32.736 0.084 32.76 ;
    END
  END o[322]
  PIN o[323]
    DIRECTION OUTPUT ;
    USE SIGNAL ;
    PORT
      LAYER M4 ;
        RECT  0 32.832 0.084 32.856 ;
    END
  END o[323]
  PIN o[324]
    DIRECTION OUTPUT ;
    USE SIGNAL ;
    PORT
      LAYER M4 ;
        RECT  0 32.928 0.084 32.952 ;
    END
  END o[324]
  PIN o[325]
    DIRECTION OUTPUT ;
    USE SIGNAL ;
    PORT
      LAYER M4 ;
        RECT  0 33.024 0.084 33.048 ;
    END
  END o[325]
  PIN o[326]
    DIRECTION OUTPUT ;
    USE SIGNAL ;
    PORT
      LAYER M4 ;
        RECT  0 33.12 0.084 33.144 ;
    END
  END o[326]
  PIN o[327]
    DIRECTION OUTPUT ;
    USE SIGNAL ;
    PORT
      LAYER M4 ;
        RECT  0 33.216 0.084 33.24 ;
    END
  END o[327]
  PIN o[328]
    DIRECTION OUTPUT ;
    USE SIGNAL ;
    PORT
      LAYER M4 ;
        RECT  0 33.312 0.084 33.336 ;
    END
  END o[328]
  PIN o[329]
    DIRECTION OUTPUT ;
    USE SIGNAL ;
    PORT
      LAYER M4 ;
        RECT  0 33.456 0.084 33.48 ;
    END
  END o[329]
  PIN o[32]
    DIRECTION OUTPUT ;
    USE SIGNAL ;
    PORT
      LAYER M4 ;
        RECT  0 3.84 0.084 3.864 ;
    END
  END o[32]
  PIN o[330]
    DIRECTION OUTPUT ;
    USE SIGNAL ;
    PORT
      LAYER M4 ;
        RECT  0 33.552 0.084 33.576 ;
    END
  END o[330]
  PIN o[331]
    DIRECTION OUTPUT ;
    USE SIGNAL ;
    PORT
      LAYER M4 ;
        RECT  0 33.648 0.084 33.672 ;
    END
  END o[331]
  PIN o[332]
    DIRECTION OUTPUT ;
    USE SIGNAL ;
    PORT
      LAYER M4 ;
        RECT  0 33.744 0.084 33.768 ;
    END
  END o[332]
  PIN o[333]
    DIRECTION OUTPUT ;
    USE SIGNAL ;
    PORT
      LAYER M4 ;
        RECT  0 33.84 0.084 33.864 ;
    END
  END o[333]
  PIN o[334]
    DIRECTION OUTPUT ;
    USE SIGNAL ;
    PORT
      LAYER M4 ;
        RECT  0 33.936 0.084 33.96 ;
    END
  END o[334]
  PIN o[335]
    DIRECTION OUTPUT ;
    USE SIGNAL ;
    PORT
      LAYER M4 ;
        RECT  0 34.032 0.084 34.056 ;
    END
  END o[335]
  PIN o[336]
    DIRECTION OUTPUT ;
    USE SIGNAL ;
    PORT
      LAYER M4 ;
        RECT  0 34.128 0.084 34.152 ;
    END
  END o[336]
  PIN o[337]
    DIRECTION OUTPUT ;
    USE SIGNAL ;
    PORT
      LAYER M4 ;
        RECT  0 34.224 0.084 34.248 ;
    END
  END o[337]
  PIN o[338]
    DIRECTION OUTPUT ;
    USE SIGNAL ;
    PORT
      LAYER M4 ;
        RECT  0 34.32 0.084 34.344 ;
    END
  END o[338]
  PIN o[339]
    DIRECTION OUTPUT ;
    USE SIGNAL ;
    PORT
      LAYER M4 ;
        RECT  0 34.416 0.084 34.44 ;
    END
  END o[339]
  PIN o[33]
    DIRECTION OUTPUT ;
    USE SIGNAL ;
    PORT
      LAYER M4 ;
        RECT  0 3.936 0.084 3.96 ;
    END
  END o[33]
  PIN o[340]
    DIRECTION OUTPUT ;
    USE SIGNAL ;
    PORT
      LAYER M4 ;
        RECT  0 34.512 0.084 34.536 ;
    END
  END o[340]
  PIN o[341]
    DIRECTION OUTPUT ;
    USE SIGNAL ;
    PORT
      LAYER M4 ;
        RECT  0 34.608 0.084 34.632 ;
    END
  END o[341]
  PIN o[342]
    DIRECTION OUTPUT ;
    USE SIGNAL ;
    PORT
      LAYER M4 ;
        RECT  0 34.752 0.084 34.776 ;
    END
  END o[342]
  PIN o[343]
    DIRECTION OUTPUT ;
    USE SIGNAL ;
    PORT
      LAYER M4 ;
        RECT  0 34.848 0.084 34.872 ;
    END
  END o[343]
  PIN o[344]
    DIRECTION OUTPUT ;
    USE SIGNAL ;
    PORT
      LAYER M4 ;
        RECT  0 34.944 0.084 34.968 ;
    END
  END o[344]
  PIN o[345]
    DIRECTION OUTPUT ;
    USE SIGNAL ;
    PORT
      LAYER M4 ;
        RECT  0 35.04 0.084 35.064 ;
    END
  END o[345]
  PIN o[346]
    DIRECTION OUTPUT ;
    USE SIGNAL ;
    PORT
      LAYER M4 ;
        RECT  0 35.136 0.084 35.16 ;
    END
  END o[346]
  PIN o[347]
    DIRECTION OUTPUT ;
    USE SIGNAL ;
    PORT
      LAYER M4 ;
        RECT  0 35.232 0.084 35.256 ;
    END
  END o[347]
  PIN o[348]
    DIRECTION OUTPUT ;
    USE SIGNAL ;
    PORT
      LAYER M4 ;
        RECT  0 35.328 0.084 35.352 ;
    END
  END o[348]
  PIN o[349]
    DIRECTION OUTPUT ;
    USE SIGNAL ;
    PORT
      LAYER M4 ;
        RECT  0 35.424 0.084 35.448 ;
    END
  END o[349]
  PIN o[34]
    DIRECTION OUTPUT ;
    USE SIGNAL ;
    PORT
      LAYER M4 ;
        RECT  0 4.032 0.084 4.056 ;
    END
  END o[34]
  PIN o[350]
    DIRECTION OUTPUT ;
    USE SIGNAL ;
    PORT
      LAYER M4 ;
        RECT  0 35.52 0.084 35.544 ;
    END
  END o[350]
  PIN o[351]
    DIRECTION OUTPUT ;
    USE SIGNAL ;
    PORT
      LAYER M4 ;
        RECT  0 35.616 0.084 35.64 ;
    END
  END o[351]
  PIN o[352]
    DIRECTION OUTPUT ;
    USE SIGNAL ;
    PORT
      LAYER M4 ;
        RECT  0 35.712 0.084 35.736 ;
    END
  END o[352]
  PIN o[353]
    DIRECTION OUTPUT ;
    USE SIGNAL ;
    PORT
      LAYER M4 ;
        RECT  0 35.808 0.084 35.832 ;
    END
  END o[353]
  PIN o[354]
    DIRECTION OUTPUT ;
    USE SIGNAL ;
    PORT
      LAYER M4 ;
        RECT  0 35.904 0.084 35.928 ;
    END
  END o[354]
  PIN o[355]
    DIRECTION OUTPUT ;
    USE SIGNAL ;
    PORT
      LAYER M4 ;
        RECT  0 36.048 0.084 36.072 ;
    END
  END o[355]
  PIN o[356]
    DIRECTION OUTPUT ;
    USE SIGNAL ;
    PORT
      LAYER M4 ;
        RECT  0 36.144 0.084 36.168 ;
    END
  END o[356]
  PIN o[357]
    DIRECTION OUTPUT ;
    USE SIGNAL ;
    PORT
      LAYER M4 ;
        RECT  0 36.24 0.084 36.264 ;
    END
  END o[357]
  PIN o[358]
    DIRECTION OUTPUT ;
    USE SIGNAL ;
    PORT
      LAYER M4 ;
        RECT  0 36.336 0.084 36.36 ;
    END
  END o[358]
  PIN o[359]
    DIRECTION OUTPUT ;
    USE SIGNAL ;
    PORT
      LAYER M4 ;
        RECT  0 36.432 0.084 36.456 ;
    END
  END o[359]
  PIN o[35]
    DIRECTION OUTPUT ;
    USE SIGNAL ;
    PORT
      LAYER M4 ;
        RECT  0 4.128 0.084 4.152 ;
    END
  END o[35]
  PIN o[360]
    DIRECTION OUTPUT ;
    USE SIGNAL ;
    PORT
      LAYER M4 ;
        RECT  0 36.528 0.084 36.552 ;
    END
  END o[360]
  PIN o[361]
    DIRECTION OUTPUT ;
    USE SIGNAL ;
    PORT
      LAYER M4 ;
        RECT  0 36.624 0.084 36.648 ;
    END
  END o[361]
  PIN o[362]
    DIRECTION OUTPUT ;
    USE SIGNAL ;
    PORT
      LAYER M4 ;
        RECT  0 36.72 0.084 36.744 ;
    END
  END o[362]
  PIN o[363]
    DIRECTION OUTPUT ;
    USE SIGNAL ;
    PORT
      LAYER M4 ;
        RECT  0 36.816 0.084 36.84 ;
    END
  END o[363]
  PIN o[364]
    DIRECTION OUTPUT ;
    USE SIGNAL ;
    PORT
      LAYER M4 ;
        RECT  0 36.912 0.084 36.936 ;
    END
  END o[364]
  PIN o[365]
    DIRECTION OUTPUT ;
    USE SIGNAL ;
    PORT
      LAYER M4 ;
        RECT  0 37.008 0.084 37.032 ;
    END
  END o[365]
  PIN o[366]
    DIRECTION OUTPUT ;
    USE SIGNAL ;
    PORT
      LAYER M4 ;
        RECT  0 37.104 0.084 37.128 ;
    END
  END o[366]
  PIN o[367]
    DIRECTION OUTPUT ;
    USE SIGNAL ;
    PORT
      LAYER M4 ;
        RECT  0 37.2 0.084 37.224 ;
    END
  END o[367]
  PIN o[368]
    DIRECTION OUTPUT ;
    USE SIGNAL ;
    PORT
      LAYER M4 ;
        RECT  0 37.344 0.084 37.368 ;
    END
  END o[368]
  PIN o[369]
    DIRECTION OUTPUT ;
    USE SIGNAL ;
    PORT
      LAYER M4 ;
        RECT  0 37.44 0.084 37.464 ;
    END
  END o[369]
  PIN o[36]
    DIRECTION OUTPUT ;
    USE SIGNAL ;
    PORT
      LAYER M4 ;
        RECT  0 4.224 0.084 4.248 ;
    END
  END o[36]
  PIN o[370]
    DIRECTION OUTPUT ;
    USE SIGNAL ;
    PORT
      LAYER M4 ;
        RECT  0 37.536 0.084 37.56 ;
    END
  END o[370]
  PIN o[371]
    DIRECTION OUTPUT ;
    USE SIGNAL ;
    PORT
      LAYER M4 ;
        RECT  0 37.632 0.084 37.656 ;
    END
  END o[371]
  PIN o[372]
    DIRECTION OUTPUT ;
    USE SIGNAL ;
    PORT
      LAYER M4 ;
        RECT  0 37.728 0.084 37.752 ;
    END
  END o[372]
  PIN o[373]
    DIRECTION OUTPUT ;
    USE SIGNAL ;
    PORT
      LAYER M4 ;
        RECT  0 37.824 0.084 37.848 ;
    END
  END o[373]
  PIN o[374]
    DIRECTION OUTPUT ;
    USE SIGNAL ;
    PORT
      LAYER M4 ;
        RECT  0 37.92 0.084 37.944 ;
    END
  END o[374]
  PIN o[375]
    DIRECTION OUTPUT ;
    USE SIGNAL ;
    PORT
      LAYER M4 ;
        RECT  0 38.016 0.084 38.04 ;
    END
  END o[375]
  PIN o[376]
    DIRECTION OUTPUT ;
    USE SIGNAL ;
    PORT
      LAYER M4 ;
        RECT  0 38.112 0.084 38.136 ;
    END
  END o[376]
  PIN o[377]
    DIRECTION OUTPUT ;
    USE SIGNAL ;
    PORT
      LAYER M4 ;
        RECT  0 38.208 0.084 38.232 ;
    END
  END o[377]
  PIN o[378]
    DIRECTION OUTPUT ;
    USE SIGNAL ;
    PORT
      LAYER M4 ;
        RECT  0 38.304 0.084 38.328 ;
    END
  END o[378]
  PIN o[379]
    DIRECTION OUTPUT ;
    USE SIGNAL ;
    PORT
      LAYER M4 ;
        RECT  0 38.4 0.084 38.424 ;
    END
  END o[379]
  PIN o[37]
    DIRECTION OUTPUT ;
    USE SIGNAL ;
    PORT
      LAYER M4 ;
        RECT  0 4.32 0.084 4.344 ;
    END
  END o[37]
  PIN o[380]
    DIRECTION OUTPUT ;
    USE SIGNAL ;
    PORT
      LAYER M4 ;
        RECT  0 38.496 0.084 38.52 ;
    END
  END o[380]
  PIN o[381]
    DIRECTION OUTPUT ;
    USE SIGNAL ;
    PORT
      LAYER M4 ;
        RECT  0 38.64 0.084 38.664 ;
    END
  END o[381]
  PIN o[382]
    DIRECTION OUTPUT ;
    USE SIGNAL ;
    PORT
      LAYER M4 ;
        RECT  0 38.736 0.084 38.76 ;
    END
  END o[382]
  PIN o[383]
    DIRECTION OUTPUT ;
    USE SIGNAL ;
    PORT
      LAYER M4 ;
        RECT  0 38.832 0.084 38.856 ;
    END
  END o[383]
  PIN o[384]
    DIRECTION OUTPUT ;
    USE SIGNAL ;
    PORT
      LAYER M4 ;
        RECT  0 38.928 0.084 38.952 ;
    END
  END o[384]
  PIN o[385]
    DIRECTION OUTPUT ;
    USE SIGNAL ;
    PORT
      LAYER M4 ;
        RECT  0 39.024 0.084 39.048 ;
    END
  END o[385]
  PIN o[386]
    DIRECTION OUTPUT ;
    USE SIGNAL ;
    PORT
      LAYER M4 ;
        RECT  0 39.12 0.084 39.144 ;
    END
  END o[386]
  PIN o[387]
    DIRECTION OUTPUT ;
    USE SIGNAL ;
    PORT
      LAYER M4 ;
        RECT  0 39.216 0.084 39.24 ;
    END
  END o[387]
  PIN o[388]
    DIRECTION OUTPUT ;
    USE SIGNAL ;
    PORT
      LAYER M4 ;
        RECT  0 39.312 0.084 39.336 ;
    END
  END o[388]
  PIN o[389]
    DIRECTION OUTPUT ;
    USE SIGNAL ;
    PORT
      LAYER M4 ;
        RECT  0 39.408 0.084 39.432 ;
    END
  END o[389]
  PIN o[38]
    DIRECTION OUTPUT ;
    USE SIGNAL ;
    PORT
      LAYER M4 ;
        RECT  0 4.416 0.084 4.44 ;
    END
  END o[38]
  PIN o[390]
    DIRECTION OUTPUT ;
    USE SIGNAL ;
    PORT
      LAYER M4 ;
        RECT  0 39.504 0.084 39.528 ;
    END
  END o[390]
  PIN o[391]
    DIRECTION OUTPUT ;
    USE SIGNAL ;
    PORT
      LAYER M4 ;
        RECT  0 39.6 0.084 39.624 ;
    END
  END o[391]
  PIN o[392]
    DIRECTION OUTPUT ;
    USE SIGNAL ;
    PORT
      LAYER M4 ;
        RECT  0 39.696 0.084 39.72 ;
    END
  END o[392]
  PIN o[393]
    DIRECTION OUTPUT ;
    USE SIGNAL ;
    PORT
      LAYER M4 ;
        RECT  0 39.792 0.084 39.816 ;
    END
  END o[393]
  PIN o[394]
    DIRECTION OUTPUT ;
    USE SIGNAL ;
    PORT
      LAYER M4 ;
        RECT  0 39.936 0.084 39.96 ;
    END
  END o[394]
  PIN o[395]
    DIRECTION OUTPUT ;
    USE SIGNAL ;
    PORT
      LAYER M4 ;
        RECT  0 40.032 0.084 40.056 ;
    END
  END o[395]
  PIN o[396]
    DIRECTION OUTPUT ;
    USE SIGNAL ;
    PORT
      LAYER M4 ;
        RECT  0 40.128 0.084 40.152 ;
    END
  END o[396]
  PIN o[397]
    DIRECTION OUTPUT ;
    USE SIGNAL ;
    PORT
      LAYER M4 ;
        RECT  0 40.224 0.084 40.248 ;
    END
  END o[397]
  PIN o[398]
    DIRECTION OUTPUT ;
    USE SIGNAL ;
    PORT
      LAYER M4 ;
        RECT  0 40.32 0.084 40.344 ;
    END
  END o[398]
  PIN o[399]
    DIRECTION OUTPUT ;
    USE SIGNAL ;
    PORT
      LAYER M4 ;
        RECT  0 40.416 0.084 40.44 ;
    END
  END o[399]
  PIN o[39]
    DIRECTION OUTPUT ;
    USE SIGNAL ;
    PORT
      LAYER M4 ;
        RECT  0 4.512 0.084 4.536 ;
    END
  END o[39]
  PIN o[3]
    DIRECTION OUTPUT ;
    USE SIGNAL ;
    PORT
      LAYER M4 ;
        RECT  0 0.96 0.084 0.984 ;
    END
  END o[3]
  PIN o[400]
    DIRECTION OUTPUT ;
    USE SIGNAL ;
    PORT
      LAYER M4 ;
        RECT  0 40.512 0.084 40.536 ;
    END
  END o[400]
  PIN o[401]
    DIRECTION OUTPUT ;
    USE SIGNAL ;
    PORT
      LAYER M4 ;
        RECT  0 40.608 0.084 40.632 ;
    END
  END o[401]
  PIN o[402]
    DIRECTION OUTPUT ;
    USE SIGNAL ;
    PORT
      LAYER M4 ;
        RECT  0 40.704 0.084 40.728 ;
    END
  END o[402]
  PIN o[403]
    DIRECTION OUTPUT ;
    USE SIGNAL ;
    PORT
      LAYER M4 ;
        RECT  0 40.8 0.084 40.824 ;
    END
  END o[403]
  PIN o[404]
    DIRECTION OUTPUT ;
    USE SIGNAL ;
    PORT
      LAYER M4 ;
        RECT  0 40.896 0.084 40.92 ;
    END
  END o[404]
  PIN o[405]
    DIRECTION OUTPUT ;
    USE SIGNAL ;
    PORT
      LAYER M4 ;
        RECT  0 40.992 0.084 41.016 ;
    END
  END o[405]
  PIN o[406]
    DIRECTION OUTPUT ;
    USE SIGNAL ;
    PORT
      LAYER M4 ;
        RECT  0 41.088 0.084 41.112 ;
    END
  END o[406]
  PIN o[407]
    DIRECTION OUTPUT ;
    USE SIGNAL ;
    PORT
      LAYER M4 ;
        RECT  0 41.184 0.084 41.208 ;
    END
  END o[407]
  PIN o[408]
    DIRECTION OUTPUT ;
    USE SIGNAL ;
    PORT
      LAYER M4 ;
        RECT  0 41.328 0.084 41.352 ;
    END
  END o[408]
  PIN o[409]
    DIRECTION OUTPUT ;
    USE SIGNAL ;
    PORT
      LAYER M4 ;
        RECT  0 41.424 0.084 41.448 ;
    END
  END o[409]
  PIN o[40]
    DIRECTION OUTPUT ;
    USE SIGNAL ;
    PORT
      LAYER M4 ;
        RECT  0 4.608 0.084 4.632 ;
    END
  END o[40]
  PIN o[410]
    DIRECTION OUTPUT ;
    USE SIGNAL ;
    PORT
      LAYER M4 ;
        RECT  0 41.52 0.084 41.544 ;
    END
  END o[410]
  PIN o[411]
    DIRECTION OUTPUT ;
    USE SIGNAL ;
    PORT
      LAYER M4 ;
        RECT  0 41.616 0.084 41.64 ;
    END
  END o[411]
  PIN o[412]
    DIRECTION OUTPUT ;
    USE SIGNAL ;
    PORT
      LAYER M4 ;
        RECT  0 41.712 0.084 41.736 ;
    END
  END o[412]
  PIN o[413]
    DIRECTION OUTPUT ;
    USE SIGNAL ;
    PORT
      LAYER M4 ;
        RECT  0 41.808 0.084 41.832 ;
    END
  END o[413]
  PIN o[414]
    DIRECTION OUTPUT ;
    USE SIGNAL ;
    PORT
      LAYER M4 ;
        RECT  0 41.904 0.084 41.928 ;
    END
  END o[414]
  PIN o[415]
    DIRECTION OUTPUT ;
    USE SIGNAL ;
    PORT
      LAYER M4 ;
        RECT  0 42 0.084 42.024 ;
    END
  END o[415]
  PIN o[416]
    DIRECTION OUTPUT ;
    USE SIGNAL ;
    PORT
      LAYER M4 ;
        RECT  0 42.096 0.084 42.12 ;
    END
  END o[416]
  PIN o[417]
    DIRECTION OUTPUT ;
    USE SIGNAL ;
    PORT
      LAYER M4 ;
        RECT  0 42.192 0.084 42.216 ;
    END
  END o[417]
  PIN o[418]
    DIRECTION OUTPUT ;
    USE SIGNAL ;
    PORT
      LAYER M4 ;
        RECT  0 42.288 0.084 42.312 ;
    END
  END o[418]
  PIN o[419]
    DIRECTION OUTPUT ;
    USE SIGNAL ;
    PORT
      LAYER M4 ;
        RECT  0 42.384 0.084 42.408 ;
    END
  END o[419]
  PIN o[41]
    DIRECTION OUTPUT ;
    USE SIGNAL ;
    PORT
      LAYER M4 ;
        RECT  0 4.704 0.084 4.728 ;
    END
  END o[41]
  PIN o[420]
    DIRECTION OUTPUT ;
    USE SIGNAL ;
    PORT
      LAYER M4 ;
        RECT  0 42.48 0.084 42.504 ;
    END
  END o[420]
  PIN o[421]
    DIRECTION OUTPUT ;
    USE SIGNAL ;
    PORT
      LAYER M4 ;
        RECT  0 42.624 0.084 42.648 ;
    END
  END o[421]
  PIN o[422]
    DIRECTION OUTPUT ;
    USE SIGNAL ;
    PORT
      LAYER M4 ;
        RECT  0 42.72 0.084 42.744 ;
    END
  END o[422]
  PIN o[423]
    DIRECTION OUTPUT ;
    USE SIGNAL ;
    PORT
      LAYER M4 ;
        RECT  0 42.816 0.084 42.84 ;
    END
  END o[423]
  PIN o[424]
    DIRECTION OUTPUT ;
    USE SIGNAL ;
    PORT
      LAYER M4 ;
        RECT  0 42.912 0.084 42.936 ;
    END
  END o[424]
  PIN o[425]
    DIRECTION OUTPUT ;
    USE SIGNAL ;
    PORT
      LAYER M4 ;
        RECT  0 43.008 0.084 43.032 ;
    END
  END o[425]
  PIN o[426]
    DIRECTION OUTPUT ;
    USE SIGNAL ;
    PORT
      LAYER M4 ;
        RECT  0 43.104 0.084 43.128 ;
    END
  END o[426]
  PIN o[427]
    DIRECTION OUTPUT ;
    USE SIGNAL ;
    PORT
      LAYER M4 ;
        RECT  0 43.2 0.084 43.224 ;
    END
  END o[427]
  PIN o[428]
    DIRECTION OUTPUT ;
    USE SIGNAL ;
    PORT
      LAYER M4 ;
        RECT  0 43.296 0.084 43.32 ;
    END
  END o[428]
  PIN o[429]
    DIRECTION OUTPUT ;
    USE SIGNAL ;
    PORT
      LAYER M4 ;
        RECT  0 43.392 0.084 43.416 ;
    END
  END o[429]
  PIN o[42]
    DIRECTION OUTPUT ;
    USE SIGNAL ;
    PORT
      LAYER M4 ;
        RECT  0 4.848 0.084 4.872 ;
    END
  END o[42]
  PIN o[430]
    DIRECTION OUTPUT ;
    USE SIGNAL ;
    PORT
      LAYER M4 ;
        RECT  0 43.488 0.084 43.512 ;
    END
  END o[430]
  PIN o[431]
    DIRECTION OUTPUT ;
    USE SIGNAL ;
    PORT
      LAYER M4 ;
        RECT  0 43.584 0.084 43.608 ;
    END
  END o[431]
  PIN o[432]
    DIRECTION OUTPUT ;
    USE SIGNAL ;
    PORT
      LAYER M4 ;
        RECT  0 43.68 0.084 43.704 ;
    END
  END o[432]
  PIN o[433]
    DIRECTION OUTPUT ;
    USE SIGNAL ;
    PORT
      LAYER M4 ;
        RECT  0 43.776 0.084 43.8 ;
    END
  END o[433]
  PIN o[434]
    DIRECTION OUTPUT ;
    USE SIGNAL ;
    PORT
      LAYER M4 ;
        RECT  0 43.92 0.084 43.944 ;
    END
  END o[434]
  PIN o[435]
    DIRECTION OUTPUT ;
    USE SIGNAL ;
    PORT
      LAYER M4 ;
        RECT  0 44.016 0.084 44.04 ;
    END
  END o[435]
  PIN o[436]
    DIRECTION OUTPUT ;
    USE SIGNAL ;
    PORT
      LAYER M4 ;
        RECT  0 44.112 0.084 44.136 ;
    END
  END o[436]
  PIN o[437]
    DIRECTION OUTPUT ;
    USE SIGNAL ;
    PORT
      LAYER M4 ;
        RECT  0 44.208 0.084 44.232 ;
    END
  END o[437]
  PIN o[438]
    DIRECTION OUTPUT ;
    USE SIGNAL ;
    PORT
      LAYER M4 ;
        RECT  0 44.304 0.084 44.328 ;
    END
  END o[438]
  PIN o[439]
    DIRECTION OUTPUT ;
    USE SIGNAL ;
    PORT
      LAYER M4 ;
        RECT  0 44.4 0.084 44.424 ;
    END
  END o[439]
  PIN o[43]
    DIRECTION OUTPUT ;
    USE SIGNAL ;
    PORT
      LAYER M4 ;
        RECT  0 4.944 0.084 4.968 ;
    END
  END o[43]
  PIN o[440]
    DIRECTION OUTPUT ;
    USE SIGNAL ;
    PORT
      LAYER M4 ;
        RECT  0 44.496 0.084 44.52 ;
    END
  END o[440]
  PIN o[441]
    DIRECTION OUTPUT ;
    USE SIGNAL ;
    PORT
      LAYER M4 ;
        RECT  0 44.592 0.084 44.616 ;
    END
  END o[441]
  PIN o[442]
    DIRECTION OUTPUT ;
    USE SIGNAL ;
    PORT
      LAYER M4 ;
        RECT  0 44.688 0.084 44.712 ;
    END
  END o[442]
  PIN o[443]
    DIRECTION OUTPUT ;
    USE SIGNAL ;
    PORT
      LAYER M4 ;
        RECT  0 44.784 0.084 44.808 ;
    END
  END o[443]
  PIN o[444]
    DIRECTION OUTPUT ;
    USE SIGNAL ;
    PORT
      LAYER M4 ;
        RECT  0 44.88 0.084 44.904 ;
    END
  END o[444]
  PIN o[445]
    DIRECTION OUTPUT ;
    USE SIGNAL ;
    PORT
      LAYER M4 ;
        RECT  0 44.976 0.084 45 ;
    END
  END o[445]
  PIN o[446]
    DIRECTION OUTPUT ;
    USE SIGNAL ;
    PORT
      LAYER M4 ;
        RECT  0 45.072 0.084 45.096 ;
    END
  END o[446]
  PIN o[447]
    DIRECTION OUTPUT ;
    USE SIGNAL ;
    PORT
      LAYER M4 ;
        RECT  0 45.216 0.084 45.24 ;
    END
  END o[447]
  PIN o[448]
    DIRECTION OUTPUT ;
    USE SIGNAL ;
    PORT
      LAYER M4 ;
        RECT  0 45.312 0.084 45.336 ;
    END
  END o[448]
  PIN o[449]
    DIRECTION OUTPUT ;
    USE SIGNAL ;
    PORT
      LAYER M4 ;
        RECT  0 45.408 0.084 45.432 ;
    END
  END o[449]
  PIN o[44]
    DIRECTION OUTPUT ;
    USE SIGNAL ;
    PORT
      LAYER M4 ;
        RECT  0 5.04 0.084 5.064 ;
    END
  END o[44]
  PIN o[450]
    DIRECTION OUTPUT ;
    USE SIGNAL ;
    PORT
      LAYER M4 ;
        RECT  0 45.504 0.084 45.528 ;
    END
  END o[450]
  PIN o[451]
    DIRECTION OUTPUT ;
    USE SIGNAL ;
    PORT
      LAYER M4 ;
        RECT  0 45.6 0.084 45.624 ;
    END
  END o[451]
  PIN o[452]
    DIRECTION OUTPUT ;
    USE SIGNAL ;
    PORT
      LAYER M4 ;
        RECT  0 45.696 0.084 45.72 ;
    END
  END o[452]
  PIN o[453]
    DIRECTION OUTPUT ;
    USE SIGNAL ;
    PORT
      LAYER M4 ;
        RECT  0 45.792 0.084 45.816 ;
    END
  END o[453]
  PIN o[454]
    DIRECTION OUTPUT ;
    USE SIGNAL ;
    PORT
      LAYER M4 ;
        RECT  0 45.888 0.084 45.912 ;
    END
  END o[454]
  PIN o[455]
    DIRECTION OUTPUT ;
    USE SIGNAL ;
    PORT
      LAYER M4 ;
        RECT  0 45.984 0.084 46.008 ;
    END
  END o[455]
  PIN o[456]
    DIRECTION OUTPUT ;
    USE SIGNAL ;
    PORT
      LAYER M4 ;
        RECT  0 46.08 0.084 46.104 ;
    END
  END o[456]
  PIN o[457]
    DIRECTION OUTPUT ;
    USE SIGNAL ;
    PORT
      LAYER M4 ;
        RECT  0 46.176 0.084 46.2 ;
    END
  END o[457]
  PIN o[458]
    DIRECTION OUTPUT ;
    USE SIGNAL ;
    PORT
      LAYER M4 ;
        RECT  0 46.272 0.084 46.296 ;
    END
  END o[458]
  PIN o[459]
    DIRECTION OUTPUT ;
    USE SIGNAL ;
    PORT
      LAYER M4 ;
        RECT  0 46.368 0.084 46.392 ;
    END
  END o[459]
  PIN o[45]
    DIRECTION OUTPUT ;
    USE SIGNAL ;
    PORT
      LAYER M4 ;
        RECT  0 5.136 0.084 5.16 ;
    END
  END o[45]
  PIN o[460]
    DIRECTION OUTPUT ;
    USE SIGNAL ;
    PORT
      LAYER M4 ;
        RECT  0 46.512 0.084 46.536 ;
    END
  END o[460]
  PIN o[461]
    DIRECTION OUTPUT ;
    USE SIGNAL ;
    PORT
      LAYER M4 ;
        RECT  0 46.608 0.084 46.632 ;
    END
  END o[461]
  PIN o[462]
    DIRECTION OUTPUT ;
    USE SIGNAL ;
    PORT
      LAYER M4 ;
        RECT  0 46.704 0.084 46.728 ;
    END
  END o[462]
  PIN o[463]
    DIRECTION OUTPUT ;
    USE SIGNAL ;
    PORT
      LAYER M4 ;
        RECT  0 46.8 0.084 46.824 ;
    END
  END o[463]
  PIN o[464]
    DIRECTION OUTPUT ;
    USE SIGNAL ;
    PORT
      LAYER M4 ;
        RECT  0 46.896 0.084 46.92 ;
    END
  END o[464]
  PIN o[465]
    DIRECTION OUTPUT ;
    USE SIGNAL ;
    PORT
      LAYER M4 ;
        RECT  0 46.992 0.084 47.016 ;
    END
  END o[465]
  PIN o[466]
    DIRECTION OUTPUT ;
    USE SIGNAL ;
    PORT
      LAYER M4 ;
        RECT  0 47.088 0.084 47.112 ;
    END
  END o[466]
  PIN o[467]
    DIRECTION OUTPUT ;
    USE SIGNAL ;
    PORT
      LAYER M4 ;
        RECT  0 47.184 0.084 47.208 ;
    END
  END o[467]
  PIN o[468]
    DIRECTION OUTPUT ;
    USE SIGNAL ;
    PORT
      LAYER M4 ;
        RECT  0 47.28 0.084 47.304 ;
    END
  END o[468]
  PIN o[469]
    DIRECTION OUTPUT ;
    USE SIGNAL ;
    PORT
      LAYER M4 ;
        RECT  0 47.376 0.084 47.4 ;
    END
  END o[469]
  PIN o[46]
    DIRECTION OUTPUT ;
    USE SIGNAL ;
    PORT
      LAYER M4 ;
        RECT  0 5.232 0.084 5.256 ;
    END
  END o[46]
  PIN o[470]
    DIRECTION OUTPUT ;
    USE SIGNAL ;
    PORT
      LAYER M4 ;
        RECT  0 47.472 0.084 47.496 ;
    END
  END o[470]
  PIN o[471]
    DIRECTION OUTPUT ;
    USE SIGNAL ;
    PORT
      LAYER M4 ;
        RECT  0 47.568 0.084 47.592 ;
    END
  END o[471]
  PIN o[472]
    DIRECTION OUTPUT ;
    USE SIGNAL ;
    PORT
      LAYER M4 ;
        RECT  0 47.664 0.084 47.688 ;
    END
  END o[472]
  PIN o[473]
    DIRECTION OUTPUT ;
    USE SIGNAL ;
    PORT
      LAYER M4 ;
        RECT  0 47.808 0.084 47.832 ;
    END
  END o[473]
  PIN o[474]
    DIRECTION OUTPUT ;
    USE SIGNAL ;
    PORT
      LAYER M4 ;
        RECT  0 47.904 0.084 47.928 ;
    END
  END o[474]
  PIN o[475]
    DIRECTION OUTPUT ;
    USE SIGNAL ;
    PORT
      LAYER M4 ;
        RECT  0 48 0.084 48.024 ;
    END
  END o[475]
  PIN o[476]
    DIRECTION OUTPUT ;
    USE SIGNAL ;
    PORT
      LAYER M4 ;
        RECT  0 48.096 0.084 48.12 ;
    END
  END o[476]
  PIN o[477]
    DIRECTION OUTPUT ;
    USE SIGNAL ;
    PORT
      LAYER M4 ;
        RECT  0 48.192 0.084 48.216 ;
    END
  END o[477]
  PIN o[478]
    DIRECTION OUTPUT ;
    USE SIGNAL ;
    PORT
      LAYER M4 ;
        RECT  0 48.288 0.084 48.312 ;
    END
  END o[478]
  PIN o[479]
    DIRECTION OUTPUT ;
    USE SIGNAL ;
    PORT
      LAYER M4 ;
        RECT  0 48.384 0.084 48.408 ;
    END
  END o[479]
  PIN o[47]
    DIRECTION OUTPUT ;
    USE SIGNAL ;
    PORT
      LAYER M4 ;
        RECT  0 5.328 0.084 5.352 ;
    END
  END o[47]
  PIN o[480]
    DIRECTION OUTPUT ;
    USE SIGNAL ;
    PORT
      LAYER M4 ;
        RECT  0 48.48 0.084 48.504 ;
    END
  END o[480]
  PIN o[481]
    DIRECTION OUTPUT ;
    USE SIGNAL ;
    PORT
      LAYER M4 ;
        RECT  0 48.576 0.084 48.6 ;
    END
  END o[481]
  PIN o[482]
    DIRECTION OUTPUT ;
    USE SIGNAL ;
    PORT
      LAYER M4 ;
        RECT  0 48.672 0.084 48.696 ;
    END
  END o[482]
  PIN o[483]
    DIRECTION OUTPUT ;
    USE SIGNAL ;
    PORT
      LAYER M4 ;
        RECT  0 48.768 0.084 48.792 ;
    END
  END o[483]
  PIN o[484]
    DIRECTION OUTPUT ;
    USE SIGNAL ;
    PORT
      LAYER M4 ;
        RECT  0 48.864 0.084 48.888 ;
    END
  END o[484]
  PIN o[485]
    DIRECTION OUTPUT ;
    USE SIGNAL ;
    PORT
      LAYER M4 ;
        RECT  0 48.96 0.084 48.984 ;
    END
  END o[485]
  PIN o[486]
    DIRECTION OUTPUT ;
    USE SIGNAL ;
    PORT
      LAYER M4 ;
        RECT  0 49.104 0.084 49.128 ;
    END
  END o[486]
  PIN o[487]
    DIRECTION OUTPUT ;
    USE SIGNAL ;
    PORT
      LAYER M4 ;
        RECT  0 49.2 0.084 49.224 ;
    END
  END o[487]
  PIN o[488]
    DIRECTION OUTPUT ;
    USE SIGNAL ;
    PORT
      LAYER M4 ;
        RECT  0 49.296 0.084 49.32 ;
    END
  END o[488]
  PIN o[489]
    DIRECTION OUTPUT ;
    USE SIGNAL ;
    PORT
      LAYER M4 ;
        RECT  0 49.392 0.084 49.416 ;
    END
  END o[489]
  PIN o[48]
    DIRECTION OUTPUT ;
    USE SIGNAL ;
    PORT
      LAYER M4 ;
        RECT  0 5.424 0.084 5.448 ;
    END
  END o[48]
  PIN o[490]
    DIRECTION OUTPUT ;
    USE SIGNAL ;
    PORT
      LAYER M4 ;
        RECT  0 49.488 0.084 49.512 ;
    END
  END o[490]
  PIN o[491]
    DIRECTION OUTPUT ;
    USE SIGNAL ;
    PORT
      LAYER M4 ;
        RECT  0 49.584 0.084 49.608 ;
    END
  END o[491]
  PIN o[492]
    DIRECTION OUTPUT ;
    USE SIGNAL ;
    PORT
      LAYER M4 ;
        RECT  0 49.68 0.084 49.704 ;
    END
  END o[492]
  PIN o[493]
    DIRECTION OUTPUT ;
    USE SIGNAL ;
    PORT
      LAYER M4 ;
        RECT  0 49.776 0.084 49.8 ;
    END
  END o[493]
  PIN o[494]
    DIRECTION OUTPUT ;
    USE SIGNAL ;
    PORT
      LAYER M4 ;
        RECT  0 49.872 0.084 49.896 ;
    END
  END o[494]
  PIN o[495]
    DIRECTION OUTPUT ;
    USE SIGNAL ;
    PORT
      LAYER M4 ;
        RECT  0 49.968 0.084 49.992 ;
    END
  END o[495]
  PIN o[496]
    DIRECTION OUTPUT ;
    USE SIGNAL ;
    PORT
      LAYER M4 ;
        RECT  0 50.064 0.084 50.088 ;
    END
  END o[496]
  PIN o[497]
    DIRECTION OUTPUT ;
    USE SIGNAL ;
    PORT
      LAYER M4 ;
        RECT  0 50.16 0.084 50.184 ;
    END
  END o[497]
  PIN o[498]
    DIRECTION OUTPUT ;
    USE SIGNAL ;
    PORT
      LAYER M4 ;
        RECT  0 50.256 0.084 50.28 ;
    END
  END o[498]
  PIN o[499]
    DIRECTION OUTPUT ;
    USE SIGNAL ;
    PORT
      LAYER M4 ;
        RECT  0 50.4 0.084 50.424 ;
    END
  END o[499]
  PIN o[49]
    DIRECTION OUTPUT ;
    USE SIGNAL ;
    PORT
      LAYER M4 ;
        RECT  0 5.52 0.084 5.544 ;
    END
  END o[49]
  PIN o[4]
    DIRECTION OUTPUT ;
    USE SIGNAL ;
    PORT
      LAYER M4 ;
        RECT  0 1.056 0.084 1.08 ;
    END
  END o[4]
  PIN o[500]
    DIRECTION OUTPUT ;
    USE SIGNAL ;
    PORT
      LAYER M4 ;
        RECT  0 50.496 0.084 50.52 ;
    END
  END o[500]
  PIN o[501]
    DIRECTION OUTPUT ;
    USE SIGNAL ;
    PORT
      LAYER M4 ;
        RECT  0 50.592 0.084 50.616 ;
    END
  END o[501]
  PIN o[502]
    DIRECTION OUTPUT ;
    USE SIGNAL ;
    PORT
      LAYER M4 ;
        RECT  0 50.688 0.084 50.712 ;
    END
  END o[502]
  PIN o[503]
    DIRECTION OUTPUT ;
    USE SIGNAL ;
    PORT
      LAYER M4 ;
        RECT  0 50.784 0.084 50.808 ;
    END
  END o[503]
  PIN o[504]
    DIRECTION OUTPUT ;
    USE SIGNAL ;
    PORT
      LAYER M4 ;
        RECT  0 50.88 0.084 50.904 ;
    END
  END o[504]
  PIN o[505]
    DIRECTION OUTPUT ;
    USE SIGNAL ;
    PORT
      LAYER M4 ;
        RECT  0 50.976 0.084 51 ;
    END
  END o[505]
  PIN o[506]
    DIRECTION OUTPUT ;
    USE SIGNAL ;
    PORT
      LAYER M4 ;
        RECT  0 51.072 0.084 51.096 ;
    END
  END o[506]
  PIN o[507]
    DIRECTION OUTPUT ;
    USE SIGNAL ;
    PORT
      LAYER M4 ;
        RECT  0 51.168 0.084 51.192 ;
    END
  END o[507]
  PIN o[508]
    DIRECTION OUTPUT ;
    USE SIGNAL ;
    PORT
      LAYER M4 ;
        RECT  0 51.264 0.084 51.288 ;
    END
  END o[508]
  PIN o[509]
    DIRECTION OUTPUT ;
    USE SIGNAL ;
    PORT
      LAYER M4 ;
        RECT  0 51.36 0.084 51.384 ;
    END
  END o[509]
  PIN o[50]
    DIRECTION OUTPUT ;
    USE SIGNAL ;
    PORT
      LAYER M4 ;
        RECT  0 5.616 0.084 5.64 ;
    END
  END o[50]
  PIN o[510]
    DIRECTION OUTPUT ;
    USE SIGNAL ;
    PORT
      LAYER M4 ;
        RECT  0 51.456 0.084 51.48 ;
    END
  END o[510]
  PIN o[511]
    DIRECTION OUTPUT ;
    USE SIGNAL ;
    PORT
      LAYER M4 ;
        RECT  0 51.552 0.084 51.576 ;
    END
  END o[511]
  PIN o[512]
    DIRECTION OUTPUT ;
    USE SIGNAL ;
    PORT
      LAYER M4 ;
        RECT  0 51.696 0.084 51.72 ;
    END
  END o[512]
  PIN o[513]
    DIRECTION OUTPUT ;
    USE SIGNAL ;
    PORT
      LAYER M4 ;
        RECT  0 51.792 0.084 51.816 ;
    END
  END o[513]
  PIN o[514]
    DIRECTION OUTPUT ;
    USE SIGNAL ;
    PORT
      LAYER M4 ;
        RECT  0 51.888 0.084 51.912 ;
    END
  END o[514]
  PIN o[515]
    DIRECTION OUTPUT ;
    USE SIGNAL ;
    PORT
      LAYER M4 ;
        RECT  0 51.984 0.084 52.008 ;
    END
  END o[515]
  PIN o[516]
    DIRECTION OUTPUT ;
    USE SIGNAL ;
    PORT
      LAYER M4 ;
        RECT  0 52.08 0.084 52.104 ;
    END
  END o[516]
  PIN o[517]
    DIRECTION OUTPUT ;
    USE SIGNAL ;
    PORT
      LAYER M4 ;
        RECT  0 52.176 0.084 52.2 ;
    END
  END o[517]
  PIN o[518]
    DIRECTION OUTPUT ;
    USE SIGNAL ;
    PORT
      LAYER M4 ;
        RECT  0 52.272 0.084 52.296 ;
    END
  END o[518]
  PIN o[519]
    DIRECTION OUTPUT ;
    USE SIGNAL ;
    PORT
      LAYER M4 ;
        RECT  0 52.368 0.084 52.392 ;
    END
  END o[519]
  PIN o[51]
    DIRECTION OUTPUT ;
    USE SIGNAL ;
    PORT
      LAYER M4 ;
        RECT  0 5.712 0.084 5.736 ;
    END
  END o[51]
  PIN o[520]
    DIRECTION OUTPUT ;
    USE SIGNAL ;
    PORT
      LAYER M4 ;
        RECT  0 52.464 0.084 52.488 ;
    END
  END o[520]
  PIN o[521]
    DIRECTION OUTPUT ;
    USE SIGNAL ;
    PORT
      LAYER M4 ;
        RECT  0 52.56 0.084 52.584 ;
    END
  END o[521]
  PIN o[522]
    DIRECTION OUTPUT ;
    USE SIGNAL ;
    PORT
      LAYER M4 ;
        RECT  0 52.656 0.084 52.68 ;
    END
  END o[522]
  PIN o[523]
    DIRECTION OUTPUT ;
    USE SIGNAL ;
    PORT
      LAYER M4 ;
        RECT  0 52.752 0.084 52.776 ;
    END
  END o[523]
  PIN o[524]
    DIRECTION OUTPUT ;
    USE SIGNAL ;
    PORT
      LAYER M4 ;
        RECT  0 52.848 0.084 52.872 ;
    END
  END o[524]
  PIN o[525]
    DIRECTION OUTPUT ;
    USE SIGNAL ;
    PORT
      LAYER M4 ;
        RECT  0 52.992 0.084 53.016 ;
    END
  END o[525]
  PIN o[526]
    DIRECTION OUTPUT ;
    USE SIGNAL ;
    PORT
      LAYER M4 ;
        RECT  0 53.088 0.084 53.112 ;
    END
  END o[526]
  PIN o[527]
    DIRECTION OUTPUT ;
    USE SIGNAL ;
    PORT
      LAYER M4 ;
        RECT  0 53.184 0.084 53.208 ;
    END
  END o[527]
  PIN o[528]
    DIRECTION OUTPUT ;
    USE SIGNAL ;
    PORT
      LAYER M4 ;
        RECT  0 53.28 0.084 53.304 ;
    END
  END o[528]
  PIN o[529]
    DIRECTION OUTPUT ;
    USE SIGNAL ;
    PORT
      LAYER M4 ;
        RECT  0 53.376 0.084 53.4 ;
    END
  END o[529]
  PIN o[52]
    DIRECTION OUTPUT ;
    USE SIGNAL ;
    PORT
      LAYER M4 ;
        RECT  0 5.808 0.084 5.832 ;
    END
  END o[52]
  PIN o[530]
    DIRECTION OUTPUT ;
    USE SIGNAL ;
    PORT
      LAYER M4 ;
        RECT  0 53.472 0.084 53.496 ;
    END
  END o[530]
  PIN o[531]
    DIRECTION OUTPUT ;
    USE SIGNAL ;
    PORT
      LAYER M4 ;
        RECT  0 53.568 0.084 53.592 ;
    END
  END o[531]
  PIN o[532]
    DIRECTION OUTPUT ;
    USE SIGNAL ;
    PORT
      LAYER M4 ;
        RECT  0 53.664 0.084 53.688 ;
    END
  END o[532]
  PIN o[533]
    DIRECTION OUTPUT ;
    USE SIGNAL ;
    PORT
      LAYER M4 ;
        RECT  0 53.76 0.084 53.784 ;
    END
  END o[533]
  PIN o[534]
    DIRECTION OUTPUT ;
    USE SIGNAL ;
    PORT
      LAYER M4 ;
        RECT  0 53.856 0.084 53.88 ;
    END
  END o[534]
  PIN o[535]
    DIRECTION OUTPUT ;
    USE SIGNAL ;
    PORT
      LAYER M4 ;
        RECT  0 53.952 0.084 53.976 ;
    END
  END o[535]
  PIN o[536]
    DIRECTION OUTPUT ;
    USE SIGNAL ;
    PORT
      LAYER M4 ;
        RECT  0 54.048 0.084 54.072 ;
    END
  END o[536]
  PIN o[537]
    DIRECTION OUTPUT ;
    USE SIGNAL ;
    PORT
      LAYER M4 ;
        RECT  0 54.144 0.084 54.168 ;
    END
  END o[537]
  PIN o[538]
    DIRECTION OUTPUT ;
    USE SIGNAL ;
    PORT
      LAYER M4 ;
        RECT  0 54.288 0.084 54.312 ;
    END
  END o[538]
  PIN o[539]
    DIRECTION OUTPUT ;
    USE SIGNAL ;
    PORT
      LAYER M4 ;
        RECT  0 54.384 0.084 54.408 ;
    END
  END o[539]
  PIN o[53]
    DIRECTION OUTPUT ;
    USE SIGNAL ;
    PORT
      LAYER M4 ;
        RECT  0 5.904 0.084 5.928 ;
    END
  END o[53]
  PIN o[540]
    DIRECTION OUTPUT ;
    USE SIGNAL ;
    PORT
      LAYER M4 ;
        RECT  0 54.48 0.084 54.504 ;
    END
  END o[540]
  PIN o[541]
    DIRECTION OUTPUT ;
    USE SIGNAL ;
    PORT
      LAYER M4 ;
        RECT  0 54.576 0.084 54.6 ;
    END
  END o[541]
  PIN o[542]
    DIRECTION OUTPUT ;
    USE SIGNAL ;
    PORT
      LAYER M4 ;
        RECT  0 54.672 0.084 54.696 ;
    END
  END o[542]
  PIN o[543]
    DIRECTION OUTPUT ;
    USE SIGNAL ;
    PORT
      LAYER M4 ;
        RECT  0 54.768 0.084 54.792 ;
    END
  END o[543]
  PIN o[544]
    DIRECTION OUTPUT ;
    USE SIGNAL ;
    PORT
      LAYER M4 ;
        RECT  0 54.864 0.084 54.888 ;
    END
  END o[544]
  PIN o[545]
    DIRECTION OUTPUT ;
    USE SIGNAL ;
    PORT
      LAYER M4 ;
        RECT  0 54.96 0.084 54.984 ;
    END
  END o[545]
  PIN o[546]
    DIRECTION OUTPUT ;
    USE SIGNAL ;
    PORT
      LAYER M4 ;
        RECT  0 55.056 0.084 55.08 ;
    END
  END o[546]
  PIN o[547]
    DIRECTION OUTPUT ;
    USE SIGNAL ;
    PORT
      LAYER M4 ;
        RECT  0 55.152 0.084 55.176 ;
    END
  END o[547]
  PIN o[548]
    DIRECTION OUTPUT ;
    USE SIGNAL ;
    PORT
      LAYER M4 ;
        RECT  0 55.248 0.084 55.272 ;
    END
  END o[548]
  PIN o[549]
    DIRECTION OUTPUT ;
    USE SIGNAL ;
    PORT
      LAYER M4 ;
        RECT  0 55.344 0.084 55.368 ;
    END
  END o[549]
  PIN o[54]
    DIRECTION OUTPUT ;
    USE SIGNAL ;
    PORT
      LAYER M4 ;
        RECT  0 6 0.084 6.024 ;
    END
  END o[54]
  PIN o[550]
    DIRECTION OUTPUT ;
    USE SIGNAL ;
    PORT
      LAYER M4 ;
        RECT  0 55.44 0.084 55.464 ;
    END
  END o[550]
  PIN o[551]
    DIRECTION OUTPUT ;
    USE SIGNAL ;
    PORT
      LAYER M4 ;
        RECT  0 55.584 0.084 55.608 ;
    END
  END o[551]
  PIN o[552]
    DIRECTION OUTPUT ;
    USE SIGNAL ;
    PORT
      LAYER M4 ;
        RECT  0 55.68 0.084 55.704 ;
    END
  END o[552]
  PIN o[553]
    DIRECTION OUTPUT ;
    USE SIGNAL ;
    PORT
      LAYER M4 ;
        RECT  0 55.776 0.084 55.8 ;
    END
  END o[553]
  PIN o[554]
    DIRECTION OUTPUT ;
    USE SIGNAL ;
    PORT
      LAYER M4 ;
        RECT  0 55.872 0.084 55.896 ;
    END
  END o[554]
  PIN o[555]
    DIRECTION OUTPUT ;
    USE SIGNAL ;
    PORT
      LAYER M4 ;
        RECT  0 55.968 0.084 55.992 ;
    END
  END o[555]
  PIN o[556]
    DIRECTION OUTPUT ;
    USE SIGNAL ;
    PORT
      LAYER M4 ;
        RECT  0 56.064 0.084 56.088 ;
    END
  END o[556]
  PIN o[557]
    DIRECTION OUTPUT ;
    USE SIGNAL ;
    PORT
      LAYER M4 ;
        RECT  0 56.16 0.084 56.184 ;
    END
  END o[557]
  PIN o[558]
    DIRECTION OUTPUT ;
    USE SIGNAL ;
    PORT
      LAYER M4 ;
        RECT  0 56.256 0.084 56.28 ;
    END
  END o[558]
  PIN o[559]
    DIRECTION OUTPUT ;
    USE SIGNAL ;
    PORT
      LAYER M4 ;
        RECT  0 56.352 0.084 56.376 ;
    END
  END o[559]
  PIN o[55]
    DIRECTION OUTPUT ;
    USE SIGNAL ;
    PORT
      LAYER M4 ;
        RECT  0 6.144 0.084 6.168 ;
    END
  END o[55]
  PIN o[560]
    DIRECTION OUTPUT ;
    USE SIGNAL ;
    PORT
      LAYER M4 ;
        RECT  0 56.448 0.084 56.472 ;
    END
  END o[560]
  PIN o[561]
    DIRECTION OUTPUT ;
    USE SIGNAL ;
    PORT
      LAYER M4 ;
        RECT  0 56.544 0.084 56.568 ;
    END
  END o[561]
  PIN o[562]
    DIRECTION OUTPUT ;
    USE SIGNAL ;
    PORT
      LAYER M4 ;
        RECT  0 56.64 0.084 56.664 ;
    END
  END o[562]
  PIN o[563]
    DIRECTION OUTPUT ;
    USE SIGNAL ;
    PORT
      LAYER M4 ;
        RECT  0 56.736 0.084 56.76 ;
    END
  END o[563]
  PIN o[564]
    DIRECTION OUTPUT ;
    USE SIGNAL ;
    PORT
      LAYER M4 ;
        RECT  0 56.88 0.084 56.904 ;
    END
  END o[564]
  PIN o[565]
    DIRECTION OUTPUT ;
    USE SIGNAL ;
    PORT
      LAYER M4 ;
        RECT  0 56.976 0.084 57 ;
    END
  END o[565]
  PIN o[566]
    DIRECTION OUTPUT ;
    USE SIGNAL ;
    PORT
      LAYER M4 ;
        RECT  0 57.072 0.084 57.096 ;
    END
  END o[566]
  PIN o[567]
    DIRECTION OUTPUT ;
    USE SIGNAL ;
    PORT
      LAYER M4 ;
        RECT  0 57.168 0.084 57.192 ;
    END
  END o[567]
  PIN o[568]
    DIRECTION OUTPUT ;
    USE SIGNAL ;
    PORT
      LAYER M4 ;
        RECT  0 57.264 0.084 57.288 ;
    END
  END o[568]
  PIN o[569]
    DIRECTION OUTPUT ;
    USE SIGNAL ;
    PORT
      LAYER M4 ;
        RECT  0 57.36 0.084 57.384 ;
    END
  END o[569]
  PIN o[56]
    DIRECTION OUTPUT ;
    USE SIGNAL ;
    PORT
      LAYER M4 ;
        RECT  0 6.24 0.084 6.264 ;
    END
  END o[56]
  PIN o[570]
    DIRECTION OUTPUT ;
    USE SIGNAL ;
    PORT
      LAYER M4 ;
        RECT  0 57.456 0.084 57.48 ;
    END
  END o[570]
  PIN o[571]
    DIRECTION OUTPUT ;
    USE SIGNAL ;
    PORT
      LAYER M4 ;
        RECT  0 57.552 0.084 57.576 ;
    END
  END o[571]
  PIN o[572]
    DIRECTION OUTPUT ;
    USE SIGNAL ;
    PORT
      LAYER M4 ;
        RECT  0 57.648 0.084 57.672 ;
    END
  END o[572]
  PIN o[573]
    DIRECTION OUTPUT ;
    USE SIGNAL ;
    PORT
      LAYER M4 ;
        RECT  0 57.744 0.084 57.768 ;
    END
  END o[573]
  PIN o[574]
    DIRECTION OUTPUT ;
    USE SIGNAL ;
    PORT
      LAYER M4 ;
        RECT  0 57.84 0.084 57.864 ;
    END
  END o[574]
  PIN o[575]
    DIRECTION OUTPUT ;
    USE SIGNAL ;
    PORT
      LAYER M4 ;
        RECT  0 57.936 0.084 57.96 ;
    END
  END o[575]
  PIN o[576]
    DIRECTION OUTPUT ;
    USE SIGNAL ;
    PORT
      LAYER M4 ;
        RECT  0 58.032 0.084 58.056 ;
    END
  END o[576]
  PIN o[577]
    DIRECTION OUTPUT ;
    USE SIGNAL ;
    PORT
      LAYER M4 ;
        RECT  0 58.176 0.084 58.2 ;
    END
  END o[577]
  PIN o[578]
    DIRECTION OUTPUT ;
    USE SIGNAL ;
    PORT
      LAYER M4 ;
        RECT  0 58.272 0.084 58.296 ;
    END
  END o[578]
  PIN o[579]
    DIRECTION OUTPUT ;
    USE SIGNAL ;
    PORT
      LAYER M4 ;
        RECT  0 58.368 0.084 58.392 ;
    END
  END o[579]
  PIN o[57]
    DIRECTION OUTPUT ;
    USE SIGNAL ;
    PORT
      LAYER M4 ;
        RECT  0 6.336 0.084 6.36 ;
    END
  END o[57]
  PIN o[580]
    DIRECTION OUTPUT ;
    USE SIGNAL ;
    PORT
      LAYER M4 ;
        RECT  0 58.464 0.084 58.488 ;
    END
  END o[580]
  PIN o[581]
    DIRECTION OUTPUT ;
    USE SIGNAL ;
    PORT
      LAYER M4 ;
        RECT  0 58.56 0.084 58.584 ;
    END
  END o[581]
  PIN o[582]
    DIRECTION OUTPUT ;
    USE SIGNAL ;
    PORT
      LAYER M4 ;
        RECT  0 58.656 0.084 58.68 ;
    END
  END o[582]
  PIN o[583]
    DIRECTION OUTPUT ;
    USE SIGNAL ;
    PORT
      LAYER M4 ;
        RECT  0 58.752 0.084 58.776 ;
    END
  END o[583]
  PIN o[584]
    DIRECTION OUTPUT ;
    USE SIGNAL ;
    PORT
      LAYER M4 ;
        RECT  0 58.848 0.084 58.872 ;
    END
  END o[584]
  PIN o[585]
    DIRECTION OUTPUT ;
    USE SIGNAL ;
    PORT
      LAYER M4 ;
        RECT  0 58.944 0.084 58.968 ;
    END
  END o[585]
  PIN o[586]
    DIRECTION OUTPUT ;
    USE SIGNAL ;
    PORT
      LAYER M4 ;
        RECT  0 59.04 0.084 59.064 ;
    END
  END o[586]
  PIN o[587]
    DIRECTION OUTPUT ;
    USE SIGNAL ;
    PORT
      LAYER M4 ;
        RECT  0 59.136 0.084 59.16 ;
    END
  END o[587]
  PIN o[588]
    DIRECTION OUTPUT ;
    USE SIGNAL ;
    PORT
      LAYER M4 ;
        RECT  0 59.232 0.084 59.256 ;
    END
  END o[588]
  PIN o[589]
    DIRECTION OUTPUT ;
    USE SIGNAL ;
    PORT
      LAYER M4 ;
        RECT  0 59.328 0.084 59.352 ;
    END
  END o[589]
  PIN o[58]
    DIRECTION OUTPUT ;
    USE SIGNAL ;
    PORT
      LAYER M4 ;
        RECT  0 6.432 0.084 6.456 ;
    END
  END o[58]
  PIN o[590]
    DIRECTION OUTPUT ;
    USE SIGNAL ;
    PORT
      LAYER M4 ;
        RECT  0 59.472 0.084 59.496 ;
    END
  END o[590]
  PIN o[591]
    DIRECTION OUTPUT ;
    USE SIGNAL ;
    PORT
      LAYER M4 ;
        RECT  0 59.568 0.084 59.592 ;
    END
  END o[591]
  PIN o[592]
    DIRECTION OUTPUT ;
    USE SIGNAL ;
    PORT
      LAYER M4 ;
        RECT  0 59.664 0.084 59.688 ;
    END
  END o[592]
  PIN o[593]
    DIRECTION OUTPUT ;
    USE SIGNAL ;
    PORT
      LAYER M4 ;
        RECT  0 59.76 0.084 59.784 ;
    END
  END o[593]
  PIN o[594]
    DIRECTION OUTPUT ;
    USE SIGNAL ;
    PORT
      LAYER M4 ;
        RECT  0 59.856 0.084 59.88 ;
    END
  END o[594]
  PIN o[595]
    DIRECTION OUTPUT ;
    USE SIGNAL ;
    PORT
      LAYER M4 ;
        RECT  0 59.952 0.084 59.976 ;
    END
  END o[595]
  PIN o[596]
    DIRECTION OUTPUT ;
    USE SIGNAL ;
    PORT
      LAYER M4 ;
        RECT  0 60.048 0.084 60.072 ;
    END
  END o[596]
  PIN o[597]
    DIRECTION OUTPUT ;
    USE SIGNAL ;
    PORT
      LAYER M4 ;
        RECT  0 60.144 0.084 60.168 ;
    END
  END o[597]
  PIN o[598]
    DIRECTION OUTPUT ;
    USE SIGNAL ;
    PORT
      LAYER M4 ;
        RECT  0 60.24 0.084 60.264 ;
    END
  END o[598]
  PIN o[599]
    DIRECTION OUTPUT ;
    USE SIGNAL ;
    PORT
      LAYER M4 ;
        RECT  0 60.336 0.084 60.36 ;
    END
  END o[599]
  PIN o[59]
    DIRECTION OUTPUT ;
    USE SIGNAL ;
    PORT
      LAYER M4 ;
        RECT  0 6.528 0.084 6.552 ;
    END
  END o[59]
  PIN o[5]
    DIRECTION OUTPUT ;
    USE SIGNAL ;
    PORT
      LAYER M4 ;
        RECT  0 1.152 0.084 1.176 ;
    END
  END o[5]
  PIN o[600]
    DIRECTION OUTPUT ;
    USE SIGNAL ;
    PORT
      LAYER M4 ;
        RECT  0 60.432 0.084 60.456 ;
    END
  END o[600]
  PIN o[601]
    DIRECTION OUTPUT ;
    USE SIGNAL ;
    PORT
      LAYER M4 ;
        RECT  0 60.528 0.084 60.552 ;
    END
  END o[601]
  PIN o[602]
    DIRECTION OUTPUT ;
    USE SIGNAL ;
    PORT
      LAYER M4 ;
        RECT  0 60.624 0.084 60.648 ;
    END
  END o[602]
  PIN o[603]
    DIRECTION OUTPUT ;
    USE SIGNAL ;
    PORT
      LAYER M4 ;
        RECT  0 60.768 0.084 60.792 ;
    END
  END o[603]
  PIN o[604]
    DIRECTION OUTPUT ;
    USE SIGNAL ;
    PORT
      LAYER M4 ;
        RECT  0 60.864 0.084 60.888 ;
    END
  END o[604]
  PIN o[605]
    DIRECTION OUTPUT ;
    USE SIGNAL ;
    PORT
      LAYER M4 ;
        RECT  0 60.96 0.084 60.984 ;
    END
  END o[605]
  PIN o[606]
    DIRECTION OUTPUT ;
    USE SIGNAL ;
    PORT
      LAYER M4 ;
        RECT  0 61.056 0.084 61.08 ;
    END
  END o[606]
  PIN o[607]
    DIRECTION OUTPUT ;
    USE SIGNAL ;
    PORT
      LAYER M4 ;
        RECT  0 61.152 0.084 61.176 ;
    END
  END o[607]
  PIN o[608]
    DIRECTION OUTPUT ;
    USE SIGNAL ;
    PORT
      LAYER M4 ;
        RECT  0 61.248 0.084 61.272 ;
    END
  END o[608]
  PIN o[609]
    DIRECTION OUTPUT ;
    USE SIGNAL ;
    PORT
      LAYER M4 ;
        RECT  0 61.344 0.084 61.368 ;
    END
  END o[609]
  PIN o[60]
    DIRECTION OUTPUT ;
    USE SIGNAL ;
    PORT
      LAYER M4 ;
        RECT  0 6.624 0.084 6.648 ;
    END
  END o[60]
  PIN o[610]
    DIRECTION OUTPUT ;
    USE SIGNAL ;
    PORT
      LAYER M4 ;
        RECT  0 61.44 0.084 61.464 ;
    END
  END o[610]
  PIN o[611]
    DIRECTION OUTPUT ;
    USE SIGNAL ;
    PORT
      LAYER M4 ;
        RECT  0 61.536 0.084 61.56 ;
    END
  END o[611]
  PIN o[612]
    DIRECTION OUTPUT ;
    USE SIGNAL ;
    PORT
      LAYER M4 ;
        RECT  0 61.632 0.084 61.656 ;
    END
  END o[612]
  PIN o[613]
    DIRECTION OUTPUT ;
    USE SIGNAL ;
    PORT
      LAYER M4 ;
        RECT  0 61.728 0.084 61.752 ;
    END
  END o[613]
  PIN o[614]
    DIRECTION OUTPUT ;
    USE SIGNAL ;
    PORT
      LAYER M4 ;
        RECT  0 61.824 0.084 61.848 ;
    END
  END o[614]
  PIN o[615]
    DIRECTION OUTPUT ;
    USE SIGNAL ;
    PORT
      LAYER M4 ;
        RECT  0 61.92 0.084 61.944 ;
    END
  END o[615]
  PIN o[616]
    DIRECTION OUTPUT ;
    USE SIGNAL ;
    PORT
      LAYER M4 ;
        RECT  0 62.064 0.084 62.088 ;
    END
  END o[616]
  PIN o[617]
    DIRECTION OUTPUT ;
    USE SIGNAL ;
    PORT
      LAYER M4 ;
        RECT  0 62.16 0.084 62.184 ;
    END
  END o[617]
  PIN o[618]
    DIRECTION OUTPUT ;
    USE SIGNAL ;
    PORT
      LAYER M4 ;
        RECT  0 62.256 0.084 62.28 ;
    END
  END o[618]
  PIN o[619]
    DIRECTION OUTPUT ;
    USE SIGNAL ;
    PORT
      LAYER M4 ;
        RECT  0 62.352 0.084 62.376 ;
    END
  END o[619]
  PIN o[61]
    DIRECTION OUTPUT ;
    USE SIGNAL ;
    PORT
      LAYER M4 ;
        RECT  0 6.72 0.084 6.744 ;
    END
  END o[61]
  PIN o[620]
    DIRECTION OUTPUT ;
    USE SIGNAL ;
    PORT
      LAYER M4 ;
        RECT  0 62.448 0.084 62.472 ;
    END
  END o[620]
  PIN o[621]
    DIRECTION OUTPUT ;
    USE SIGNAL ;
    PORT
      LAYER M4 ;
        RECT  0 62.544 0.084 62.568 ;
    END
  END o[621]
  PIN o[622]
    DIRECTION OUTPUT ;
    USE SIGNAL ;
    PORT
      LAYER M4 ;
        RECT  0 62.64 0.084 62.664 ;
    END
  END o[622]
  PIN o[623]
    DIRECTION OUTPUT ;
    USE SIGNAL ;
    PORT
      LAYER M4 ;
        RECT  0 62.736 0.084 62.76 ;
    END
  END o[623]
  PIN o[62]
    DIRECTION OUTPUT ;
    USE SIGNAL ;
    PORT
      LAYER M4 ;
        RECT  0 6.816 0.084 6.84 ;
    END
  END o[62]
  PIN o[63]
    DIRECTION OUTPUT ;
    USE SIGNAL ;
    PORT
      LAYER M4 ;
        RECT  0 6.912 0.084 6.936 ;
    END
  END o[63]
  PIN o[64]
    DIRECTION OUTPUT ;
    USE SIGNAL ;
    PORT
      LAYER M4 ;
        RECT  0 7.008 0.084 7.032 ;
    END
  END o[64]
  PIN o[65]
    DIRECTION OUTPUT ;
    USE SIGNAL ;
    PORT
      LAYER M4 ;
        RECT  0 7.104 0.084 7.128 ;
    END
  END o[65]
  PIN o[66]
    DIRECTION OUTPUT ;
    USE SIGNAL ;
    PORT
      LAYER M4 ;
        RECT  0 7.2 0.084 7.224 ;
    END
  END o[66]
  PIN o[67]
    DIRECTION OUTPUT ;
    USE SIGNAL ;
    PORT
      LAYER M4 ;
        RECT  0 7.296 0.084 7.32 ;
    END
  END o[67]
  PIN o[68]
    DIRECTION OUTPUT ;
    USE SIGNAL ;
    PORT
      LAYER M4 ;
        RECT  0 7.44 0.084 7.464 ;
    END
  END o[68]
  PIN o[69]
    DIRECTION OUTPUT ;
    USE SIGNAL ;
    PORT
      LAYER M4 ;
        RECT  0 7.536 0.084 7.56 ;
    END
  END o[69]
  PIN o[6]
    DIRECTION OUTPUT ;
    USE SIGNAL ;
    PORT
      LAYER M4 ;
        RECT  0 1.248 0.084 1.272 ;
    END
  END o[6]
  PIN o[70]
    DIRECTION OUTPUT ;
    USE SIGNAL ;
    PORT
      LAYER M4 ;
        RECT  0 7.632 0.084 7.656 ;
    END
  END o[70]
  PIN o[71]
    DIRECTION OUTPUT ;
    USE SIGNAL ;
    PORT
      LAYER M4 ;
        RECT  0 7.728 0.084 7.752 ;
    END
  END o[71]
  PIN o[72]
    DIRECTION OUTPUT ;
    USE SIGNAL ;
    PORT
      LAYER M4 ;
        RECT  0 7.824 0.084 7.848 ;
    END
  END o[72]
  PIN o[73]
    DIRECTION OUTPUT ;
    USE SIGNAL ;
    PORT
      LAYER M4 ;
        RECT  0 7.92 0.084 7.944 ;
    END
  END o[73]
  PIN o[74]
    DIRECTION OUTPUT ;
    USE SIGNAL ;
    PORT
      LAYER M4 ;
        RECT  0 8.016 0.084 8.04 ;
    END
  END o[74]
  PIN o[75]
    DIRECTION OUTPUT ;
    USE SIGNAL ;
    PORT
      LAYER M4 ;
        RECT  0 8.112 0.084 8.136 ;
    END
  END o[75]
  PIN o[76]
    DIRECTION OUTPUT ;
    USE SIGNAL ;
    PORT
      LAYER M4 ;
        RECT  0 8.208 0.084 8.232 ;
    END
  END o[76]
  PIN o[77]
    DIRECTION OUTPUT ;
    USE SIGNAL ;
    PORT
      LAYER M4 ;
        RECT  0 8.304 0.084 8.328 ;
    END
  END o[77]
  PIN o[78]
    DIRECTION OUTPUT ;
    USE SIGNAL ;
    PORT
      LAYER M4 ;
        RECT  0 8.4 0.084 8.424 ;
    END
  END o[78]
  PIN o[79]
    DIRECTION OUTPUT ;
    USE SIGNAL ;
    PORT
      LAYER M4 ;
        RECT  0 8.496 0.084 8.52 ;
    END
  END o[79]
  PIN o[7]
    DIRECTION OUTPUT ;
    USE SIGNAL ;
    PORT
      LAYER M4 ;
        RECT  0 1.344 0.084 1.368 ;
    END
  END o[7]
  PIN o[80]
    DIRECTION OUTPUT ;
    USE SIGNAL ;
    PORT
      LAYER M4 ;
        RECT  0 8.592 0.084 8.616 ;
    END
  END o[80]
  PIN o[81]
    DIRECTION OUTPUT ;
    USE SIGNAL ;
    PORT
      LAYER M4 ;
        RECT  0 8.736 0.084 8.76 ;
    END
  END o[81]
  PIN o[82]
    DIRECTION OUTPUT ;
    USE SIGNAL ;
    PORT
      LAYER M4 ;
        RECT  0 8.832 0.084 8.856 ;
    END
  END o[82]
  PIN o[83]
    DIRECTION OUTPUT ;
    USE SIGNAL ;
    PORT
      LAYER M4 ;
        RECT  0 8.928 0.084 8.952 ;
    END
  END o[83]
  PIN o[84]
    DIRECTION OUTPUT ;
    USE SIGNAL ;
    PORT
      LAYER M4 ;
        RECT  0 9.024 0.084 9.048 ;
    END
  END o[84]
  PIN o[85]
    DIRECTION OUTPUT ;
    USE SIGNAL ;
    PORT
      LAYER M4 ;
        RECT  0 9.12 0.084 9.144 ;
    END
  END o[85]
  PIN o[86]
    DIRECTION OUTPUT ;
    USE SIGNAL ;
    PORT
      LAYER M4 ;
        RECT  0 9.216 0.084 9.24 ;
    END
  END o[86]
  PIN o[87]
    DIRECTION OUTPUT ;
    USE SIGNAL ;
    PORT
      LAYER M4 ;
        RECT  0 9.312 0.084 9.336 ;
    END
  END o[87]
  PIN o[88]
    DIRECTION OUTPUT ;
    USE SIGNAL ;
    PORT
      LAYER M4 ;
        RECT  0 9.408 0.084 9.432 ;
    END
  END o[88]
  PIN o[89]
    DIRECTION OUTPUT ;
    USE SIGNAL ;
    PORT
      LAYER M4 ;
        RECT  0 9.504 0.084 9.528 ;
    END
  END o[89]
  PIN o[8]
    DIRECTION OUTPUT ;
    USE SIGNAL ;
    PORT
      LAYER M4 ;
        RECT  0 1.44 0.084 1.464 ;
    END
  END o[8]
  PIN o[90]
    DIRECTION OUTPUT ;
    USE SIGNAL ;
    PORT
      LAYER M4 ;
        RECT  0 9.6 0.084 9.624 ;
    END
  END o[90]
  PIN o[91]
    DIRECTION OUTPUT ;
    USE SIGNAL ;
    PORT
      LAYER M4 ;
        RECT  0 9.696 0.084 9.72 ;
    END
  END o[91]
  PIN o[92]
    DIRECTION OUTPUT ;
    USE SIGNAL ;
    PORT
      LAYER M4 ;
        RECT  0 9.792 0.084 9.816 ;
    END
  END o[92]
  PIN o[93]
    DIRECTION OUTPUT ;
    USE SIGNAL ;
    PORT
      LAYER M4 ;
        RECT  0 9.888 0.084 9.912 ;
    END
  END o[93]
  PIN o[94]
    DIRECTION OUTPUT ;
    USE SIGNAL ;
    PORT
      LAYER M4 ;
        RECT  0 10.032 0.084 10.056 ;
    END
  END o[94]
  PIN o[95]
    DIRECTION OUTPUT ;
    USE SIGNAL ;
    PORT
      LAYER M4 ;
        RECT  0 10.128 0.084 10.152 ;
    END
  END o[95]
  PIN o[96]
    DIRECTION OUTPUT ;
    USE SIGNAL ;
    PORT
      LAYER M4 ;
        RECT  0 10.224 0.084 10.248 ;
    END
  END o[96]
  PIN o[97]
    DIRECTION OUTPUT ;
    USE SIGNAL ;
    PORT
      LAYER M4 ;
        RECT  0 10.32 0.084 10.344 ;
    END
  END o[97]
  PIN o[98]
    DIRECTION OUTPUT ;
    USE SIGNAL ;
    PORT
      LAYER M4 ;
        RECT  0 10.416 0.084 10.44 ;
    END
  END o[98]
  PIN o[99]
    DIRECTION OUTPUT ;
    USE SIGNAL ;
    PORT
      LAYER M4 ;
        RECT  0 10.512 0.084 10.536 ;
    END
  END o[99]
  PIN o[9]
    DIRECTION OUTPUT ;
    USE SIGNAL ;
    PORT
      LAYER M4 ;
        RECT  0 1.536 0.084 1.56 ;
    END
  END o[9]
  PIN rs
    DIRECTION INPUT ;
    USE SIGNAL ;
    PORT
      LAYER M5 ;
        RECT  15.696 0 15.72 0.084 ;
    END
  END rs
  PIN rso
    DIRECTION OUTPUT ;
    USE SIGNAL ;
    PORT
      LAYER M4 ;
        RECT  0 63.792 0.084 63.816 ;
    END
  END rso
  PIN VDD
    DIRECTION INOUT ;
    USE POWER ;
    PORT
      LAYER M5 ;
        RECT  18.792 2.151 18.912 62.649 ;
        RECT  16.092 2.151 16.212 62.649 ;
        RECT  13.392 2.151 13.512 62.649 ;
        RECT  10.692 2.151 10.812 62.649 ;
        RECT  7.992 2.151 8.112 62.649 ;
        RECT  5.292 2.151 5.412 62.649 ;
        RECT  2.592 2.151 2.712 62.649 ;
    END
  END VDD
  PIN VSS
    DIRECTION INOUT ;
    USE GROUND ;
    PORT
      LAYER M5 ;
        RECT  18.6 2.137 18.72 62.663 ;
        RECT  15.9 2.137 16.02 62.663 ;
        RECT  13.2 2.137 13.32 62.663 ;
        RECT  10.5 2.137 10.62 62.663 ;
        RECT  7.8 2.137 7.92 62.663 ;
        RECT  5.1 2.137 5.22 62.663 ;
        RECT  2.4 2.137 2.52 62.663 ;
    END
  END VSS
  OBS
    LAYER RVTN ;
     RECT  2.16 2.16 19.44 2.295 ;
     RECT  2.16 2.565 19.44 2.835 ;
     RECT  2.16 3.105 19.44 3.375 ;
     RECT  2.16 3.645 19.44 3.915 ;
     RECT  2.16 4.185 19.44 4.455 ;
     RECT  2.16 4.725 19.44 4.995 ;
     RECT  2.16 5.265 19.44 5.535 ;
     RECT  2.16 5.805 19.44 6.075 ;
     RECT  2.16 6.345 19.44 6.615 ;
     RECT  2.16 6.885 19.44 7.155 ;
     RECT  2.16 7.425 19.44 7.695 ;
     RECT  2.16 7.965 19.44 8.235 ;
     RECT  2.16 8.505 19.44 8.775 ;
     RECT  2.16 9.045 19.44 9.315 ;
     RECT  2.16 9.585 19.44 9.855 ;
     RECT  2.16 10.125 19.44 10.395 ;
     RECT  2.16 10.665 19.44 10.935 ;
     RECT  2.16 11.205 19.44 11.475 ;
     RECT  2.16 11.745 19.44 12.015 ;
     RECT  2.16 12.285 19.44 12.555 ;
     RECT  2.16 12.825 19.44 13.095 ;
     RECT  2.16 13.365 19.44 13.635 ;
     RECT  2.16 13.905 19.44 14.175 ;
     RECT  2.16 14.445 19.44 14.715 ;
     RECT  2.16 14.985 19.44 15.255 ;
     RECT  2.16 15.525 19.44 15.795 ;
     RECT  2.16 16.065 19.44 16.335 ;
     RECT  2.16 16.605 19.44 16.875 ;
     RECT  2.16 17.145 19.44 17.415 ;
     RECT  2.16 17.685 19.44 17.955 ;
     RECT  2.16 18.225 19.44 18.495 ;
     RECT  2.16 18.765 19.44 19.035 ;
     RECT  2.16 19.305 19.44 19.575 ;
     RECT  2.16 19.845 19.44 20.115 ;
     RECT  2.16 20.385 19.44 20.655 ;
     RECT  2.16 20.925 19.44 21.195 ;
     RECT  2.16 21.465 19.44 21.735 ;
     RECT  2.16 22.005 19.44 22.275 ;
     RECT  2.16 22.545 19.44 22.815 ;
     RECT  2.16 23.085 19.44 23.355 ;
     RECT  2.16 23.625 19.44 23.895 ;
     RECT  2.16 24.165 19.44 24.435 ;
     RECT  2.16 24.705 19.44 24.975 ;
     RECT  2.16 25.245 19.44 25.515 ;
     RECT  2.16 25.785 19.44 26.055 ;
     RECT  2.16 26.325 19.44 26.595 ;
     RECT  2.16 26.865 19.44 27.135 ;
     RECT  2.16 27.405 19.44 27.675 ;
     RECT  2.16 27.945 19.44 28.215 ;
     RECT  2.16 28.485 19.44 28.755 ;
     RECT  2.16 29.025 19.44 29.295 ;
     RECT  2.16 29.565 19.44 29.835 ;
     RECT  2.16 30.105 19.44 30.375 ;
     RECT  2.16 30.645 19.44 30.915 ;
     RECT  2.16 31.185 19.44 31.455 ;
     RECT  2.16 31.725 19.44 31.995 ;
     RECT  2.16 32.265 19.44 32.535 ;
     RECT  2.16 32.805 19.44 33.075 ;
     RECT  2.16 33.345 19.44 33.615 ;
     RECT  2.16 33.885 19.44 34.155 ;
     RECT  2.16 34.425 19.44 34.695 ;
     RECT  2.16 34.965 19.44 35.235 ;
     RECT  2.16 35.505 19.44 35.775 ;
     RECT  2.16 36.045 19.44 36.315 ;
     RECT  2.16 36.585 19.44 36.855 ;
     RECT  2.16 37.125 19.44 37.395 ;
     RECT  2.16 37.665 19.44 37.935 ;
     RECT  2.16 38.205 19.44 38.475 ;
     RECT  2.16 38.745 19.44 39.015 ;
     RECT  2.16 39.285 19.44 39.555 ;
     RECT  2.16 39.825 19.44 40.095 ;
     RECT  2.16 40.365 19.44 40.635 ;
     RECT  2.16 40.905 19.44 41.175 ;
     RECT  2.16 41.445 19.44 41.715 ;
     RECT  2.16 41.985 19.44 42.255 ;
     RECT  2.16 42.525 19.44 42.795 ;
     RECT  2.16 43.065 19.44 43.335 ;
     RECT  2.16 43.605 19.44 43.875 ;
     RECT  2.16 44.145 19.44 44.415 ;
     RECT  2.16 44.685 19.44 44.955 ;
     RECT  2.16 45.225 19.44 45.495 ;
     RECT  2.16 45.765 19.44 46.035 ;
     RECT  2.16 46.305 19.44 46.575 ;
     RECT  2.16 46.845 19.44 47.115 ;
     RECT  2.16 47.385 19.44 47.655 ;
     RECT  2.16 47.925 19.44 48.195 ;
     RECT  2.16 48.465 19.44 48.735 ;
     RECT  2.16 49.005 19.44 49.275 ;
     RECT  2.16 49.545 19.44 49.815 ;
     RECT  2.16 50.085 19.44 50.355 ;
     RECT  2.16 50.625 19.44 50.895 ;
     RECT  2.16 51.165 19.44 51.435 ;
     RECT  2.16 51.705 19.44 51.975 ;
     RECT  2.16 52.245 19.44 52.515 ;
     RECT  2.16 52.785 19.44 53.055 ;
     RECT  2.16 53.325 19.44 53.595 ;
     RECT  2.16 53.865 19.44 54.135 ;
     RECT  2.16 54.405 19.44 54.675 ;
     RECT  2.16 54.945 19.44 55.215 ;
     RECT  2.16 55.485 19.44 55.755 ;
     RECT  2.16 56.025 19.44 56.295 ;
     RECT  2.16 56.565 19.44 56.835 ;
     RECT  2.16 57.105 19.44 57.375 ;
     RECT  2.16 57.645 19.44 57.915 ;
     RECT  2.16 58.185 19.44 58.455 ;
     RECT  2.16 58.725 19.44 58.995 ;
     RECT  2.16 59.265 19.44 59.535 ;
     RECT  2.16 59.805 19.44 60.075 ;
     RECT  2.16 60.345 19.44 60.615 ;
     RECT  2.16 60.885 19.44 61.155 ;
     RECT  2.16 61.425 19.44 61.695 ;
     RECT  2.16 61.965 19.44 62.235 ;
     RECT  2.16 62.505 19.44 62.64 ;
    LAYER RVTP ;
     RECT  2.16 2.295 19.44 2.565 ;
     RECT  2.16 2.835 19.44 3.105 ;
     RECT  2.16 3.375 19.44 3.645 ;
     RECT  2.16 3.915 19.44 4.185 ;
     RECT  2.16 4.455 19.44 4.725 ;
     RECT  2.16 4.995 19.44 5.265 ;
     RECT  2.16 5.535 19.44 5.805 ;
     RECT  2.16 6.075 19.44 6.345 ;
     RECT  2.16 6.615 19.44 6.885 ;
     RECT  2.16 7.155 19.44 7.425 ;
     RECT  2.16 7.695 19.44 7.965 ;
     RECT  2.16 8.235 19.44 8.505 ;
     RECT  2.16 8.775 19.44 9.045 ;
     RECT  2.16 9.315 19.44 9.585 ;
     RECT  2.16 9.855 19.44 10.125 ;
     RECT  2.16 10.395 19.44 10.665 ;
     RECT  2.16 10.935 19.44 11.205 ;
     RECT  2.16 11.475 19.44 11.745 ;
     RECT  2.16 12.015 19.44 12.285 ;
     RECT  2.16 12.555 19.44 12.825 ;
     RECT  2.16 13.095 19.44 13.365 ;
     RECT  2.16 13.635 19.44 13.905 ;
     RECT  2.16 14.175 19.44 14.445 ;
     RECT  2.16 14.715 19.44 14.985 ;
     RECT  2.16 15.255 19.44 15.525 ;
     RECT  2.16 15.795 19.44 16.065 ;
     RECT  2.16 16.335 19.44 16.605 ;
     RECT  2.16 16.875 19.44 17.145 ;
     RECT  2.16 17.415 19.44 17.685 ;
     RECT  2.16 17.955 19.44 18.225 ;
     RECT  2.16 18.495 19.44 18.765 ;
     RECT  2.16 19.035 19.44 19.305 ;
     RECT  2.16 19.575 19.44 19.845 ;
     RECT  2.16 20.115 19.44 20.385 ;
     RECT  2.16 20.655 19.44 20.925 ;
     RECT  2.16 21.195 19.44 21.465 ;
     RECT  2.16 21.735 19.44 22.005 ;
     RECT  2.16 22.275 19.44 22.545 ;
     RECT  2.16 22.815 19.44 23.085 ;
     RECT  2.16 23.355 19.44 23.625 ;
     RECT  2.16 23.895 19.44 24.165 ;
     RECT  2.16 24.435 19.44 24.705 ;
     RECT  2.16 24.975 19.44 25.245 ;
     RECT  2.16 25.515 19.44 25.785 ;
     RECT  2.16 26.055 19.44 26.325 ;
     RECT  2.16 26.595 19.44 26.865 ;
     RECT  2.16 27.135 19.44 27.405 ;
     RECT  2.16 27.675 19.44 27.945 ;
     RECT  2.16 28.215 19.44 28.485 ;
     RECT  2.16 28.755 19.44 29.025 ;
     RECT  2.16 29.295 19.44 29.565 ;
     RECT  2.16 29.835 19.44 30.105 ;
     RECT  2.16 30.375 19.44 30.645 ;
     RECT  2.16 30.915 19.44 31.185 ;
     RECT  2.16 31.455 19.44 31.725 ;
     RECT  2.16 31.995 19.44 32.265 ;
     RECT  2.16 32.535 19.44 32.805 ;
     RECT  2.16 33.075 19.44 33.345 ;
     RECT  2.16 33.615 19.44 33.885 ;
     RECT  2.16 34.155 19.44 34.425 ;
     RECT  2.16 34.695 19.44 34.965 ;
     RECT  2.16 35.235 19.44 35.505 ;
     RECT  2.16 35.775 19.44 36.045 ;
     RECT  2.16 36.315 19.44 36.585 ;
     RECT  2.16 36.855 19.44 37.125 ;
     RECT  2.16 37.395 19.44 37.665 ;
     RECT  2.16 37.935 19.44 38.205 ;
     RECT  2.16 38.475 19.44 38.745 ;
     RECT  2.16 39.015 19.44 39.285 ;
     RECT  2.16 39.555 19.44 39.825 ;
     RECT  2.16 40.095 19.44 40.365 ;
     RECT  2.16 40.635 19.44 40.905 ;
     RECT  2.16 41.175 19.44 41.445 ;
     RECT  2.16 41.715 19.44 41.985 ;
     RECT  2.16 42.255 19.44 42.525 ;
     RECT  2.16 42.795 19.44 43.065 ;
     RECT  2.16 43.335 19.44 43.605 ;
     RECT  2.16 43.875 19.44 44.145 ;
     RECT  2.16 44.415 19.44 44.685 ;
     RECT  2.16 44.955 19.44 45.225 ;
     RECT  2.16 45.495 19.44 45.765 ;
     RECT  2.16 46.035 19.44 46.305 ;
     RECT  2.16 46.575 19.44 46.845 ;
     RECT  2.16 47.115 19.44 47.385 ;
     RECT  2.16 47.655 19.44 47.925 ;
     RECT  2.16 48.195 19.44 48.465 ;
     RECT  2.16 48.735 19.44 49.005 ;
     RECT  2.16 49.275 19.44 49.545 ;
     RECT  2.16 49.815 19.44 50.085 ;
     RECT  2.16 50.355 19.44 50.625 ;
     RECT  2.16 50.895 19.44 51.165 ;
     RECT  2.16 51.435 19.44 51.705 ;
     RECT  2.16 51.975 19.44 52.245 ;
     RECT  2.16 52.515 19.44 52.785 ;
     RECT  2.16 53.055 19.44 53.325 ;
     RECT  2.16 53.595 19.44 53.865 ;
     RECT  2.16 54.135 19.44 54.405 ;
     RECT  2.16 54.675 19.44 54.945 ;
     RECT  2.16 55.215 19.44 55.485 ;
     RECT  2.16 55.755 19.44 56.025 ;
     RECT  2.16 56.295 19.44 56.565 ;
     RECT  2.16 56.835 19.44 57.105 ;
     RECT  2.16 57.375 19.44 57.645 ;
     RECT  2.16 57.915 19.44 58.185 ;
     RECT  2.16 58.455 19.44 58.725 ;
     RECT  2.16 58.995 19.44 59.265 ;
     RECT  2.16 59.535 19.44 59.805 ;
     RECT  2.16 60.075 19.44 60.345 ;
     RECT  2.16 60.615 19.44 60.885 ;
     RECT  2.16 61.155 19.44 61.425 ;
     RECT  2.16 61.695 19.44 61.965 ;
     RECT  2.16 62.235 19.44 62.505 ;
    LAYER M1 ;
     RECT  2.16 2.151 19.44 62.649 ;
    LAYER M2 ;
     RECT  0.103 8.514 0.139 8.532 ;
     RECT  0.103 20.088 0.203 20.214 ;
     RECT  0.103 33.93 0.203 33.948 ;
     RECT  0.103 37.674 0.203 37.692 ;
     RECT  0.103 41.922 0.203 41.94 ;
     RECT  0.103 43.11 0.203 43.128 ;
     RECT  0.103 44.388 0.203 44.406 ;
     RECT  0.103 58.896 0.203 58.914 ;
     RECT  0.103 62.244 0.203 62.262 ;
     RECT  0.139 8.514 0.239 8.604 ;
     RECT  0.103 49.788 0.239 49.806 ;
     RECT  0.103 57.816 0.275 57.834 ;
     RECT  0.103 17.001 0.347 17.172 ;
     RECT  0.103 20.97 0.347 20.988 ;
     RECT  0.211 25.326 0.347 25.344 ;
     RECT  0.103 46.548 0.347 46.566 ;
     RECT  0.139 61.434 0.347 61.452 ;
     RECT  0.103 14.112 0.383 14.13 ;
     RECT  0.319 31.806 0.419 31.824 ;
     RECT  0.535 15.804 0.571 15.822 ;
     RECT  0.203 20.088 1.147 20.106 ;
     RECT  0.571 33.12 1.147 33.138 ;
     RECT  0.535 60.39 1.147 60.408 ;
     RECT  1.147 20.088 1.175 20.178 ;
     RECT  1.147 33.12 1.175 33.372 ;
     RECT  1.147 10.026 1.183 10.044 ;
     RECT  0.571 15.606 1.183 15.822 ;
     RECT  1.175 20.16 1.183 20.178 ;
     RECT  1.147 49.716 1.183 49.734 ;
     RECT  1.147 53.334 1.183 53.352 ;
     RECT  1.183 20.16 1.219 20.304 ;
     RECT  1.183 32.31 1.219 32.328 ;
     RECT  0.103 39.636 1.219 39.654 ;
     RECT  1.183 40.41 1.219 40.428 ;
     RECT  1.147 60.39 1.247 60.606 ;
     RECT  1.247 60.39 1.255 60.534 ;
     RECT  1.147 24.606 1.283 24.696 ;
     RECT  1.183 42.534 1.319 42.552 ;
     RECT  1.183 10.026 1.327 10.494 ;
     RECT  1.147 19.314 1.355 19.332 ;
     RECT  1.219 32.238 1.355 32.328 ;
     RECT  1.219 39.636 1.355 40.428 ;
     RECT  1.399 48.438 1.435 48.456 ;
     RECT  0.239 8.514 1.651 8.532 ;
     RECT  0.103 7.596 1.687 7.614 ;
     RECT  1.651 8.514 1.687 9.036 ;
     RECT  1.651 51.408 1.687 51.426 ;
     RECT  0.823 5.166 1.723 5.184 ;
     RECT  1.327 9.828 1.723 10.494 ;
     RECT  0.103 11.286 1.723 11.304 ;
     RECT  1.327 18.036 1.723 18.054 ;
     RECT  1.327 22.626 1.723 22.644 ;
     RECT  0.571 30.348 1.723 30.366 ;
     RECT  1.175 33.354 1.723 33.372 ;
     RECT  1.147 37.602 1.723 37.62 ;
     RECT  1.147 62.136 1.723 62.154 ;
     RECT  0.103 3.276 1.759 3.294 ;
     RECT  1.723 17.316 1.759 18.324 ;
     RECT  1.723 46.044 1.759 46.062 ;
     RECT  1.183 49.716 1.759 50.274 ;
     RECT  1.147 57.348 1.795 57.366 ;
     RECT  1.759 58.356 1.795 58.374 ;
     RECT  1.687 51.408 1.903 51.696 ;
     RECT  0.103 55.926 1.903 55.944 ;
     RECT  0.571 6.048 2.047 6.066 ;
     RECT  1.759 3.276 2.083 3.564 ;
     RECT  1.903 51.408 2.119 52.074 ;
     RECT  1.183 52.956 2.119 53.352 ;
     RECT  1.723 54.846 2.119 54.864 ;
     RECT  1.903 55.926 2.119 56.556 ;
     RECT  1.795 57.348 2.119 58.374 ;
     RECT  1.903 2.268 2.16 2.286 ;
     RECT  2.083 3.114 2.16 3.564 ;
     RECT  1.723 4.626 2.16 5.184 ;
     RECT  2.047 6.048 2.16 6.606 ;
     RECT  1.687 7.596 2.16 9.036 ;
     RECT  1.723 9.828 2.16 11.304 ;
     RECT  2.119 13.806 2.16 13.824 ;
     RECT  1.183 14.886 2.16 15.822 ;
     RECT  1.759 17.316 2.16 19.062 ;
     RECT  1.219 20.16 2.16 20.844 ;
     RECT  1.723 22.086 2.16 22.644 ;
     RECT  2.155 23.436 2.16 23.454 ;
     RECT  1.283 24.606 2.16 24.624 ;
     RECT  1.147 25.686 2.16 25.704 ;
     RECT  0.535 27.648 2.16 27.666 ;
     RECT  1.759 29.268 2.16 29.286 ;
     RECT  1.723 30.078 2.16 30.366 ;
     RECT  1.723 31.698 2.16 31.716 ;
     RECT  1.723 33.354 2.16 33.948 ;
     RECT  1.723 37.332 2.16 37.62 ;
     RECT  1.355 39.636 2.16 40.284 ;
     RECT  2.155 43.506 2.16 43.524 ;
     RECT  1.759 46.044 2.16 46.296 ;
     RECT  1.435 48.438 2.16 48.654 ;
     RECT  1.759 49.626 2.16 50.274 ;
     RECT  2.119 51.408 2.16 53.352 ;
     RECT  2.119 54.846 2.16 58.374 ;
     RECT  1.255 59.886 2.16 60.534 ;
     RECT  1.723 61.866 2.16 62.154 ;
     RECT  2.16 2.151 2.587 62.649 ;
     RECT  2.299 1.116 2.731 1.134 ;
     RECT  2.587 1.881 3.307 62.649 ;
     RECT  2.731 1.071 3.343 1.134 ;
     RECT  3.307 1.881 3.343 62.802 ;
     RECT  3.343 1.071 4.603 62.802 ;
     RECT  4.603 1.071 6.719 62.874 ;
     RECT  6.719 1.962 6.827 62.874 ;
     RECT  6.827 1.962 7.043 62.766 ;
     RECT  6.719 1.071 7.259 1.17 ;
     RECT  7.043 2.106 8.707 62.766 ;
     RECT  8.707 2.034 9.499 62.766 ;
     RECT  7.259 1.071 10.931 1.134 ;
     RECT  9.499 2.034 11.003 62.838 ;
     RECT  10.931 1.116 11.255 1.134 ;
     RECT  11.003 2.034 12.443 62.73 ;
     RECT  12.443 2.034 14.099 62.694 ;
     RECT  14.099 2.106 14.827 62.694 ;
     RECT  14.827 2.034 15.583 62.694 ;
     RECT  15.583 1.836 19.139 62.694 ;
     RECT  19.139 1.836 19.44 62.649 ;
     RECT  19.44 1.836 20.219 62.568 ;
     RECT  20.219 1.836 20.255 59.832 ;
     RECT  20.255 36.36 20.291 54.162 ;
     RECT  20.255 1.836 20.327 35.496 ;
     RECT  20.327 1.836 20.399 29.592 ;
     RECT  20.399 1.836 20.435 24.192 ;
     RECT  20.399 24.948 20.435 29.556 ;
     RECT  20.291 36.594 20.435 40.284 ;
     RECT  20.291 41.148 20.435 54.162 ;
     RECT  20.219 60.588 20.435 62.568 ;
     RECT  20.435 1.836 20.471 12.816 ;
     RECT  20.327 30.348 20.471 35.496 ;
     RECT  20.435 48.78 20.471 54.162 ;
     RECT  20.471 5.391 20.507 12.816 ;
     RECT  20.435 24.948 20.507 27.504 ;
     RECT  20.435 28.422 20.507 29.286 ;
     RECT  20.471 30.348 20.507 34.074 ;
     RECT  20.435 36.594 20.507 37.494 ;
     RECT  20.435 47.088 20.507 47.754 ;
     RECT  20.471 49.05 20.507 54.162 ;
     RECT  20.255 54.99 20.507 59.832 ;
     RECT  20.435 13.68 20.543 24.192 ;
     RECT  20.507 25.326 20.543 27.504 ;
     RECT  20.507 30.348 20.543 32.49 ;
     RECT  20.507 33.39 20.543 33.984 ;
     RECT  20.435 38.286 20.543 40.284 ;
     RECT  20.435 41.184 20.543 46.062 ;
     RECT  20.507 47.16 20.543 47.754 ;
     RECT  20.507 52.56 20.543 54.162 ;
     RECT  20.507 55.53 20.543 59.832 ;
     RECT  20.435 60.966 20.543 62.568 ;
     RECT  20.507 8.244 20.579 12.816 ;
     RECT  20.543 32.472 21.371 32.49 ;
     RECT  20.579 8.244 21.407 9.918 ;
     RECT  20.543 14.994 21.407 15.588 ;
     RECT  20.543 20.628 21.407 24.192 ;
     RECT  20.543 52.56 21.407 53.316 ;
     RECT  20.471 1.836 21.443 4.554 ;
     RECT  20.507 5.391 21.443 7.254 ;
     RECT  21.407 8.244 21.443 9.882 ;
     RECT  20.579 10.71 21.443 12.816 ;
     RECT  21.407 14.994 21.443 15.552 ;
     RECT  21.407 22.086 21.443 24.192 ;
     RECT  20.543 25.83 21.443 27.504 ;
     RECT  20.543 38.286 21.443 40.086 ;
     RECT  20.543 41.184 21.443 45.522 ;
     RECT  20.543 47.358 21.443 47.754 ;
     RECT  21.407 52.56 21.443 52.884 ;
     RECT  21.443 2.106 21.479 4.554 ;
     RECT  21.443 6.084 21.479 7.254 ;
     RECT  21.443 8.244 21.479 9.576 ;
     RECT  20.543 13.68 21.479 14.004 ;
     RECT  20.543 16.344 21.479 19.566 ;
     RECT  21.407 20.628 21.479 21.294 ;
     RECT  21.443 22.086 21.479 22.536 ;
     RECT  21.443 26.604 21.479 27.504 ;
     RECT  20.543 30.348 21.479 31.554 ;
     RECT  20.507 37.17 21.479 37.494 ;
     RECT  21.443 38.286 21.479 38.574 ;
     RECT  21.443 41.184 21.479 45.288 ;
     RECT  20.507 49.05 21.479 51.534 ;
     RECT  21.443 52.56 21.479 52.848 ;
     RECT  20.543 55.998 21.479 59.832 ;
     RECT  20.543 61.164 21.479 62.568 ;
     RECT  21.479 2.106 21.515 2.124 ;
     RECT  21.479 3.114 21.515 4.104 ;
     RECT  21.479 6.084 21.515 7.182 ;
     RECT  21.479 8.244 21.515 8.604 ;
     RECT  21.479 9.558 21.515 9.576 ;
     RECT  21.443 10.908 21.515 12.816 ;
     RECT  21.479 13.68 21.515 13.698 ;
     RECT  21.443 14.994 21.515 15.012 ;
     RECT  21.479 16.344 21.515 16.83 ;
     RECT  21.479 18.036 21.515 19.566 ;
     RECT  21.479 20.628 21.515 21.222 ;
     RECT  21.479 22.32 21.515 22.338 ;
     RECT  21.443 23.436 21.515 24.192 ;
     RECT  21.443 25.83 21.515 25.848 ;
     RECT  21.479 26.766 21.515 27.504 ;
     RECT  20.507 28.566 21.515 29.016 ;
     RECT  21.479 30.348 21.515 30.366 ;
     RECT  21.479 31.428 21.515 31.446 ;
     RECT  20.543 33.39 21.515 33.714 ;
     RECT  20.471 35.046 21.515 35.496 ;
     RECT  21.479 37.17 21.515 37.188 ;
     RECT  21.479 38.556 21.515 38.574 ;
     RECT  21.443 39.564 21.515 40.086 ;
     RECT  21.479 41.22 21.515 43.056 ;
     RECT  21.479 43.956 21.515 45.288 ;
     RECT  21.443 47.736 21.515 47.754 ;
     RECT  21.479 49.05 21.515 51.498 ;
     RECT  21.479 52.56 21.515 52.578 ;
     RECT  21.479 55.998 21.515 56.664 ;
     RECT  21.479 57.654 21.515 58.284 ;
     RECT  21.479 59.076 21.515 59.832 ;
     RECT  21.479 61.164 21.515 61.794 ;
     RECT  21.479 62.55 21.515 62.568 ;
    LAYER M3 ;
     RECT  5.904 0.012 5.922 0.125 ;
     RECT  17.244 0.619 17.262 0.715 ;
     RECT  7.164 0.811 7.182 0.955 ;
     RECT  17.244 0.715 17.622 0.955 ;
     RECT  3.276 0.715 3.294 1.066 ;
     RECT  2.736 1.066 3.294 1.111 ;
     RECT  10.908 1.066 10.926 1.111 ;
     RECT  6.804 0.955 7.182 1.147 ;
     RECT  19.368 0.811 19.386 1.147 ;
     RECT  20.448 1.051 20.466 1.147 ;
     RECT  6.732 1.147 7.254 1.243 ;
     RECT  6.048 1.243 7.254 1.435 ;
     RECT  21.384 1.243 21.402 1.435 ;
     RECT  2.304 1.111 3.294 1.627 ;
     RECT  21.384 1.435 21.438 1.627 ;
     RECT  4.464 1.051 4.482 1.723 ;
     RECT  1.908 1.627 3.294 1.759 ;
     RECT  4.284 1.723 4.482 1.795 ;
     RECT  4.14 1.795 4.482 1.819 ;
     RECT  15.3 0.523 15.318 1.831 ;
     RECT  16.272 1.531 16.29 1.831 ;
     RECT  4.14 1.819 4.518 1.876 ;
     RECT  5.256 1.147 5.274 1.876 ;
     RECT  19.368 1.147 20.466 1.904 ;
     RECT  20.448 1.904 20.466 1.915 ;
     RECT  4.14 1.876 5.274 1.921 ;
     RECT  6.048 1.435 7.398 1.921 ;
     RECT  1.908 1.759 3.366 1.957 ;
     RECT  4.14 1.921 7.398 1.957 ;
     RECT  0.108 0.619 0.126 1.963 ;
     RECT  17.064 0.955 17.622 1.993 ;
     RECT  0.108 1.963 0.162 2.011 ;
     RECT  17.064 1.993 18.018 2.011 ;
     RECT  8.496 1.339 8.514 2.029 ;
     RECT  15.3 1.831 16.29 2.029 ;
     RECT  17.064 2.011 18.594 2.029 ;
     RECT  9.9 2.029 10.134 2.101 ;
     RECT  12.204 2.059 12.222 2.101 ;
     RECT  14.076 2.029 14.094 2.101 ;
     RECT  14.832 2.029 18.594 2.101 ;
     RECT  21.384 1.627 21.51 2.129 ;
     RECT  1.908 1.957 7.398 2.143 ;
     RECT  8.496 2.029 8.73 2.143 ;
     RECT  9.828 2.101 10.134 2.143 ;
     RECT  10.908 1.111 11.25 2.143 ;
     RECT  12.204 2.101 12.654 2.143 ;
     RECT  14.076 2.101 18.594 2.143 ;
     RECT  19.368 1.904 19.674 2.143 ;
     RECT  9.828 2.143 11.25 2.293 ;
     RECT  1.908 2.143 8.73 2.299 ;
     RECT  1.908 2.299 9.054 2.335 ;
     RECT  9.828 2.293 11.286 2.335 ;
     RECT  21.384 2.129 21.474 2.363 ;
     RECT  12.204 2.143 13.305 2.413 ;
     RECT  14.076 2.143 19.674 2.413 ;
     RECT  1.908 2.335 11.286 2.539 ;
     RECT  1.728 2.539 11.286 2.569 ;
     RECT  21.42 2.363 21.474 2.633 ;
     RECT  12.204 2.413 19.674 2.635 ;
     RECT  20.448 1.915 20.502 2.635 ;
     RECT  1.728 2.569 11.466 2.641 ;
     RECT  12.204 2.635 20.502 2.641 ;
     RECT  0.108 2.011 0.846 2.923 ;
     RECT  1.728 2.641 20.502 2.923 ;
     RECT  21.456 2.633 21.474 2.923 ;
     RECT  0.108 2.923 20.502 3.053 ;
     RECT  0.108 3.053 0.846 3.299 ;
     RECT  1.728 3.053 20.502 3.569 ;
     RECT  14.688 3.569 20.502 3.911 ;
     RECT  14.688 3.911 20.466 3.983 ;
     RECT  16.992 3.983 20.466 4.019 ;
     RECT  21.456 2.923 21.51 4.109 ;
     RECT  0.144 3.299 0.846 4.315 ;
     RECT  1.728 3.569 13.734 4.387 ;
     RECT  14.688 3.983 16.254 4.387 ;
     RECT  21.456 4.109 21.474 4.559 ;
     RECT  1.728 4.387 16.254 4.649 ;
     RECT  2.268 4.649 16.254 5.071 ;
     RECT  17.028 4.019 20.466 5.071 ;
     RECT  2.268 5.071 20.466 5.227 ;
     RECT  0.108 4.315 0.846 5.323 ;
     RECT  21.492 5.035 21.51 5.323 ;
     RECT  21.456 5.323 21.51 5.386 ;
     RECT  2.268 5.227 20.502 5.515 ;
     RECT  2.052 5.515 20.502 5.531 ;
     RECT  19.872 5.531 20.502 5.567 ;
     RECT  2.052 5.531 19.134 5.597 ;
     RECT  0.108 5.323 1.17 5.611 ;
     RECT  2.052 5.597 14.058 5.611 ;
     RECT  14.832 5.597 19.134 5.639 ;
     RECT  21.42 5.386 21.51 5.707 ;
     RECT  21.384 5.707 21.51 5.803 ;
     RECT  20.412 5.567 20.502 5.899 ;
     RECT  21.348 5.803 21.51 5.995 ;
     RECT  0.108 5.611 14.058 6.071 ;
     RECT  16.992 5.639 19.134 6.071 ;
     RECT  21.312 5.995 21.51 6.139 ;
     RECT  1.152 6.071 14.058 6.221 ;
     RECT  20.412 5.899 20.538 6.331 ;
     RECT  21.276 6.139 21.51 6.377 ;
     RECT  1.656 6.221 14.058 6.421 ;
     RECT  14.832 5.639 16.197 6.421 ;
     RECT  21.312 6.377 21.51 6.449 ;
     RECT  1.656 6.421 16.197 6.571 ;
     RECT  16.992 6.071 19.098 6.571 ;
     RECT  19.908 6.331 20.538 6.683 ;
     RECT  1.656 6.571 19.098 6.809 ;
     RECT  14.832 6.809 16.197 6.845 ;
     RECT  16.992 6.809 19.098 7.087 ;
     RECT  19.908 6.683 20.502 7.087 ;
     RECT  16.992 7.087 20.502 7.115 ;
     RECT  1.656 6.809 13.95 7.147 ;
     RECT  21.456 6.449 21.51 7.259 ;
     RECT  14.832 6.845 14.958 7.385 ;
     RECT  1.152 7.147 13.95 7.493 ;
     RECT  0.108 6.071 0.342 7.619 ;
     RECT  1.152 7.493 13.77 7.619 ;
     RECT  14.832 7.385 14.922 7.771 ;
     RECT  17.28 7.115 20.502 8.041 ;
     RECT  0.324 7.619 0.342 8.107 ;
     RECT  21.492 7.259 21.51 8.107 ;
     RECT  17.172 8.041 20.502 8.131 ;
     RECT  14.508 7.771 14.922 8.239 ;
     RECT  14.508 8.239 14.994 8.339 ;
     RECT  17.136 8.131 20.502 8.339 ;
     RECT  1.152 7.619 13.734 8.437 ;
     RECT  14.508 8.339 14.886 8.437 ;
     RECT  0.324 8.107 0.378 8.491 ;
     RECT  0.108 8.491 0.378 8.537 ;
     RECT  17.136 8.339 20.43 8.545 ;
     RECT  0.144 8.537 0.378 8.621 ;
     RECT  16.992 8.545 20.43 8.699 ;
     RECT  16.992 8.699 19.134 8.735 ;
     RECT  15.915 6.845 16.197 8.851 ;
     RECT  19.908 8.699 20.43 9.041 ;
     RECT  0.252 8.621 0.378 9.115 ;
     RECT  1.152 8.437 14.886 9.121 ;
     RECT  1.152 9.121 15.03 9.239 ;
     RECT  21.456 8.107 21.51 9.307 ;
     RECT  1.152 9.239 14.958 9.311 ;
     RECT  0.252 9.115 0.414 9.341 ;
     RECT  21.42 9.307 21.51 9.403 ;
     RECT  0.252 9.341 0.378 9.451 ;
     RECT  21.384 9.403 21.51 9.581 ;
     RECT  17.28 8.735 19.134 9.595 ;
     RECT  19.908 9.041 20.394 9.595 ;
     RECT  0.144 9.451 0.378 9.629 ;
     RECT  15.915 8.851 16.254 9.661 ;
     RECT  0.324 9.629 0.342 9.725 ;
     RECT  17.28 9.595 20.394 9.787 ;
     RECT  17.28 9.787 20.502 9.883 ;
     RECT  17.28 9.883 20.538 9.959 ;
     RECT  15.915 9.661 16.542 10.021 ;
     RECT  17.28 9.959 19.386 10.021 ;
     RECT  15.915 10.021 19.386 10.121 ;
     RECT  20.304 9.959 20.538 10.123 ;
     RECT  1.152 9.311 14.85 10.427 ;
     RECT  21.384 9.581 21.438 10.507 ;
     RECT  20.304 10.123 20.574 10.589 ;
     RECT  21.348 10.507 21.438 10.603 ;
     RECT  1.152 10.427 14.058 10.859 ;
     RECT  20.304 10.589 20.466 10.891 ;
     RECT  15.915 10.121 19.098 10.925 ;
     RECT  15.915 10.925 19.026 10.931 ;
     RECT  1.152 10.859 11.61 10.967 ;
     RECT  21.348 10.603 21.51 10.967 ;
     RECT  19.908 10.891 20.466 10.987 ;
     RECT  21.42 10.967 21.51 11.003 ;
     RECT  19.872 10.987 20.466 11.083 ;
     RECT  12.492 10.859 14.058 11.129 ;
     RECT  19.836 11.083 20.466 11.201 ;
     RECT  1.152 10.967 1.278 11.213 ;
     RECT  14.832 10.427 14.85 11.227 ;
     RECT  21.456 11.003 21.51 11.273 ;
     RECT  1.152 11.213 1.17 11.309 ;
     RECT  19.872 11.201 20.466 11.323 ;
     RECT  14.832 11.227 14.886 11.407 ;
     RECT  15.915 10.931 18.954 11.435 ;
     RECT  0.108 11.281 0.126 11.515 ;
     RECT  14.796 11.407 14.886 11.543 ;
     RECT  0.108 11.515 0.306 11.693 ;
     RECT  2.232 10.967 11.61 11.713 ;
     RECT  12.492 11.129 13.878 11.713 ;
     RECT  14.832 11.543 14.886 11.713 ;
     RECT  0.108 11.693 0.234 11.741 ;
     RECT  2.232 11.713 13.878 11.741 ;
     RECT  14.832 11.713 14.922 11.849 ;
     RECT  0.144 11.741 0.162 11.981 ;
     RECT  2.268 11.741 13.878 11.981 ;
     RECT  16.956 11.435 18.954 12.019 ;
     RECT  15.915 11.435 16.197 12.181 ;
     RECT  16.956 12.019 19.026 12.181 ;
     RECT  12.132 11.981 13.878 12.283 ;
     RECT  15.915 12.181 19.026 12.379 ;
     RECT  19.872 11.323 20.502 12.379 ;
     RECT  15.915 12.379 20.502 12.479 ;
     RECT  12.132 12.283 14.094 12.515 ;
     RECT  16.992 12.479 20.502 12.551 ;
     RECT  12.384 12.515 14.094 12.559 ;
     RECT  14.832 11.849 14.886 12.559 ;
     RECT  12.384 12.559 14.886 12.653 ;
     RECT  2.268 11.981 11.358 12.715 ;
     RECT  13.215 12.653 14.886 12.821 ;
     RECT  14.832 12.821 14.886 12.859 ;
     RECT  14.832 12.859 14.958 13.037 ;
     RECT  14.832 13.037 14.886 13.055 ;
     RECT  1.152 12.811 1.17 13.085 ;
     RECT  2.124 12.715 11.358 13.171 ;
     RECT  0.144 13.195 0.162 13.373 ;
     RECT  2.124 13.171 11.538 13.405 ;
     RECT  1.188 13.099 1.278 13.483 ;
     RECT  1.188 13.483 1.314 13.531 ;
     RECT  2.124 13.405 12.042 13.531 ;
     RECT  13.215 12.821 14.094 13.531 ;
     RECT  21.492 11.273 21.51 13.579 ;
     RECT  16.992 12.551 20.43 13.675 ;
     RECT  21.456 13.579 21.51 13.703 ;
     RECT  1.188 13.531 12.042 13.711 ;
     RECT  13.104 13.531 14.094 13.711 ;
     RECT  16.92 13.675 20.43 13.771 ;
     RECT  1.188 13.711 14.094 13.819 ;
     RECT  0.18 13.771 0.27 13.867 ;
     RECT  1.152 13.819 14.094 13.867 ;
     RECT  0.18 13.867 14.094 13.873 ;
     RECT  14.832 13.055 14.85 13.873 ;
     RECT  0.18 13.873 14.886 14.107 ;
     RECT  0.108 14.107 14.886 14.144 ;
     RECT  0.144 14.144 14.886 14.171 ;
     RECT  21.456 13.703 21.474 14.491 ;
     RECT  15.915 12.479 16.197 14.521 ;
     RECT  16.92 13.771 20.502 14.521 ;
     RECT  15.915 14.521 20.538 14.621 ;
     RECT  21.456 14.491 21.51 14.683 ;
     RECT  15.915 14.621 20.502 14.711 ;
     RECT  17.28 14.711 20.502 14.717 ;
     RECT  21.42 14.683 21.51 14.971 ;
     RECT  0.144 14.171 14.85 15.223 ;
     RECT  17.316 14.717 20.502 15.287 ;
     RECT  21.384 14.971 21.51 15.593 ;
     RECT  0.144 15.223 14.886 15.629 ;
     RECT  13.215 15.629 14.886 15.727 ;
     RECT  19.872 15.287 20.502 15.787 ;
     RECT  13.215 15.727 15.03 15.827 ;
     RECT  13.215 15.827 14.958 15.917 ;
     RECT  17.316 15.287 19.026 16.141 ;
     RECT  0.144 15.629 12.438 16.205 ;
     RECT  17.172 16.141 19.026 16.259 ;
     RECT  19.872 15.787 20.538 16.363 ;
     RECT  17.244 16.259 19.026 16.501 ;
     RECT  1.152 16.205 12.438 16.537 ;
     RECT  13.215 15.917 14.094 16.537 ;
     RECT  21.42 15.593 21.51 16.601 ;
     RECT  14.832 15.917 14.958 16.609 ;
     RECT  1.152 16.537 14.094 16.681 ;
     RECT  14.832 16.609 14.994 16.681 ;
     RECT  17.244 16.501 19.062 16.699 ;
     RECT  19.836 16.363 20.538 16.699 ;
     RECT  0.144 16.205 0.342 16.891 ;
     RECT  17.244 16.699 20.538 16.943 ;
     RECT  1.152 16.681 14.994 16.979 ;
     RECT  19.836 16.943 20.538 17.021 ;
     RECT  19.836 17.021 20.502 17.105 ;
     RECT  17.244 16.943 19.098 17.113 ;
     RECT  17.1 17.113 19.098 17.117 ;
     RECT  0.108 16.891 0.342 17.213 ;
     RECT  21.456 16.601 21.51 17.447 ;
     RECT  0.108 17.213 0.234 17.453 ;
     RECT  0.108 17.453 0.162 17.645 ;
     RECT  1.152 16.979 14.958 17.933 ;
     RECT  17.1 17.117 19.026 17.995 ;
     RECT  19.836 17.105 20.43 17.995 ;
     RECT  17.1 17.995 20.502 18.031 ;
     RECT  16.992 18.031 20.502 18.149 ;
     RECT  14.832 17.933 14.958 18.301 ;
     RECT  0.108 17.645 0.126 18.379 ;
     RECT  17.136 18.149 20.502 18.419 ;
     RECT  0.108 18.379 0.162 18.427 ;
     RECT  1.152 17.933 14.022 18.427 ;
     RECT  17.244 18.419 20.502 18.491 ;
     RECT  14.832 18.301 15.102 18.599 ;
     RECT  17.244 18.491 19.458 18.701 ;
     RECT  20.196 18.491 20.502 18.725 ;
     RECT  14.832 18.599 15.03 18.797 ;
     RECT  14.832 18.797 14.85 18.869 ;
     RECT  20.196 18.725 20.466 19.031 ;
     RECT  0.108 18.427 14.022 19.067 ;
     RECT  2.196 19.067 14.022 19.301 ;
     RECT  17.316 18.701 19.458 19.387 ;
     RECT  20.196 19.031 20.43 19.387 ;
     RECT  0.108 19.067 1.35 19.709 ;
     RECT  17.316 19.387 20.43 19.921 ;
     RECT  1.152 19.709 1.35 20.059 ;
     RECT  2.232 19.301 14.022 20.059 ;
     RECT  16.992 19.921 20.43 20.059 ;
     RECT  1.152 20.059 14.022 20.191 ;
     RECT  14.832 20.011 14.85 20.191 ;
     RECT  16.992 20.059 20.538 20.219 ;
     RECT  21.492 17.447 21.51 20.347 ;
     RECT  17.172 20.219 20.538 20.381 ;
     RECT  1.152 20.191 14.85 20.489 ;
     RECT  21.312 20.347 21.51 20.525 ;
     RECT  17.172 20.381 19.314 20.687 ;
     RECT  14.832 20.489 14.85 20.731 ;
     RECT  20.304 20.381 20.538 20.813 ;
     RECT  14.832 20.731 14.994 20.885 ;
     RECT  0.108 19.709 0.342 20.993 ;
     RECT  0.144 20.993 0.342 21.005 ;
     RECT  14.832 20.885 14.922 21.029 ;
     RECT  17.172 20.687 19.134 21.091 ;
     RECT  15.915 14.711 16.197 21.199 ;
     RECT  17.064 21.091 19.134 21.199 ;
     RECT  20.304 20.813 20.43 21.259 ;
     RECT  0.144 21.005 0.234 21.389 ;
     RECT  15.915 21.199 19.134 21.389 ;
     RECT  0.144 21.389 0.162 21.437 ;
     RECT  16.992 21.389 18.897 21.437 ;
     RECT  21.384 20.525 21.51 21.451 ;
     RECT  21.348 21.451 21.51 21.569 ;
     RECT  19.872 21.259 20.43 21.787 ;
     RECT  1.152 20.489 14.022 22.109 ;
     RECT  2.16 22.109 14.022 22.253 ;
     RECT  17.064 21.437 18.897 22.279 ;
     RECT  21.456 21.569 21.51 22.343 ;
     RECT  17.064 22.279 18.954 22.351 ;
     RECT  21.456 22.343 21.474 22.363 ;
     RECT  21.42 22.363 21.474 22.459 ;
     RECT  2.16 22.253 12.186 22.541 ;
     RECT  21.384 22.459 21.474 22.541 ;
     RECT  21.384 22.541 21.438 22.577 ;
     RECT  14.832 21.029 14.85 22.603 ;
     RECT  14.832 22.603 14.886 22.621 ;
     RECT  1.152 22.109 1.35 22.649 ;
     RECT  14.832 22.621 14.922 22.775 ;
     RECT  21.42 22.577 21.438 22.883 ;
     RECT  13.104 22.253 14.022 22.987 ;
     RECT  19.872 21.787 20.502 23.081 ;
     RECT  17.064 22.351 19.134 23.083 ;
     RECT  14.832 22.775 14.886 23.117 ;
     RECT  16.992 23.083 19.134 23.125 ;
     RECT  19.872 23.081 20.466 23.125 ;
     RECT  0.144 22.219 0.162 23.131 ;
     RECT  0.144 23.131 0.234 23.213 ;
     RECT  16.992 23.125 20.466 23.279 ;
     RECT  0.18 23.213 0.234 23.309 ;
     RECT  19.836 23.279 20.466 23.351 ;
     RECT  13.068 22.987 14.022 23.357 ;
     RECT  1.152 22.649 1.206 23.371 ;
     RECT  2.16 22.541 11.718 23.459 ;
     RECT  1.152 23.371 1.278 23.467 ;
     RECT  2.268 23.459 11.718 23.563 ;
     RECT  13.104 23.357 14.022 23.563 ;
     RECT  14.832 23.117 14.85 23.563 ;
     RECT  15.915 21.389 16.197 23.611 ;
     RECT  16.992 23.279 18.99 23.611 ;
     RECT  13.104 23.563 14.85 23.837 ;
     RECT  1.152 23.467 1.458 23.885 ;
     RECT  2.268 23.563 11.97 23.971 ;
     RECT  0.18 23.309 0.198 24.043 ;
     RECT  15.915 23.611 18.99 24.043 ;
     RECT  19.836 23.351 20.43 24.043 ;
     RECT  21.492 23.431 21.51 24.197 ;
     RECT  2.268 23.971 12.006 24.331 ;
     RECT  15.915 24.043 20.43 24.359 ;
     RECT  2.268 24.331 12.222 24.461 ;
     RECT  1.152 23.885 1.314 24.509 ;
     RECT  0.144 24.043 0.198 24.571 ;
     RECT  1.152 24.509 1.278 24.571 ;
     RECT  13.215 23.837 14.85 24.667 ;
     RECT  16.992 24.359 20.43 24.667 ;
     RECT  0.144 24.571 1.278 24.701 ;
     RECT  16.992 24.667 20.502 24.941 ;
     RECT  19.8 24.941 20.502 24.955 ;
     RECT  0.144 24.701 1.17 24.989 ;
     RECT  16.992 24.941 18.918 24.989 ;
     RECT  12.996 24.667 14.85 25.003 ;
     RECT  19.8 24.955 20.538 25.007 ;
     RECT  19.836 25.007 20.538 25.313 ;
     RECT  17.1 24.989 18.918 25.439 ;
     RECT  2.268 24.461 11.718 25.511 ;
     RECT  2.304 25.511 11.718 25.591 ;
     RECT  12.888 25.003 14.85 25.591 ;
     RECT  2.304 25.591 14.85 25.613 ;
     RECT  0.216 24.989 1.17 25.675 ;
     RECT  17.316 25.439 18.918 25.709 ;
     RECT  17.46 25.709 18.918 25.753 ;
     RECT  17.46 25.753 19.026 25.789 ;
     RECT  2.304 25.613 14.022 25.805 ;
     RECT  21.492 25.435 21.51 25.852 ;
     RECT  0.216 25.675 1.278 25.867 ;
     RECT  19.908 25.313 20.538 25.889 ;
     RECT  14.832 25.613 14.85 25.963 ;
     RECT  21.456 25.852 21.51 25.963 ;
     RECT  12.744 25.805 14.022 26.015 ;
     RECT  21.42 25.963 21.51 26.155 ;
     RECT  17.46 25.789 19.098 26.251 ;
     RECT  21.384 26.155 21.51 26.251 ;
     RECT  12.78 26.015 14.022 26.285 ;
     RECT  0.144 25.867 1.278 26.347 ;
     RECT  21.348 26.251 21.51 26.357 ;
     RECT  21.384 26.357 21.51 26.393 ;
     RECT  2.304 25.805 11.646 26.401 ;
     RECT  17.46 26.251 19.134 26.401 ;
     RECT  19.908 25.889 20.502 26.401 ;
     RECT  15.915 24.359 16.197 26.491 ;
     RECT  17.46 26.401 20.502 26.491 ;
     RECT  2.268 26.401 11.646 26.525 ;
     RECT  0.144 26.347 1.386 26.621 ;
     RECT  0.144 26.621 1.314 26.669 ;
     RECT  14.832 25.963 14.886 26.699 ;
     RECT  0.324 26.669 1.314 26.765 ;
     RECT  15.915 26.491 20.502 26.789 ;
     RECT  21.42 26.393 21.51 26.933 ;
     RECT  12.852 26.285 14.022 26.941 ;
     RECT  14.832 26.699 14.85 26.941 ;
     RECT  12.852 26.941 14.85 27.059 ;
     RECT  17.1 26.789 20.502 27.139 ;
     RECT  2.304 26.525 11.646 27.259 ;
     RECT  17.1 27.139 20.538 27.293 ;
     RECT  12.852 27.059 13.698 27.451 ;
     RECT  2.196 27.259 11.646 27.499 ;
     RECT  12.42 27.451 13.698 27.499 ;
     RECT  17.1 27.293 20.43 27.599 ;
     RECT  14.544 27.059 14.85 27.607 ;
     RECT  0.324 26.765 1.17 27.629 ;
     RECT  17.28 27.599 20.43 27.629 ;
     RECT  0.324 27.629 0.558 27.643 ;
     RECT  0.144 27.643 0.558 27.671 ;
     RECT  14.544 27.607 14.886 27.743 ;
     RECT  0.144 27.671 0.342 27.773 ;
     RECT  0.144 27.773 0.234 27.869 ;
     RECT  0.144 27.869 0.162 27.917 ;
     RECT  14.58 27.743 14.886 27.917 ;
     RECT  14.688 27.917 14.886 27.95 ;
     RECT  17.424 27.629 20.43 28.139 ;
     RECT  2.196 27.499 13.698 28.219 ;
     RECT  14.724 27.95 14.886 28.253 ;
     RECT  17.46 28.139 20.43 28.267 ;
     RECT  2.196 28.219 13.77 28.363 ;
     RECT  21.492 26.933 21.51 28.363 ;
     RECT  17.46 28.267 20.502 28.517 ;
     RECT  1.728 28.363 13.77 28.687 ;
     RECT  14.724 28.253 14.85 28.687 ;
     RECT  0.324 28.651 0.342 28.699 ;
     RECT  1.728 28.687 14.85 28.699 ;
     RECT  21.456 28.363 21.51 28.823 ;
     RECT  0.216 28.699 0.342 28.939 ;
     RECT  1.26 28.699 14.85 28.939 ;
     RECT  15.915 26.789 16.197 28.957 ;
     RECT  21.492 28.823 21.51 29.021 ;
     RECT  15.915 28.957 16.65 29.191 ;
     RECT  0.216 28.939 14.85 29.219 ;
     RECT  0.216 29.219 13.842 29.275 ;
     RECT  17.64 28.517 20.502 29.291 ;
     RECT  15.915 29.191 16.794 29.299 ;
     RECT  17.64 29.291 20.43 29.299 ;
     RECT  14.832 29.219 14.85 29.371 ;
     RECT  14.832 29.371 14.886 29.641 ;
     RECT  14.832 29.641 14.994 29.903 ;
     RECT  14.832 29.903 14.958 29.939 ;
     RECT  0.144 29.275 13.842 30.125 ;
     RECT  0.216 30.125 13.842 30.173 ;
     RECT  0.576 30.173 13.842 30.371 ;
     RECT  21.492 30.235 21.51 30.371 ;
     RECT  1.152 30.371 13.842 30.407 ;
     RECT  12.564 30.407 13.842 30.571 ;
     RECT  15.915 29.299 20.43 30.715 ;
     RECT  12.564 30.571 13.878 30.749 ;
     RECT  12.996 30.749 13.878 30.911 ;
     RECT  15.915 30.715 20.502 30.983 ;
     RECT  0.144 30.907 0.162 31.085 ;
     RECT  1.152 30.407 11.646 31.133 ;
     RECT  21.456 30.619 21.474 31.147 ;
     RECT  15.915 30.983 18.99 31.181 ;
     RECT  14.832 29.939 14.886 31.225 ;
     RECT  15.915 31.181 16.197 31.225 ;
     RECT  19.836 30.983 20.502 31.253 ;
     RECT  13.032 30.911 13.878 31.289 ;
     RECT  13.215 31.289 13.878 31.351 ;
     RECT  14.832 31.225 16.197 31.351 ;
     RECT  21.456 31.147 21.51 31.451 ;
     RECT  1.728 31.133 11.646 31.483 ;
     RECT  1.728 31.483 11.97 31.531 ;
     RECT  21.456 31.451 21.474 31.559 ;
     RECT  1.728 31.531 12.114 31.721 ;
     RECT  21.312 31.627 21.438 31.757 ;
     RECT  0.324 31.627 0.342 31.771 ;
     RECT  13.215 31.351 16.197 31.829 ;
     RECT  0.324 31.771 0.414 31.867 ;
     RECT  2.268 31.721 12.114 31.891 ;
     RECT  21.348 31.757 21.438 31.901 ;
     RECT  2.268 31.891 12.402 32.011 ;
     RECT  13.215 31.829 14.886 32.011 ;
     RECT  19.872 31.253 20.502 32.063 ;
     RECT  19.908 32.063 20.502 32.197 ;
     RECT  0.324 31.867 0.594 32.203 ;
     RECT  17.064 31.181 18.99 32.341 ;
     RECT  17.064 32.341 19.026 32.347 ;
     RECT  0.144 32.203 1.35 32.381 ;
     RECT  0.216 32.381 1.35 32.477 ;
     RECT  21.348 31.901 21.366 32.495 ;
     RECT  0.324 32.477 1.35 32.539 ;
     RECT  2.268 32.011 14.886 32.603 ;
     RECT  19.908 32.197 20.538 32.669 ;
     RECT  17.064 32.347 19.098 32.737 ;
     RECT  12.96 32.603 14.886 32.827 ;
     RECT  16.992 32.737 19.098 32.837 ;
     RECT  0.324 32.539 1.386 32.875 ;
     RECT  2.268 32.603 12.15 32.875 ;
     RECT  17.1 32.837 19.098 32.881 ;
     RECT  19.908 32.669 20.502 32.881 ;
     RECT  12.96 32.827 14.922 33.005 ;
     RECT  17.1 32.881 20.502 33.053 ;
     RECT  0.324 32.875 12.15 33.143 ;
     RECT  12.96 33.005 14.85 33.421 ;
     RECT  12.924 33.421 14.85 33.647 ;
     RECT  21.492 32.923 21.51 33.719 ;
     RECT  13.215 33.647 14.85 33.889 ;
     RECT  0.144 33.211 0.234 33.916 ;
     RECT  1.152 33.143 12.15 33.953 ;
     RECT  19.872 33.053 20.502 33.961 ;
     RECT  19.872 33.961 20.538 34.061 ;
     RECT  19.872 34.061 20.502 34.079 ;
     RECT  0.108 33.916 0.234 34.157 ;
     RECT  17.1 33.053 19.026 34.157 ;
     RECT  0.144 34.157 0.234 34.397 ;
     RECT  0.216 34.397 0.234 34.507 ;
     RECT  13.215 33.889 14.886 34.603 ;
     RECT  17.136 34.157 19.026 34.603 ;
     RECT  19.872 34.079 20.466 34.603 ;
     RECT  1.152 33.953 1.386 34.685 ;
     RECT  1.152 34.685 1.314 34.733 ;
     RECT  13.215 34.603 14.922 34.733 ;
     RECT  13.215 34.733 14.886 34.771 ;
     RECT  21.492 34.747 21.51 34.843 ;
     RECT  2.268 33.953 12.15 34.889 ;
     RECT  2.304 34.889 12.15 35.041 ;
     RECT  12.996 34.771 14.886 35.041 ;
     RECT  17.136 34.603 20.466 35.069 ;
     RECT  21.456 34.843 21.51 35.267 ;
     RECT  0.216 34.507 0.378 35.323 ;
     RECT  17.424 35.069 20.466 35.323 ;
     RECT  2.304 35.041 14.886 35.465 ;
     RECT  21.492 35.267 21.51 35.501 ;
     RECT  1.152 34.733 1.17 35.515 ;
     RECT  0.216 35.323 0.414 35.659 ;
     RECT  0.144 35.659 0.414 35.693 ;
     RECT  2.304 35.465 13.698 35.807 ;
     RECT  0.144 35.693 0.342 35.837 ;
     RECT  2.304 35.807 13.662 35.969 ;
     RECT  12.996 35.969 13.662 36.005 ;
     RECT  2.304 35.969 11.934 36.041 ;
     RECT  17.424 35.323 20.502 36.043 ;
     RECT  1.152 35.515 1.314 36.235 ;
     RECT  2.304 36.041 11.898 36.235 ;
     RECT  14.436 35.465 14.886 36.247 ;
     RECT  17.1 36.043 20.502 36.311 ;
     RECT  17.1 36.311 18.99 36.461 ;
     RECT  12.996 36.005 13.497 36.509 ;
     RECT  14.4 36.247 14.886 36.553 ;
     RECT  0.324 35.837 0.342 36.571 ;
     RECT  14.4 36.553 14.922 36.625 ;
     RECT  14.22 36.625 14.922 36.689 ;
     RECT  13.068 36.509 13.497 36.797 ;
     RECT  1.152 36.235 11.898 36.811 ;
     RECT  0.144 36.571 0.342 36.845 ;
     RECT  13.104 36.797 13.497 36.859 ;
     RECT  14.22 36.689 14.886 36.859 ;
     RECT  0.144 36.845 0.234 36.893 ;
     RECT  21.492 36.715 21.51 36.907 ;
     RECT  13.104 36.859 14.886 36.959 ;
     RECT  13.215 36.959 14.886 37.085 ;
     RECT  17.1 36.461 18.954 37.165 ;
     RECT  21.456 36.907 21.51 37.193 ;
     RECT  15.915 31.829 16.197 37.291 ;
     RECT  16.992 37.165 18.954 37.291 ;
     RECT  14.256 37.085 14.886 37.391 ;
     RECT  15.915 37.291 18.954 37.391 ;
     RECT  0.144 36.893 0.198 37.531 ;
     RECT  16.992 37.391 18.954 37.561 ;
     RECT  1.152 36.811 11.934 37.625 ;
     RECT  0.108 37.531 0.198 37.675 ;
     RECT  0.108 37.675 0.234 37.697 ;
     RECT  16.992 37.561 19.062 37.741 ;
     RECT  19.8 36.311 20.502 37.741 ;
     RECT  13.215 37.085 13.497 37.903 ;
     RECT  14.832 37.391 14.886 37.967 ;
     RECT  21.456 37.193 21.474 38.011 ;
     RECT  0.144 37.697 0.234 38.045 ;
     RECT  13.068 37.903 13.497 38.155 ;
     RECT  14.832 37.967 14.85 38.155 ;
     RECT  13.068 38.155 14.85 38.201 ;
     RECT  1.728 37.625 11.934 38.281 ;
     RECT  21.456 38.011 21.51 38.299 ;
     RECT  16.992 37.741 20.502 38.399 ;
     RECT  13.215 38.201 14.85 38.435 ;
     RECT  1.728 38.281 11.97 38.491 ;
     RECT  1.728 38.491 12.006 38.579 ;
     RECT  21.42 38.299 21.51 38.579 ;
     RECT  0.144 38.045 0.162 38.635 ;
     RECT  17.244 38.399 20.502 38.635 ;
     RECT  17.244 38.635 20.61 38.765 ;
     RECT  1.728 38.579 11.97 38.779 ;
     RECT  14.796 38.435 14.85 38.779 ;
     RECT  15.915 37.391 16.197 38.779 ;
     RECT  21.42 38.579 21.438 38.849 ;
     RECT  14.796 38.779 16.197 38.939 ;
     RECT  17.244 38.765 20.502 38.975 ;
     RECT  14.832 38.939 15.102 39.011 ;
     RECT  17.352 38.975 20.502 39.083 ;
     RECT  0.108 38.635 0.162 39.115 ;
     RECT  14.832 39.011 14.922 39.119 ;
     RECT  17.352 39.083 20.43 39.209 ;
     RECT  1.152 38.779 11.97 39.293 ;
     RECT  1.296 39.293 11.97 39.341 ;
     RECT  0.108 39.115 0.234 39.403 ;
     RECT  13.215 38.435 13.497 39.451 ;
     RECT  1.728 39.341 11.97 39.499 ;
     RECT  13.104 39.451 13.497 39.499 ;
     RECT  14.832 39.119 14.85 39.581 ;
     RECT  0.108 39.403 0.378 39.643 ;
     RECT  0.108 39.643 0.45 39.659 ;
     RECT  0.144 39.659 0.45 39.821 ;
     RECT  17.352 39.209 19.026 39.901 ;
     RECT  19.836 39.209 20.43 39.931 ;
     RECT  17.064 39.901 19.026 39.991 ;
     RECT  1.728 39.499 13.497 40.027 ;
     RECT  15.915 38.939 16.197 40.027 ;
     RECT  16.992 39.991 19.026 40.027 ;
     RECT  1.728 40.027 13.554 40.171 ;
     RECT  1.728 40.171 13.662 40.289 ;
     RECT  19.836 39.931 20.538 40.289 ;
     RECT  2.232 40.289 13.662 40.349 ;
     RECT  1.224 40.315 1.35 40.405 ;
     RECT  1.188 40.405 1.35 40.433 ;
     RECT  1.188 40.433 1.314 40.445 ;
     RECT  19.836 40.289 20.43 40.507 ;
     RECT  2.232 40.349 13.497 40.595 ;
     RECT  0.144 39.821 0.162 40.603 ;
     RECT  19.8 40.507 20.43 40.603 ;
     RECT  1.188 40.445 1.278 40.651 ;
     RECT  0.144 40.603 0.378 40.699 ;
     RECT  1.152 40.651 1.278 40.699 ;
     RECT  13.068 40.595 13.497 40.703 ;
     RECT  15.915 40.027 19.026 40.711 ;
     RECT  19.764 40.603 20.43 40.711 ;
     RECT  21.492 39.499 21.51 40.891 ;
     RECT  0.144 40.699 1.278 40.925 ;
     RECT  0.144 40.925 0.306 40.973 ;
     RECT  14.868 40.909 14.886 41.143 ;
     RECT  15.915 40.711 20.43 41.171 ;
     RECT  21.456 40.891 21.51 41.207 ;
     RECT  2.232 40.595 11.97 41.341 ;
     RECT  15.915 41.171 20.394 41.369 ;
     RECT  0.144 40.973 0.27 41.453 ;
     RECT  2.232 41.341 12.222 41.515 ;
     RECT  2.196 41.515 12.222 41.549 ;
     RECT  13.215 40.703 13.497 41.611 ;
     RECT  14.832 41.143 14.886 41.611 ;
     RECT  2.196 41.549 12.15 41.639 ;
     RECT  13.104 41.611 13.497 41.659 ;
     RECT  14.832 41.611 14.958 41.741 ;
     RECT  2.196 41.639 11.898 41.783 ;
     RECT  13.032 41.659 13.497 41.789 ;
     RECT  0.144 41.453 0.198 41.803 ;
     RECT  1.152 40.925 1.278 41.933 ;
     RECT  0.108 41.803 0.198 41.948 ;
     RECT  14.832 41.741 14.886 41.953 ;
     RECT  17.172 41.369 20.394 41.995 ;
     RECT  14.796 41.953 14.886 42.061 ;
     RECT  13.104 41.789 13.497 42.089 ;
     RECT  21.492 41.207 21.51 42.091 ;
     RECT  0.144 41.948 0.198 42.125 ;
     RECT  17.172 41.995 20.43 42.151 ;
     RECT  14.724 42.061 14.886 42.179 ;
     RECT  0.18 42.125 0.198 42.187 ;
     RECT  1.188 41.933 1.278 42.427 ;
     RECT  14.832 42.179 14.886 42.461 ;
     RECT  1.188 42.427 1.386 42.557 ;
     RECT  14.868 42.461 14.886 42.557 ;
     RECT  1.296 42.557 1.386 42.605 ;
     RECT  2.196 41.783 11.718 42.715 ;
     RECT  16.992 42.151 20.43 42.715 ;
     RECT  0.18 42.187 0.342 42.749 ;
     RECT  16.992 42.715 20.502 42.863 ;
     RECT  0.18 42.749 0.198 42.907 ;
     RECT  0.144 42.907 0.198 43.105 ;
     RECT  2.16 42.715 11.718 43.195 ;
     RECT  15.915 41.369 16.197 43.231 ;
     RECT  16.992 42.863 18.897 43.231 ;
     RECT  21.456 42.091 21.51 43.331 ;
     RECT  0.108 43.105 0.198 43.421 ;
     RECT  14.832 43.537 14.85 43.573 ;
     RECT  14.832 43.573 14.922 43.637 ;
     RECT  0.144 43.421 0.198 43.675 ;
     RECT  14.904 43.637 14.922 43.709 ;
     RECT  13.215 42.089 13.497 43.843 ;
     RECT  13.068 43.843 13.497 43.879 ;
     RECT  0.144 43.675 0.234 43.901 ;
     RECT  15.915 43.231 18.897 43.907 ;
     RECT  16.992 43.907 18.897 43.915 ;
     RECT  19.836 42.863 20.502 43.915 ;
     RECT  1.728 43.195 11.718 43.951 ;
     RECT  13.068 43.879 13.734 43.951 ;
     RECT  13.032 43.951 13.734 44.041 ;
     RECT  1.728 43.951 12.294 44.059 ;
     RECT  1.152 44.059 12.294 44.069 ;
     RECT  1.152 44.069 11.718 44.105 ;
     RECT  13.032 44.041 13.77 44.177 ;
     RECT  21.492 43.331 21.51 44.203 ;
     RECT  16.992 43.915 20.502 44.299 ;
     RECT  16.992 44.299 20.538 44.339 ;
     RECT  13.032 44.177 13.497 44.347 ;
     RECT  0.144 43.901 0.198 44.38 ;
     RECT  12.996 44.347 13.497 44.384 ;
     RECT  21.456 44.203 21.51 44.395 ;
     RECT  13.032 44.384 13.497 44.447 ;
     RECT  17.1 44.339 20.538 44.447 ;
     RECT  0.108 44.38 0.198 44.477 ;
     RECT  0.108 44.477 0.162 44.525 ;
     RECT  21.42 44.395 21.51 44.587 ;
     RECT  14.256 44.653 14.274 44.725 ;
     RECT  1.152 44.105 11.646 44.813 ;
     RECT  1.224 44.813 11.646 44.909 ;
     RECT  21.384 44.587 21.51 45.257 ;
     RECT  21.42 45.257 21.51 45.293 ;
     RECT  13.104 44.447 13.497 45.301 ;
     RECT  14.256 44.725 14.85 45.301 ;
     RECT  0.144 44.525 0.162 45.355 ;
     RECT  0.144 45.355 0.234 45.403 ;
     RECT  13.104 45.301 14.85 45.403 ;
     RECT  21.42 45.293 21.438 45.527 ;
     RECT  0.144 45.403 0.342 45.533 ;
     RECT  13.104 45.403 14.922 45.533 ;
     RECT  17.1 44.447 19.134 45.571 ;
     RECT  19.872 44.447 20.538 45.571 ;
     RECT  13.104 45.533 14.886 45.599 ;
     RECT  13.104 45.599 14.85 45.959 ;
     RECT  1.728 44.909 11.646 45.979 ;
     RECT  1.404 45.979 11.646 46.075 ;
     RECT  17.1 45.571 20.538 46.075 ;
     RECT  1.404 46.075 11.898 46.219 ;
     RECT  13.104 45.959 13.497 46.219 ;
     RECT  1.404 46.219 13.497 46.301 ;
     RECT  0.144 45.533 0.162 46.363 ;
     RECT  17.028 46.075 20.538 46.471 ;
     RECT  0.144 46.363 0.234 46.507 ;
     RECT  16.992 46.471 20.538 46.541 ;
     RECT  0.108 46.507 0.234 46.543 ;
     RECT  0.108 46.543 0.342 46.571 ;
     RECT  0.144 46.571 0.342 46.637 ;
     RECT  17.28 46.541 20.538 46.643 ;
     RECT  2.268 46.301 13.497 46.769 ;
     RECT  19.908 46.643 20.538 46.891 ;
     RECT  14.832 45.959 14.85 46.921 ;
     RECT  14.832 46.921 14.922 47.011 ;
     RECT  0.144 46.637 0.162 47.021 ;
     RECT  2.304 46.769 13.497 47.147 ;
     RECT  19.908 46.891 20.574 47.179 ;
     RECT  21.42 47.083 21.438 47.179 ;
     RECT  12.924 47.147 13.497 47.219 ;
     RECT  19.908 47.179 21.438 47.275 ;
     RECT  19.908 47.275 21.51 47.453 ;
     RECT  14.796 47.011 14.922 47.461 ;
     RECT  17.28 46.643 19.026 47.461 ;
     RECT  14.796 47.461 14.958 47.551 ;
     RECT  21.276 47.453 21.51 47.651 ;
     RECT  17.244 47.461 19.134 47.659 ;
     RECT  0.216 47.371 0.378 47.693 ;
     RECT  14.796 47.551 14.994 47.759 ;
     RECT  21.492 47.651 21.51 47.759 ;
     RECT  1.404 46.301 1.458 47.803 ;
     RECT  19.908 47.453 20.43 47.803 ;
     RECT  17.136 47.659 19.134 47.899 ;
     RECT  19.872 47.803 20.43 47.899 ;
     RECT  14.796 47.759 14.958 47.929 ;
     RECT  17.136 47.899 20.43 47.929 ;
     RECT  2.304 47.147 11.898 47.965 ;
     RECT  12.96 47.219 13.497 47.965 ;
     RECT  14.544 47.929 14.958 48.001 ;
     RECT  15.915 43.907 16.197 48.001 ;
     RECT  17.1 47.929 20.43 48.001 ;
     RECT  0.216 47.693 0.342 48.235 ;
     RECT  2.304 47.965 13.497 48.235 ;
     RECT  15.915 48.001 20.43 48.263 ;
     RECT  16.992 48.263 20.43 48.299 ;
     RECT  14.472 48.001 14.958 48.425 ;
     RECT  2.304 48.235 13.662 48.433 ;
     RECT  14.472 48.425 14.814 48.433 ;
     RECT  19.836 48.299 20.43 48.475 ;
     RECT  2.304 48.433 14.814 48.569 ;
     RECT  2.304 48.569 13.986 48.571 ;
     RECT  2.268 48.571 13.986 48.659 ;
     RECT  16.992 48.299 19.098 48.659 ;
     RECT  0.18 48.235 0.342 48.667 ;
     RECT  19.836 48.475 20.502 48.701 ;
     RECT  14.796 48.569 14.814 48.731 ;
     RECT  19.872 48.701 20.502 48.731 ;
     RECT  1.152 47.803 1.458 48.763 ;
     RECT  2.268 48.659 13.95 48.763 ;
     RECT  21.492 48.763 21.51 48.859 ;
     RECT  17.136 48.659 19.098 48.929 ;
     RECT  21.456 48.859 21.51 48.955 ;
     RECT  0.144 48.667 0.342 49.037 ;
     RECT  21.42 48.955 21.51 49.099 ;
     RECT  1.152 48.763 13.95 49.343 ;
     RECT  17.532 48.929 19.098 49.441 ;
     RECT  12.42 49.343 13.95 49.621 ;
     RECT  17.532 49.441 19.134 49.711 ;
     RECT  12.42 49.621 14.346 49.723 ;
     RECT  15.915 48.263 16.197 49.747 ;
     RECT  16.992 49.711 19.134 49.747 ;
     RECT  0.18 49.037 0.342 49.771 ;
     RECT  0.108 49.771 0.342 49.805 ;
     RECT  0.108 49.805 0.234 49.811 ;
     RECT  0.144 49.811 0.234 49.853 ;
     RECT  12.42 49.723 14.922 49.853 ;
     RECT  15.915 49.747 19.134 49.919 ;
     RECT  17.316 49.919 19.134 50.009 ;
     RECT  1.152 49.343 11.61 50.125 ;
     RECT  12.42 49.853 14.85 50.125 ;
     RECT  21.384 49.099 21.51 50.153 ;
     RECT  21.456 50.153 21.51 50.351 ;
     RECT  17.424 50.009 19.134 50.389 ;
     RECT  19.908 48.731 20.502 50.389 ;
     RECT  17.424 50.389 20.502 50.429 ;
     RECT  1.152 50.125 14.85 50.549 ;
     RECT  0.144 49.853 0.162 50.621 ;
     RECT  19.8 50.429 20.502 50.683 ;
     RECT  19.8 50.683 20.574 50.729 ;
     RECT  14.832 50.549 14.85 50.827 ;
     RECT  19.8 50.729 20.538 50.909 ;
     RECT  14.832 50.827 14.922 50.999 ;
     RECT  15.915 49.919 16.197 51.061 ;
     RECT  17.424 50.429 19.062 51.061 ;
     RECT  21.492 50.351 21.51 51.259 ;
     RECT  13.032 50.549 14.058 51.331 ;
     RECT  14.832 50.999 14.886 51.331 ;
     RECT  15.915 51.061 19.062 51.331 ;
     RECT  19.8 50.909 20.502 51.331 ;
     RECT  1.152 50.549 12.15 51.439 ;
     RECT  12.924 51.331 14.886 51.439 ;
     RECT  0.216 51.499 0.234 51.547 ;
     RECT  0.144 51.547 0.234 51.677 ;
     RECT  1.152 51.439 14.886 51.737 ;
     RECT  0.216 51.677 0.234 51.821 ;
     RECT  0.288 51.883 0.342 52.013 ;
     RECT  0.288 52.013 0.306 52.253 ;
     RECT  21.456 51.259 21.51 52.267 ;
     RECT  15.915 51.331 20.502 52.313 ;
     RECT  15.915 52.313 19.062 52.439 ;
     RECT  1.152 51.737 14.85 52.445 ;
     RECT  21.42 52.267 21.51 52.555 ;
     RECT  21.384 52.555 21.51 52.583 ;
     RECT  17.1 52.439 19.062 52.709 ;
     RECT  0.144 52.555 0.234 52.829 ;
     RECT  21.384 52.583 21.474 52.853 ;
     RECT  21.384 52.853 21.438 52.889 ;
     RECT  0.144 52.829 0.198 53.083 ;
     RECT  17.424 52.709 19.062 53.131 ;
     RECT  19.836 52.313 20.502 53.131 ;
     RECT  21.384 52.889 21.402 53.321 ;
     RECT  1.152 52.445 14.706 53.401 ;
     RECT  17.424 53.131 20.502 53.401 ;
     RECT  0.108 53.083 0.198 53.563 ;
     RECT  15.915 52.439 16.197 53.671 ;
     RECT  15.915 53.671 16.542 53.941 ;
     RECT  17.424 53.401 20.538 53.941 ;
     RECT  1.152 53.401 14.85 54.373 ;
     RECT  0.108 53.563 0.306 54.571 ;
     RECT  15.915 53.941 20.538 54.599 ;
     RECT  1.152 54.373 14.886 54.607 ;
     RECT  1.152 54.607 14.994 54.707 ;
     RECT  16.992 54.599 20.538 54.941 ;
     RECT  1.152 54.707 14.922 55.049 ;
     RECT  0.108 54.571 0.342 55.195 ;
     RECT  1.152 55.049 14.85 55.195 ;
     RECT  0.108 55.195 14.85 55.247 ;
     RECT  17.1 54.941 20.538 55.553 ;
     RECT  21.492 55.243 21.51 55.675 ;
     RECT  17.1 55.553 20.502 55.715 ;
     RECT  17.1 55.715 20.43 55.759 ;
     RECT  21.456 55.675 21.51 55.771 ;
     RECT  16.956 55.759 20.43 55.787 ;
     RECT  21.42 55.771 21.51 55.867 ;
     RECT  0.108 55.247 13.914 55.949 ;
     RECT  21.384 55.867 21.51 55.963 ;
     RECT  21.348 55.963 21.51 56.059 ;
     RECT  15.915 54.599 16.197 56.101 ;
     RECT  16.956 55.787 19.062 56.101 ;
     RECT  0.144 55.949 13.914 56.227 ;
     RECT  14.796 55.247 14.85 56.227 ;
     RECT  0.144 56.227 14.886 56.381 ;
     RECT  15.915 56.101 19.062 56.561 ;
     RECT  1.152 56.381 14.886 56.731 ;
     RECT  15.915 56.561 19.026 56.759 ;
     RECT  21.276 56.059 21.51 56.831 ;
     RECT  17.028 56.759 19.026 56.903 ;
     RECT  21.348 56.831 21.51 56.903 ;
     RECT  17.064 56.903 19.026 56.939 ;
     RECT  1.152 56.731 14.922 57.065 ;
     RECT  19.908 55.787 20.43 57.067 ;
     RECT  19.908 57.067 20.538 57.209 ;
     RECT  0.144 56.381 0.27 57.259 ;
     RECT  14.832 57.065 14.922 57.307 ;
     RECT  19.908 57.209 20.502 57.355 ;
     RECT  1.152 57.065 14.094 57.371 ;
     RECT  1.188 57.371 14.022 57.407 ;
     RECT  17.1 56.939 19.026 57.569 ;
     RECT  14.832 57.307 14.958 57.577 ;
     RECT  17.676 57.569 19.026 57.721 ;
     RECT  19.872 57.355 20.502 57.721 ;
     RECT  14.832 57.577 15.03 57.749 ;
     RECT  0.144 57.259 0.342 57.811 ;
     RECT  0.108 57.811 0.342 57.869 ;
     RECT  14.832 57.749 14.994 57.875 ;
     RECT  14.832 57.875 14.85 58.019 ;
     RECT  15.915 56.759 16.197 58.117 ;
     RECT  1.188 57.407 13.734 58.171 ;
     RECT  1.152 58.171 13.986 58.261 ;
     RECT  17.676 57.721 20.502 58.387 ;
     RECT  17.388 58.387 20.502 58.423 ;
     RECT  21.456 56.903 21.51 58.487 ;
     RECT  15.915 58.117 16.362 58.801 ;
     RECT  17.316 58.423 20.502 58.801 ;
     RECT  0.144 57.869 0.27 58.876 ;
     RECT  1.152 58.261 14.49 58.927 ;
     RECT  1.152 58.927 14.886 59.027 ;
     RECT  0.108 58.876 0.27 59.165 ;
     RECT  0.144 59.165 0.27 59.261 ;
     RECT  15.915 58.801 20.502 59.531 ;
     RECT  15.915 59.531 20.43 59.765 ;
     RECT  21.492 58.487 21.51 59.837 ;
     RECT  15.915 59.765 17.874 60.035 ;
     RECT  0.144 59.261 0.198 60.125 ;
     RECT  0.18 60.125 0.198 60.235 ;
     RECT  0.18 60.235 0.27 60.385 ;
     RECT  1.152 59.027 14.85 60.385 ;
     RECT  17.424 60.035 17.874 60.511 ;
     RECT  18.615 59.765 20.43 60.511 ;
     RECT  17.424 60.511 20.43 60.763 ;
     RECT  17.424 60.763 20.538 60.781 ;
     RECT  0.18 60.385 14.85 60.853 ;
     RECT  15.915 60.035 16.197 61.051 ;
     RECT  16.992 60.781 20.538 61.051 ;
     RECT  21.492 60.619 21.51 61.051 ;
     RECT  21.312 61.051 21.51 61.181 ;
     RECT  0.18 60.853 15.03 61.231 ;
     RECT  0.18 61.231 15.102 61.339 ;
     RECT  0.144 61.339 15.102 61.421 ;
     RECT  0.144 61.421 14.994 61.457 ;
     RECT  15.915 61.051 20.538 61.493 ;
     RECT  0.18 61.457 14.994 61.889 ;
     RECT  2.304 61.889 14.994 62.033 ;
     RECT  2.34 62.033 14.994 62.155 ;
     RECT  15.915 61.493 19.458 62.155 ;
     RECT  21.492 61.181 21.51 62.155 ;
     RECT  0.18 61.889 1.386 62.239 ;
     RECT  2.34 62.155 19.458 62.239 ;
     RECT  20.448 61.493 20.538 62.239 ;
     RECT  0.108 62.239 1.386 62.285 ;
     RECT  21.456 62.155 21.51 62.347 ;
     RECT  2.34 62.239 20.538 62.429 ;
     RECT  14.076 62.429 14.958 62.465 ;
     RECT  0.324 62.285 1.386 62.477 ;
     RECT  15.696 62.429 20.538 62.477 ;
     RECT  3.312 62.429 13.305 62.501 ;
     RECT  15.696 62.477 19.458 62.501 ;
     RECT  4.392 62.501 11.322 62.525 ;
     RECT  21.42 62.347 21.51 62.525 ;
     RECT  21.456 62.525 21.51 62.537 ;
     RECT  0.54 62.477 1.17 62.573 ;
     RECT  4.392 62.525 7.905 62.573 ;
     RECT  10.404 62.525 11.322 62.573 ;
     RECT  14.76 62.465 14.958 62.573 ;
     RECT  15.696 62.501 16.758 62.573 ;
     RECT  18.108 62.501 19.458 62.573 ;
     RECT  21.492 62.537 21.51 62.573 ;
     RECT  18.108 62.573 19.134 62.579 ;
     RECT  3.312 62.501 3.582 62.609 ;
     RECT  9.108 62.525 9.558 62.609 ;
     RECT  14.832 62.573 14.958 62.609 ;
     RECT  15.915 62.573 16.758 62.609 ;
     RECT  2.415 62.429 2.505 62.657 ;
     RECT  6.66 62.573 7.905 62.657 ;
     RECT  10.515 62.573 11.322 62.657 ;
     RECT  12.384 62.501 13.305 62.657 ;
     RECT  15.915 62.609 16.686 62.657 ;
     RECT  0.648 62.573 0.666 62.669 ;
     RECT  20.52 62.477 20.538 62.669 ;
     RECT  3.312 62.609 3.546 62.699 ;
     RECT  4.608 62.573 5.706 62.699 ;
     RECT  6.66 62.657 7.614 62.699 ;
     RECT  10.656 62.657 11.322 62.699 ;
     RECT  12.384 62.657 13.086 62.699 ;
     RECT  14.832 62.609 14.922 62.699 ;
     RECT  18.324 62.579 19.134 62.699 ;
     RECT  12.42 62.699 12.51 62.735 ;
     RECT  6.66 62.699 7.578 62.765 ;
     RECT  9.108 62.609 9.522 62.765 ;
     RECT  12.492 62.735 12.51 62.765 ;
     RECT  16.668 62.657 16.686 62.765 ;
     RECT  3.312 62.699 3.51 62.771 ;
     RECT  10.656 62.699 10.998 62.771 ;
     RECT  3.312 62.771 3.33 62.807 ;
     RECT  4.608 62.699 5.202 62.807 ;
     RECT  4.608 62.807 5.094 62.813 ;
     RECT  6.66 62.765 6.822 62.813 ;
     RECT  9.504 62.765 9.522 62.843 ;
     RECT  10.98 62.771 10.998 62.843 ;
     RECT  4.608 62.813 4.626 62.879 ;
     RECT  6.804 62.813 6.822 62.879 ;
     RECT  7.56 62.765 7.578 63.821 ;
    LAYER M4 ;
     RECT  0.06 0.624 0.137 62.76 ;
     RECT  0.137 0.72 3.305 62.76 ;
     RECT  3.305 0.816 5.065 62.76 ;
     RECT  5.065 0.816 5.852 62.808 ;
     RECT  5.852 0.096 5.939 62.808 ;
     RECT  5.939 0.816 6.689 62.808 ;
     RECT  6.689 0.816 7.193 62.76 ;
     RECT  0.06 63.792 7.589 63.816 ;
     RECT  7.193 1.344 7.912 62.652 ;
     RECT  7.912 1.344 8.525 62.52 ;
     RECT  8.525 2.016 9.097 62.52 ;
     RECT  9.097 2.016 10.931 62.76 ;
     RECT  10.931 2.064 12.233 62.76 ;
     RECT  12.233 2.256 12.521 62.76 ;
     RECT  12.521 2.256 13.097 62.664 ;
     RECT  13.097 2.256 13.208 62.652 ;
     RECT  13.208 2.148 13.312 62.652 ;
     RECT  13.312 2.352 13.504 62.382 ;
     RECT  13.504 4.704 13.601 47.592 ;
     RECT  13.601 7.872 13.745 47.592 ;
     RECT  13.504 61.968 13.853 62.28 ;
     RECT  13.853 61.968 13.889 62.232 ;
     RECT  13.504 48.672 13.961 60.84 ;
     RECT  13.601 4.704 14.105 6.84 ;
     RECT  13.889 62.208 14.821 62.232 ;
     RECT  14.105 4.896 14.861 6.84 ;
     RECT  13.745 34.08 14.893 47.592 ;
     RECT  13.745 7.872 14.897 33 ;
     RECT  14.897 7.92 14.933 33 ;
     RECT  14.821 62.208 15.361 62.472 ;
     RECT  15.361 62.16 15.685 62.472 ;
     RECT  15.289 0.528 15.731 0.552 ;
     RECT  13.504 2.352 15.908 3.048 ;
     RECT  14.861 4.992 15.908 6.84 ;
     RECT  14.933 7.92 15.908 32.856 ;
     RECT  14.893 34.08 15.908 47.688 ;
     RECT  13.961 48.672 15.908 52.824 ;
     RECT  13.961 53.808 15.908 60.84 ;
     RECT  15.685 62.16 15.908 62.52 ;
     RECT  15.908 2.148 16.204 62.652 ;
     RECT  16.204 2.148 16.261 3.192 ;
     RECT  16.204 61.968 16.657 62.652 ;
     RECT  16.204 7.92 17.021 32.856 ;
     RECT  16.204 53.808 17.021 60.84 ;
     RECT  16.261 1.536 17.053 3.192 ;
     RECT  17.021 7.92 17.129 30.408 ;
     RECT  17.021 31.44 17.129 32.856 ;
     RECT  16.204 34.08 17.129 47.688 ;
     RECT  17.053 0.96 17.233 3.192 ;
     RECT  17.129 46.848 17.413 47.688 ;
     RECT  16.204 48.672 17.413 52.824 ;
     RECT  16.204 4.416 17.453 6.84 ;
     RECT  17.129 7.92 17.453 30.12 ;
     RECT  17.413 46.848 17.485 52.824 ;
     RECT  17.021 53.808 17.485 54.36 ;
     RECT  17.021 55.488 17.593 60.84 ;
     RECT  16.657 61.968 17.593 62.76 ;
     RECT  17.233 0.624 17.773 3.192 ;
     RECT  17.453 4.992 18.169 6.84 ;
     RECT  17.453 7.92 18.169 18.984 ;
     RECT  17.773 0.624 18.608 3.96 ;
     RECT  18.169 4.992 18.608 18.984 ;
     RECT  17.453 20.064 18.608 30.12 ;
     RECT  17.129 31.44 18.608 32.76 ;
     RECT  17.129 34.08 18.608 45.816 ;
     RECT  17.485 46.848 18.608 54.36 ;
     RECT  17.593 55.488 18.608 62.76 ;
     RECT  18.608 0.624 18.904 62.76 ;
     RECT  18.904 6.336 19.897 11.112 ;
     RECT  18.904 12.096 19.897 46.392 ;
     RECT  18.904 47.616 19.897 55.512 ;
     RECT  18.904 56.544 19.897 62.76 ;
     RECT  18.904 0.624 20.185 4.968 ;
     RECT  20.185 0.624 20.401 5.16 ;
     RECT  19.897 6.336 20.401 62.76 ;
     RECT  20.401 0.624 21.564 62.76 ;
    LAYER M5 ;
     RECT  15.696 0.016 15.72 0.563 ;
     RECT  5.904 0.085 5.928 2.137 ;
     RECT  8.736 2.005 9.336 2.137 ;
     RECT  10.896 2.005 10.92 2.137 ;
     RECT  2.4 2.137 2.52 2.151 ;
     RECT  13.2 2.137 13.32 2.151 ;
     RECT  15.9 2.137 16.02 2.151 ;
     RECT  18.6 2.137 18.72 2.151 ;
     RECT  2.4 2.151 2.712 2.293 ;
     RECT  2.4 2.293 2.808 2.435 ;
     RECT  13.2 2.151 13.512 2.485 ;
     RECT  5.1 2.137 5.928 2.581 ;
     RECT  10.5 2.137 10.92 2.677 ;
     RECT  7.8 2.137 9.336 2.771 ;
     RECT  4.944 2.581 5.928 3.251 ;
     RECT  7.8 2.771 8.112 3.397 ;
     RECT  12.96 2.485 13.512 3.491 ;
     RECT  4.992 3.251 5.928 3.493 ;
     RECT  7.44 3.397 8.112 3.493 ;
     RECT  4.992 3.493 8.112 3.635 ;
     RECT  10.5 2.677 10.968 3.635 ;
     RECT  0.144 3.061 0.168 3.637 ;
     RECT  2.4 2.435 2.712 3.685 ;
     RECT  9.312 2.771 9.336 3.733 ;
     RECT  0.144 3.637 0.264 3.827 ;
     RECT  2.4 3.685 3.144 3.875 ;
     RECT  9.12 3.733 9.336 3.971 ;
     RECT  9.12 3.971 9.144 4.067 ;
     RECT  0.144 3.827 0.168 4.547 ;
     RECT  5.1 3.635 8.112 4.787 ;
     RECT  5.1 4.787 5.928 4.789 ;
     RECT  10.5 3.635 10.92 5.221 ;
     RECT  13.2 3.491 13.512 5.365 ;
     RECT  9.12 5.317 9.144 5.555 ;
     RECT  10.5 5.221 11.064 5.651 ;
     RECT  13.056 5.365 13.512 5.651 ;
     RECT  2.4 3.875 2.712 5.653 ;
     RECT  4.272 4.789 5.928 5.653 ;
     RECT  2.4 5.653 5.928 5.795 ;
     RECT  4.176 5.795 5.928 5.939 ;
     RECT  4.896 5.939 5.928 6.179 ;
     RECT  2.4 5.795 2.712 6.181 ;
     RECT  10.5 5.651 10.968 6.421 ;
     RECT  13.2 5.651 13.512 6.565 ;
     RECT  4.992 6.179 5.928 6.613 ;
     RECT  13.2 6.565 13.944 6.707 ;
     RECT  4.992 6.613 6.216 6.757 ;
     RECT  10.032 6.421 10.968 6.949 ;
     RECT  9.744 6.949 10.968 7.141 ;
     RECT  2.304 6.181 2.712 7.235 ;
     RECT  2.4 7.235 2.712 7.381 ;
     RECT  4.992 6.757 6.264 7.475 ;
     RECT  2.4 7.381 3.096 7.523 ;
     RECT  9.6 7.141 10.968 7.717 ;
     RECT  9.6 7.717 11.256 8.003 ;
     RECT  7.8 4.787 8.112 8.341 ;
     RECT  2.4 7.523 2.712 8.485 ;
     RECT  5.1 7.475 6.264 8.533 ;
     RECT  13.2 6.707 13.512 8.773 ;
     RECT  7.8 8.341 8.232 9.013 ;
     RECT  0.144 6.613 0.168 9.059 ;
     RECT  9.744 8.003 11.256 9.061 ;
     RECT  2.304 8.485 2.712 9.107 ;
     RECT  4.944 8.533 6.264 9.205 ;
     RECT  4.704 9.205 6.264 9.253 ;
     RECT  2.4 9.107 2.712 9.541 ;
     RECT  0.192 9.301 0.216 9.587 ;
     RECT  2.4 9.541 3.624 9.683 ;
     RECT  4.704 9.253 6.36 9.733 ;
     RECT  7.344 9.013 8.232 9.733 ;
     RECT  1.248 9.829 1.272 9.877 ;
     RECT  4.704 9.733 8.232 9.877 ;
     RECT  9.744 9.061 11.352 9.877 ;
     RECT  4.512 9.877 11.352 10.019 ;
     RECT  5.1 10.019 11.352 10.067 ;
     RECT  1.152 9.877 1.272 10.163 ;
     RECT  5.1 10.067 8.232 10.163 ;
     RECT  9.216 10.067 11.352 10.211 ;
     RECT  13.008 8.773 13.512 10.211 ;
     RECT  2.4 9.683 2.712 10.213 ;
     RECT  5.1 10.163 8.112 10.259 ;
     RECT  2.304 10.213 2.712 10.451 ;
     RECT  1.152 10.163 1.176 10.547 ;
     RECT  9.552 10.211 11.352 10.547 ;
     RECT  9.552 10.547 11.16 10.739 ;
     RECT  2.4 10.451 2.712 11.557 ;
     RECT  5.1 10.259 6.36 11.651 ;
     RECT  2.4 11.557 2.808 11.699 ;
     RECT  9.552 10.739 10.812 11.699 ;
     RECT  7.344 10.259 8.112 11.747 ;
     RECT  9.792 11.699 10.812 12.373 ;
     RECT  3.984 12.469 4.008 12.613 ;
     RECT  5.1 11.651 5.928 12.613 ;
     RECT  3.984 12.613 5.928 12.659 ;
     RECT  4.56 12.659 5.928 13.091 ;
     RECT  14.832 12.853 14.856 13.091 ;
     RECT  9.792 12.373 10.92 13.141 ;
     RECT  9.456 13.141 11.304 13.189 ;
     RECT  7.632 11.747 8.112 13.285 ;
     RECT  9.312 13.189 11.304 13.427 ;
     RECT  1.152 13.381 1.176 13.571 ;
     RECT  9.456 13.427 11.304 13.667 ;
     RECT  5.1 13.091 5.928 13.765 ;
     RECT  6.96 13.285 8.112 13.765 ;
     RECT  12.192 14.341 12.216 14.483 ;
     RECT  5.1 13.765 8.112 14.531 ;
     RECT  5.1 14.531 6.648 14.915 ;
     RECT  9.456 13.667 11.208 15.013 ;
     RECT  0.144 15.109 0.168 15.347 ;
     RECT  2.4 11.699 2.712 15.493 ;
     RECT  9.456 15.013 11.304 16.019 ;
     RECT  5.1 14.915 5.928 16.069 ;
     RECT  5.1 16.069 6.312 16.211 ;
     RECT  5.1 16.211 5.928 16.405 ;
     RECT  2.304 15.493 2.712 16.547 ;
     RECT  4.752 16.405 5.928 16.547 ;
     RECT  9.936 16.019 11.304 16.595 ;
     RECT  9.936 16.595 11.208 17.077 ;
     RECT  9.456 17.077 11.208 17.219 ;
     RECT  9.984 17.219 11.208 17.555 ;
     RECT  5.1 16.547 5.928 17.845 ;
     RECT  4.992 17.845 5.928 18.469 ;
     RECT  0.192 18.613 0.216 18.803 ;
     RECT  2.4 16.547 2.712 18.805 ;
     RECT  2.4 18.805 2.904 19.189 ;
     RECT  7.632 14.531 8.112 19.237 ;
     RECT  7.584 19.237 8.112 19.333 ;
     RECT  10.5 17.555 11.208 19.333 ;
     RECT  4.512 18.469 5.928 19.429 ;
     RECT  4.416 19.429 5.928 19.715 ;
     RECT  2.4 19.189 3.192 19.861 ;
     RECT  0.144 19.621 0.168 19.907 ;
     RECT  7.584 19.333 8.328 19.909 ;
     RECT  2.4 19.861 3.816 20.003 ;
     RECT  13.2 10.211 13.512 20.149 ;
     RECT  10.5 19.333 11.4 20.245 ;
     RECT  12.768 20.149 13.512 20.291 ;
     RECT  1.152 20.101 1.176 20.339 ;
     RECT  10.5 20.245 11.544 20.483 ;
     RECT  7.584 19.909 9.096 20.579 ;
     RECT  2.4 20.003 3.576 21.011 ;
     RECT  5.1 19.715 5.928 21.205 ;
     RECT  2.4 21.011 2.808 21.299 ;
     RECT  4.848 21.205 5.928 21.347 ;
     RECT  2.4 21.299 2.712 21.541 ;
     RECT  2.304 21.541 2.712 21.731 ;
     RECT  10.5 20.483 11.4 22.307 ;
     RECT  5.1 21.347 5.928 22.309 ;
     RECT  7.584 20.579 8.328 22.309 ;
     RECT  7.584 22.309 9.24 22.787 ;
     RECT  7.584 22.787 9.096 22.835 ;
     RECT  5.1 22.309 6.024 22.885 ;
     RECT  5.1 22.885 6.264 22.981 ;
     RECT  2.4 21.731 2.712 23.125 ;
     RECT  4.8 22.981 6.264 23.219 ;
     RECT  2.4 23.125 3.336 23.603 ;
     RECT  5.1 23.219 6.264 24.373 ;
     RECT  10.5 22.307 11.16 24.419 ;
     RECT  10.5 24.419 10.92 24.469 ;
     RECT  4.896 24.373 6.264 24.515 ;
     RECT  7.584 22.835 8.328 24.757 ;
     RECT  9.648 24.469 10.92 24.757 ;
     RECT  5.1 24.515 6.264 25.187 ;
     RECT  0.144 25.285 0.168 25.475 ;
     RECT  7.584 24.757 10.92 25.523 ;
     RECT  10.368 25.523 10.92 25.811 ;
     RECT  12.048 25.765 12.216 26.147 ;
     RECT  7.584 25.523 9.144 26.197 ;
     RECT  10.5 25.811 10.92 26.245 ;
     RECT  12.048 26.147 12.072 26.245 ;
     RECT  13.2 20.291 13.512 26.293 ;
     RECT  7.488 26.197 9.144 26.483 ;
     RECT  7.488 26.483 8.424 26.675 ;
     RECT  10.5 26.245 12.072 26.675 ;
     RECT  10.5 26.675 10.92 26.773 ;
     RECT  5.1 25.187 5.928 27.253 ;
     RECT  0.144 27.157 0.168 27.347 ;
     RECT  9.552 26.773 10.92 27.395 ;
     RECT  4.992 27.253 5.928 27.635 ;
     RECT  2.4 23.603 2.712 27.685 ;
     RECT  9.552 27.395 10.812 27.779 ;
     RECT  13.2 26.293 13.608 28.019 ;
     RECT  7.488 26.675 8.328 28.021 ;
     RECT  7.488 28.021 8.52 28.069 ;
     RECT  7.488 28.069 9.144 28.403 ;
     RECT  7.488 28.403 8.568 28.595 ;
     RECT  10.5 27.779 10.812 28.645 ;
     RECT  10.5 28.645 11.064 28.979 ;
     RECT  0.144 28.741 0.168 29.027 ;
     RECT  2.4 27.685 3.576 29.077 ;
     RECT  5.1 27.635 5.928 29.077 ;
     RECT  7.584 28.595 8.568 29.315 ;
     RECT  2.4 29.077 5.928 29.507 ;
     RECT  2.4 29.507 4.056 29.747 ;
     RECT  10.5 28.979 10.812 29.797 ;
     RECT  9.6 29.797 10.812 29.987 ;
     RECT  5.1 29.507 5.928 30.421 ;
     RECT  2.4 29.747 3.816 30.947 ;
     RECT  2.4 30.947 3.528 31.091 ;
     RECT  7.584 29.315 8.328 31.189 ;
     RECT  10.368 29.987 10.812 31.285 ;
     RECT  2.4 31.091 2.808 31.333 ;
     RECT  2.304 31.333 2.808 31.379 ;
     RECT  7.584 31.189 8.424 31.477 ;
     RECT  5.1 30.421 6.168 31.525 ;
     RECT  7.584 31.477 9.144 31.715 ;
     RECT  7.584 31.715 8.424 31.811 ;
     RECT  0.144 31.717 0.168 31.907 ;
     RECT  10.224 31.285 10.812 31.955 ;
     RECT  4.704 31.525 6.168 32.101 ;
     RECT  4.56 32.101 6.168 32.485 ;
     RECT  2.304 31.379 2.712 32.627 ;
     RECT  4.32 32.485 6.168 32.675 ;
     RECT  10.5 31.955 10.812 32.725 ;
     RECT  1.248 32.725 1.272 32.867 ;
     RECT  10.5 32.725 11.064 32.867 ;
     RECT  0.144 32.869 0.168 33.059 ;
     RECT  4.56 32.675 6.168 33.107 ;
     RECT  7.8 31.811 8.328 33.157 ;
     RECT  4.56 33.107 5.928 33.203 ;
     RECT  7.584 33.157 8.52 33.395 ;
     RECT  7.8 33.395 8.52 33.589 ;
     RECT  4.56 33.203 5.412 33.779 ;
     RECT  2.4 32.627 2.712 34.117 ;
     RECT  13.2 28.019 13.512 34.597 ;
     RECT  7.8 33.589 9.144 34.691 ;
     RECT  10.5 32.867 10.812 34.693 ;
     RECT  1.152 34.405 1.176 34.739 ;
     RECT  0.144 34.549 0.168 34.787 ;
     RECT  2.4 34.117 3.672 34.787 ;
     RECT  13.2 34.597 13.656 35.459 ;
     RECT  14.784 34.885 14.808 35.939 ;
     RECT  7.8 34.691 8.52 36.709 ;
     RECT  9.648 34.693 10.812 36.709 ;
     RECT  7.8 36.709 10.812 36.851 ;
     RECT  2.4 34.787 2.712 36.853 ;
     RECT  0.144 36.805 0.168 36.995 ;
     RECT  2.4 36.853 2.808 37.043 ;
     RECT  5.1 33.779 5.412 37.237 ;
     RECT  9.744 36.851 10.812 37.333 ;
     RECT  12.048 26.675 12.072 37.333 ;
     RECT  4.656 37.237 5.412 37.379 ;
     RECT  6.768 36.997 6.792 37.573 ;
     RECT  9.744 37.333 12.072 37.619 ;
     RECT  6.432 37.573 6.792 38.245 ;
     RECT  7.8 36.851 8.52 38.245 ;
     RECT  9.744 37.619 10.968 38.291 ;
     RECT  6.432 38.245 8.52 38.435 ;
     RECT  2.4 37.043 2.712 38.437 ;
     RECT  2.4 38.437 2.808 38.579 ;
     RECT  9.744 38.291 10.92 38.723 ;
     RECT  2.4 38.579 2.712 38.725 ;
     RECT  20.688 38.581 20.712 38.771 ;
     RECT  2.304 38.725 2.712 39.011 ;
     RECT  1.248 39.013 1.272 39.109 ;
     RECT  1.152 39.109 1.272 39.299 ;
     RECT  10.224 38.723 10.92 39.299 ;
     RECT  5.1 37.379 5.412 39.301 ;
     RECT  1.152 39.299 1.176 39.347 ;
     RECT  6.432 38.435 6.792 39.589 ;
     RECT  7.8 38.435 8.52 39.589 ;
     RECT  10.224 39.299 10.812 39.827 ;
     RECT  0.144 39.685 0.168 39.923 ;
     RECT  4.56 39.301 5.412 39.923 ;
     RECT  13.2 35.459 13.512 40.069 ;
     RECT  13.056 40.069 13.512 40.403 ;
     RECT  2.4 39.011 2.712 40.741 ;
     RECT  6.432 39.589 8.52 40.837 ;
     RECT  0.288 40.885 0.312 41.027 ;
     RECT  6.432 40.837 8.904 41.219 ;
     RECT  5.1 39.923 5.412 41.221 ;
     RECT  6.528 41.219 8.904 41.317 ;
     RECT  6.528 41.317 9.048 41.365 ;
     RECT  10.5 39.827 10.812 41.365 ;
     RECT  4.272 41.221 5.412 41.411 ;
     RECT  6.528 41.365 10.812 41.603 ;
     RECT  2.4 40.741 2.808 41.653 ;
     RECT  6.528 41.603 8.52 41.747 ;
     RECT  2.4 41.653 2.952 41.795 ;
     RECT  14.832 41.701 14.856 41.939 ;
     RECT  2.4 41.795 2.808 42.179 ;
     RECT  0.144 42.277 0.168 42.467 ;
     RECT  0.192 42.565 1.176 42.707 ;
     RECT  9.6 41.603 10.812 42.709 ;
     RECT  0.192 42.707 0.216 42.755 ;
     RECT  9.6 42.709 11.064 42.899 ;
     RECT  4.944 41.411 5.412 42.997 ;
     RECT  4.368 42.997 5.412 43.139 ;
     RECT  6.528 41.747 6.552 43.573 ;
     RECT  7.8 41.747 8.52 43.573 ;
     RECT  2.4 42.179 2.712 43.765 ;
     RECT  6.528 43.573 8.52 44.053 ;
     RECT  9.6 42.899 10.812 44.053 ;
     RECT  12.048 37.619 12.072 44.053 ;
     RECT  6.528 44.053 12.072 44.099 ;
     RECT  7.008 44.099 12.072 44.195 ;
     RECT  4.944 43.139 5.412 44.389 ;
     RECT  4.56 44.389 5.412 44.867 ;
     RECT  7.8 44.195 12.072 45.349 ;
     RECT  7.68 45.349 12.072 45.539 ;
     RECT  2.304 43.765 2.712 45.925 ;
     RECT  2.304 45.925 2.952 46.067 ;
     RECT  7.8 45.539 12.072 46.067 ;
     RECT  2.304 46.067 2.712 46.739 ;
     RECT  7.8 46.067 9.144 48.085 ;
     RECT  2.4 46.739 2.712 48.709 ;
     RECT  2.4 48.709 3.528 48.757 ;
     RECT  10.368 46.067 12.072 48.947 ;
     RECT  1.824 48.757 3.528 48.995 ;
     RECT  5.1 44.867 5.412 49.045 ;
     RECT  0.144 46.549 0.168 49.235 ;
     RECT  2.4 48.995 3.528 49.235 ;
     RECT  4.944 49.045 5.412 49.379 ;
     RECT  1.152 49.333 1.176 49.571 ;
     RECT  10.368 48.947 10.92 49.955 ;
     RECT  13.2 40.403 13.512 50.293 ;
     RECT  7.8 48.085 9.384 50.387 ;
     RECT  2.4 49.235 2.712 50.389 ;
     RECT  5.1 49.379 5.412 50.629 ;
     RECT  13.2 50.293 13.656 50.771 ;
     RECT  7.8 50.387 8.328 51.061 ;
     RECT  1.152 50.917 1.176 51.203 ;
     RECT  7.44 51.061 8.328 51.251 ;
     RECT  2.4 50.389 2.808 51.253 ;
     RECT  9.36 50.387 9.384 51.253 ;
     RECT  10.368 49.955 10.812 51.253 ;
     RECT  2.4 51.253 2.904 51.779 ;
     RECT  13.2 50.771 13.608 51.923 ;
     RECT  7.68 51.251 8.328 52.019 ;
     RECT  0.144 51.973 0.168 52.163 ;
     RECT  2.4 51.779 2.808 52.163 ;
     RECT  7.8 52.019 8.328 52.405 ;
     RECT  9.36 51.253 10.812 52.405 ;
     RECT  5.1 50.629 5.928 52.499 ;
     RECT  5.1 52.499 5.412 52.885 ;
     RECT  13.2 51.923 13.512 52.981 ;
     RECT  1.2 52.501 1.224 53.027 ;
     RECT  7.8 52.405 10.812 53.171 ;
     RECT  4.512 52.885 5.412 53.267 ;
     RECT  7.8 53.171 8.112 53.509 ;
     RECT  12.048 48.947 12.072 53.509 ;
     RECT  2.4 52.163 2.712 53.701 ;
     RECT  5.1 53.267 5.412 53.845 ;
     RECT  6.912 53.509 8.112 53.845 ;
     RECT  2.4 53.701 2.808 53.939 ;
     RECT  2.4 53.939 2.712 53.941 ;
     RECT  11.952 53.509 12.072 54.131 ;
     RECT  12.048 54.131 12.072 54.133 ;
     RECT  13.2 52.981 13.656 54.133 ;
     RECT  12.048 54.133 13.656 54.179 ;
     RECT  12.384 54.179 13.656 54.371 ;
     RECT  5.1 53.845 8.112 54.419 ;
     RECT  2.304 53.941 2.712 54.467 ;
     RECT  9.36 53.171 10.812 54.517 ;
     RECT  0.144 53.701 0.168 54.707 ;
     RECT  5.1 54.419 6.168 54.901 ;
     RECT  9.12 54.517 10.812 54.947 ;
     RECT  4.56 54.901 6.168 55.333 ;
     RECT  12.384 54.371 13.512 55.525 ;
     RECT  4.128 55.333 6.168 55.813 ;
     RECT  9.36 54.947 10.812 55.859 ;
     RECT  2.4 54.467 2.712 56.197 ;
     RECT  4.128 55.813 6.264 56.197 ;
     RECT  9.648 55.859 10.812 56.341 ;
     RECT  11.952 55.525 13.512 56.341 ;
     RECT  2.4 56.197 6.264 56.435 ;
     RECT  9.648 56.341 13.512 56.723 ;
     RECT  1.152 56.629 1.176 56.773 ;
     RECT  1.152 56.773 1.272 56.819 ;
     RECT  1.248 56.819 1.272 56.915 ;
     RECT  7.8 54.419 8.112 57.109 ;
     RECT  2.4 56.435 5.544 57.251 ;
     RECT  9.648 56.723 10.92 57.635 ;
     RECT  12.384 56.723 13.512 57.731 ;
     RECT  7.008 57.109 8.112 58.019 ;
     RECT  10.032 57.635 10.92 58.115 ;
     RECT  10.5 58.115 10.92 58.117 ;
     RECT  2.4 57.251 5.412 58.307 ;
     RECT  2.4 58.307 2.904 58.451 ;
     RECT  13.2 57.731 13.512 58.645 ;
     RECT  0.144 58.213 0.168 58.691 ;
     RECT  7.8 58.019 8.112 59.125 ;
     RECT  13.2 58.645 13.608 59.219 ;
     RECT  4.224 58.307 5.412 59.651 ;
     RECT  9.12 59.557 9.144 59.699 ;
     RECT  7.152 59.125 8.112 59.891 ;
     RECT  13.2 59.219 13.512 59.893 ;
     RECT  4.32 59.651 5.412 59.941 ;
     RECT  12.528 59.893 13.512 60.035 ;
     RECT  10.5 58.117 11.208 60.277 ;
     RECT  4.32 59.941 5.544 60.323 ;
     RECT  10.272 60.277 11.208 60.563 ;
     RECT  2.4 58.451 2.808 60.805 ;
     RECT  0.144 60.181 0.168 60.851 ;
     RECT  7.68 59.891 8.112 60.851 ;
     RECT  12.624 60.035 13.512 60.851 ;
     RECT  2.4 60.805 3.144 60.995 ;
     RECT  4.368 60.323 5.544 61.283 ;
     RECT  2.4 60.995 2.808 61.331 ;
     RECT  4.896 61.283 5.544 61.331 ;
     RECT  21.408 61.141 21.432 61.331 ;
     RECT  4.992 61.331 5.544 61.427 ;
     RECT  0.192 61.093 1.272 61.475 ;
     RECT  10.5 60.563 11.208 61.669 ;
     RECT  10.224 61.669 11.208 61.763 ;
     RECT  1.152 61.475 1.272 61.811 ;
     RECT  10.224 61.763 10.812 62.051 ;
     RECT  0.144 61.909 0.168 62.483 ;
     RECT  4.992 61.427 5.412 62.531 ;
     RECT  1.248 61.811 1.272 62.579 ;
     RECT  2.4 61.331 2.712 62.649 ;
     RECT  5.1 62.531 5.412 62.649 ;
     RECT  7.8 60.851 8.112 62.649 ;
     RECT  10.5 62.051 10.812 62.649 ;
     RECT  13.2 60.851 13.512 62.649 ;
     RECT  15.9 2.151 16.212 62.649 ;
     RECT  18.6 2.151 18.912 62.649 ;
     RECT  2.4 62.649 2.52 62.663 ;
     RECT  5.1 62.649 5.22 62.663 ;
     RECT  7.8 62.649 7.92 62.663 ;
     RECT  10.5 62.649 10.62 62.663 ;
     RECT  13.2 62.649 13.32 62.663 ;
     RECT  15.9 62.649 16.02 62.663 ;
     RECT  18.6 62.649 18.72 62.663 ;
  END
END hbfd_rly_624_EW_rr
END LIBRARY
